VERSION 5.8 ;
BUSBITCHARS "[]" ;
DIVIDERCHAR "/" ;
UNITS
    DATABASE MICRONS 1000 ;
END UNITS

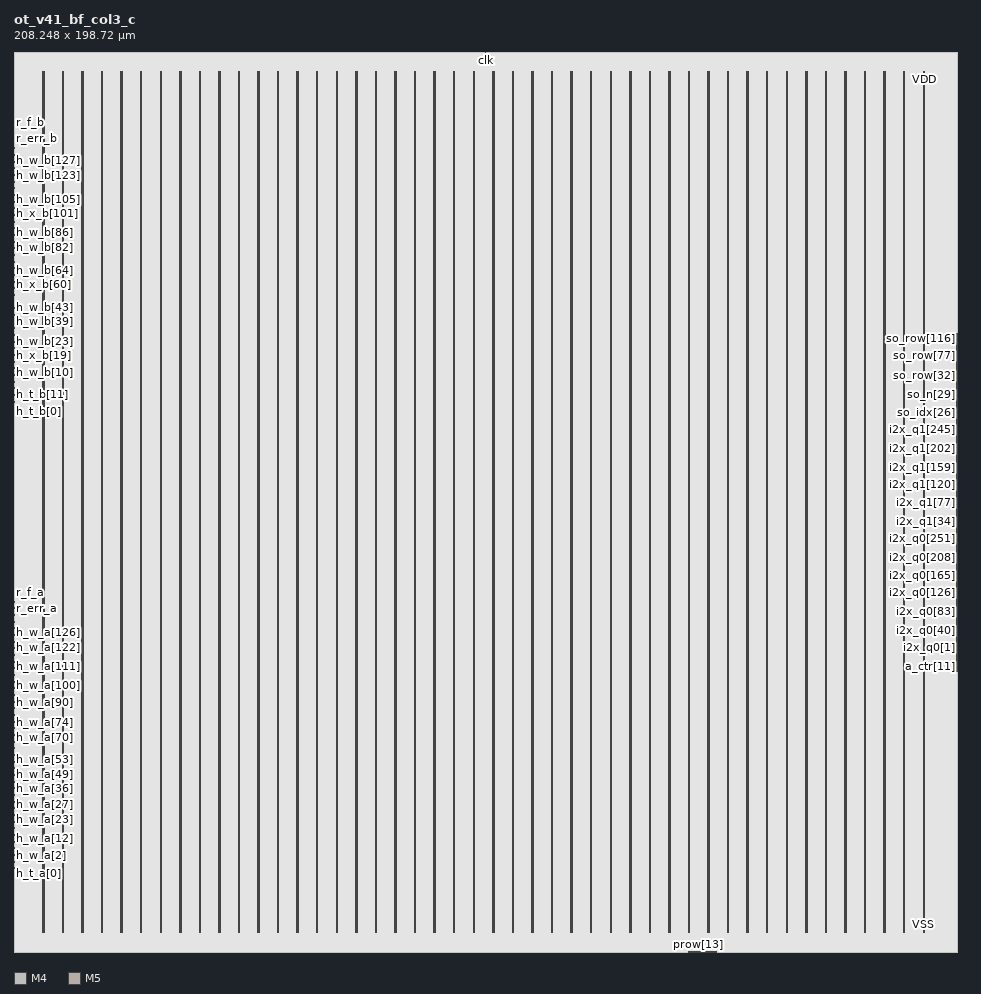
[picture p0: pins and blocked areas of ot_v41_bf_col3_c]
MACRO ot_v41_bf_col3_c
  FOREIGN ot_v41_bf_col3_c 0 0 ;
  CLASS BLOCK ;
  SIZE 208.248 BY 198.72 ;
  PIN a_ctr[0]
    DIRECTION INPUT ;
    USE SIGNAL ;
    PORT
      LAYER M4 ;
        RECT  208.164 62.016 208.248 62.04 ;
    END
  END a_ctr[0]
  PIN a_ctr[10]
    DIRECTION INPUT ;
    USE SIGNAL ;
    PORT
      LAYER M4 ;
        RECT  208.164 62.976 208.248 63 ;
    END
  END a_ctr[10]
  PIN a_ctr[11]
    DIRECTION INPUT ;
    USE SIGNAL ;
    PORT
      LAYER M4 ;
        RECT  208.164 63.072 208.248 63.096 ;
    END
  END a_ctr[11]
  PIN a_ctr[12]
    DIRECTION INPUT ;
    USE SIGNAL ;
    PORT
      LAYER M4 ;
        RECT  208.164 63.168 208.248 63.192 ;
    END
  END a_ctr[12]
  PIN a_ctr[13]
    DIRECTION INPUT ;
    USE SIGNAL ;
    PORT
      LAYER M4 ;
        RECT  208.164 63.264 208.248 63.288 ;
    END
  END a_ctr[13]
  PIN a_ctr[1]
    DIRECTION INPUT ;
    USE SIGNAL ;
    PORT
      LAYER M4 ;
        RECT  208.164 62.112 208.248 62.136 ;
    END
  END a_ctr[1]
  PIN a_ctr[2]
    DIRECTION INPUT ;
    USE SIGNAL ;
    PORT
      LAYER M4 ;
        RECT  208.164 62.208 208.248 62.232 ;
    END
  END a_ctr[2]
  PIN a_ctr[3]
    DIRECTION INPUT ;
    USE SIGNAL ;
    PORT
      LAYER M4 ;
        RECT  208.164 62.304 208.248 62.328 ;
    END
  END a_ctr[3]
  PIN a_ctr[4]
    DIRECTION INPUT ;
    USE SIGNAL ;
    PORT
      LAYER M4 ;
        RECT  208.164 62.4 208.248 62.424 ;
    END
  END a_ctr[4]
  PIN a_ctr[5]
    DIRECTION INPUT ;
    USE SIGNAL ;
    PORT
      LAYER M4 ;
        RECT  208.164 62.496 208.248 62.52 ;
    END
  END a_ctr[5]
  PIN a_ctr[6]
    DIRECTION INPUT ;
    USE SIGNAL ;
    PORT
      LAYER M4 ;
        RECT  208.164 62.592 208.248 62.616 ;
    END
  END a_ctr[6]
  PIN a_ctr[7]
    DIRECTION INPUT ;
    USE SIGNAL ;
    PORT
      LAYER M4 ;
        RECT  208.164 62.688 208.248 62.712 ;
    END
  END a_ctr[7]
  PIN a_ctr[8]
    DIRECTION INPUT ;
    USE SIGNAL ;
    PORT
      LAYER M4 ;
        RECT  208.164 62.784 208.248 62.808 ;
    END
  END a_ctr[8]
  PIN a_ctr[9]
    DIRECTION INPUT ;
    USE SIGNAL ;
    PORT
      LAYER M4 ;
        RECT  208.164 62.88 208.248 62.904 ;
    END
  END a_ctr[9]
  PIN clk
    DIRECTION INPUT ;
    USE SIGNAL ;
    PORT
      LAYER M5 ;
        RECT  104.1 198.24 104.148 198.72 ;
    END
  END clk
  PIN h_rst_a
    DIRECTION OUTPUT ;
    USE SIGNAL ;
    PORT
      LAYER M4 ;
        RECT  0 20.064 0.084 20.088 ;
    END
  END h_rst_a
  PIN h_rst_b
    DIRECTION OUTPUT ;
    USE SIGNAL ;
    PORT
      LAYER M4 ;
        RECT  0 123.744 0.084 123.768 ;
    END
  END h_rst_b
  PIN h_t_a[0]
    DIRECTION OUTPUT ;
    USE SIGNAL ;
    PORT
      LAYER M4 ;
        RECT  0 17.376 0.084 17.4 ;
    END
  END h_t_a[0]
  PIN h_t_a[10]
    DIRECTION OUTPUT ;
    USE SIGNAL ;
    PORT
      LAYER M4 ;
        RECT  0 19.296 0.084 19.32 ;
    END
  END h_t_a[10]
  PIN h_t_a[11]
    DIRECTION OUTPUT ;
    USE SIGNAL ;
    PORT
      LAYER M4 ;
        RECT  0 19.488 0.084 19.512 ;
    END
  END h_t_a[11]
  PIN h_t_a[12]
    DIRECTION OUTPUT ;
    USE SIGNAL ;
    PORT
      LAYER M4 ;
        RECT  0 19.68 0.084 19.704 ;
    END
  END h_t_a[12]
  PIN h_t_a[1]
    DIRECTION OUTPUT ;
    USE SIGNAL ;
    PORT
      LAYER M4 ;
        RECT  0 17.568 0.084 17.592 ;
    END
  END h_t_a[1]
  PIN h_t_a[2]
    DIRECTION OUTPUT ;
    USE SIGNAL ;
    PORT
      LAYER M4 ;
        RECT  0 17.76 0.084 17.784 ;
    END
  END h_t_a[2]
  PIN h_t_a[3]
    DIRECTION OUTPUT ;
    USE SIGNAL ;
    PORT
      LAYER M4 ;
        RECT  0 17.952 0.084 17.976 ;
    END
  END h_t_a[3]
  PIN h_t_a[4]
    DIRECTION OUTPUT ;
    USE SIGNAL ;
    PORT
      LAYER M4 ;
        RECT  0 18.144 0.084 18.168 ;
    END
  END h_t_a[4]
  PIN h_t_a[5]
    DIRECTION OUTPUT ;
    USE SIGNAL ;
    PORT
      LAYER M4 ;
        RECT  0 18.336 0.084 18.36 ;
    END
  END h_t_a[5]
  PIN h_t_a[6]
    DIRECTION OUTPUT ;
    USE SIGNAL ;
    PORT
      LAYER M4 ;
        RECT  0 18.528 0.084 18.552 ;
    END
  END h_t_a[6]
  PIN h_t_a[7]
    DIRECTION OUTPUT ;
    USE SIGNAL ;
    PORT
      LAYER M4 ;
        RECT  0 18.72 0.084 18.744 ;
    END
  END h_t_a[7]
  PIN h_t_a[8]
    DIRECTION OUTPUT ;
    USE SIGNAL ;
    PORT
      LAYER M4 ;
        RECT  0 18.912 0.084 18.936 ;
    END
  END h_t_a[8]
  PIN h_t_a[9]
    DIRECTION OUTPUT ;
    USE SIGNAL ;
    PORT
      LAYER M4 ;
        RECT  0 19.104 0.084 19.128 ;
    END
  END h_t_a[9]
  PIN h_t_b[0]
    DIRECTION OUTPUT ;
    USE SIGNAL ;
    PORT
      LAYER M4 ;
        RECT  0 121.056 0.084 121.08 ;
    END
  END h_t_b[0]
  PIN h_t_b[10]
    DIRECTION OUTPUT ;
    USE SIGNAL ;
    PORT
      LAYER M4 ;
        RECT  0 122.976 0.084 123 ;
    END
  END h_t_b[10]
  PIN h_t_b[11]
    DIRECTION OUTPUT ;
    USE SIGNAL ;
    PORT
      LAYER M4 ;
        RECT  0 123.168 0.084 123.192 ;
    END
  END h_t_b[11]
  PIN h_t_b[12]
    DIRECTION OUTPUT ;
    USE SIGNAL ;
    PORT
      LAYER M4 ;
        RECT  0 123.36 0.084 123.384 ;
    END
  END h_t_b[12]
  PIN h_t_b[1]
    DIRECTION OUTPUT ;
    USE SIGNAL ;
    PORT
      LAYER M4 ;
        RECT  0 121.248 0.084 121.272 ;
    END
  END h_t_b[1]
  PIN h_t_b[2]
    DIRECTION OUTPUT ;
    USE SIGNAL ;
    PORT
      LAYER M4 ;
        RECT  0 121.44 0.084 121.464 ;
    END
  END h_t_b[2]
  PIN h_t_b[3]
    DIRECTION OUTPUT ;
    USE SIGNAL ;
    PORT
      LAYER M4 ;
        RECT  0 121.632 0.084 121.656 ;
    END
  END h_t_b[3]
  PIN h_t_b[4]
    DIRECTION OUTPUT ;
    USE SIGNAL ;
    PORT
      LAYER M4 ;
        RECT  0 121.824 0.084 121.848 ;
    END
  END h_t_b[4]
  PIN h_t_b[5]
    DIRECTION OUTPUT ;
    USE SIGNAL ;
    PORT
      LAYER M4 ;
        RECT  0 122.016 0.084 122.04 ;
    END
  END h_t_b[5]
  PIN h_t_b[6]
    DIRECTION OUTPUT ;
    USE SIGNAL ;
    PORT
      LAYER M4 ;
        RECT  0 122.208 0.084 122.232 ;
    END
  END h_t_b[6]
  PIN h_t_b[7]
    DIRECTION OUTPUT ;
    USE SIGNAL ;
    PORT
      LAYER M4 ;
        RECT  0 122.4 0.084 122.424 ;
    END
  END h_t_b[7]
  PIN h_t_b[8]
    DIRECTION OUTPUT ;
    USE SIGNAL ;
    PORT
      LAYER M4 ;
        RECT  0 122.592 0.084 122.616 ;
    END
  END h_t_b[8]
  PIN h_t_b[9]
    DIRECTION OUTPUT ;
    USE SIGNAL ;
    PORT
      LAYER M4 ;
        RECT  0 122.784 0.084 122.808 ;
    END
  END h_t_b[9]
  PIN h_v_a
    DIRECTION OUTPUT ;
    USE SIGNAL ;
    PORT
      LAYER M4 ;
        RECT  0 19.872 0.084 19.896 ;
    END
  END h_v_a
  PIN h_v_b
    DIRECTION OUTPUT ;
    USE SIGNAL ;
    PORT
      LAYER M4 ;
        RECT  0 123.552 0.084 123.576 ;
    END
  END h_v_b
  PIN h_w_a[0]
    DIRECTION OUTPUT ;
    USE SIGNAL ;
    PORT
      LAYER M4 ;
        RECT  0 20.448 0.084 20.472 ;
    END
  END h_w_a[0]
  PIN h_w_a[100]
    DIRECTION OUTPUT ;
    USE SIGNAL ;
    PORT
      LAYER M4 ;
        RECT  0 58.848 0.084 58.872 ;
    END
  END h_w_a[100]
  PIN h_w_a[101]
    DIRECTION OUTPUT ;
    USE SIGNAL ;
    PORT
      LAYER M4 ;
        RECT  0 59.232 0.084 59.256 ;
    END
  END h_w_a[101]
  PIN h_w_a[102]
    DIRECTION OUTPUT ;
    USE SIGNAL ;
    PORT
      LAYER M4 ;
        RECT  0 59.616 0.084 59.64 ;
    END
  END h_w_a[102]
  PIN h_w_a[103]
    DIRECTION OUTPUT ;
    USE SIGNAL ;
    PORT
      LAYER M4 ;
        RECT  0 60 0.084 60.024 ;
    END
  END h_w_a[103]
  PIN h_w_a[104]
    DIRECTION OUTPUT ;
    USE SIGNAL ;
    PORT
      LAYER M4 ;
        RECT  0 60.384 0.084 60.408 ;
    END
  END h_w_a[104]
  PIN h_w_a[105]
    DIRECTION OUTPUT ;
    USE SIGNAL ;
    PORT
      LAYER M4 ;
        RECT  0 60.768 0.084 60.792 ;
    END
  END h_w_a[105]
  PIN h_w_a[106]
    DIRECTION OUTPUT ;
    USE SIGNAL ;
    PORT
      LAYER M4 ;
        RECT  0 61.152 0.084 61.176 ;
    END
  END h_w_a[106]
  PIN h_w_a[107]
    DIRECTION OUTPUT ;
    USE SIGNAL ;
    PORT
      LAYER M4 ;
        RECT  0 61.536 0.084 61.56 ;
    END
  END h_w_a[107]
  PIN h_w_a[108]
    DIRECTION OUTPUT ;
    USE SIGNAL ;
    PORT
      LAYER M4 ;
        RECT  0 61.92 0.084 61.944 ;
    END
  END h_w_a[108]
  PIN h_w_a[109]
    DIRECTION OUTPUT ;
    USE SIGNAL ;
    PORT
      LAYER M4 ;
        RECT  0 62.304 0.084 62.328 ;
    END
  END h_w_a[109]
  PIN h_w_a[10]
    DIRECTION OUTPUT ;
    USE SIGNAL ;
    PORT
      LAYER M4 ;
        RECT  0 24.288 0.084 24.312 ;
    END
  END h_w_a[10]
  PIN h_w_a[110]
    DIRECTION OUTPUT ;
    USE SIGNAL ;
    PORT
      LAYER M4 ;
        RECT  0 62.688 0.084 62.712 ;
    END
  END h_w_a[110]
  PIN h_w_a[111]
    DIRECTION OUTPUT ;
    USE SIGNAL ;
    PORT
      LAYER M4 ;
        RECT  0 63.072 0.084 63.096 ;
    END
  END h_w_a[111]
  PIN h_w_a[112]
    DIRECTION OUTPUT ;
    USE SIGNAL ;
    PORT
      LAYER M4 ;
        RECT  0 63.456 0.084 63.48 ;
    END
  END h_w_a[112]
  PIN h_w_a[113]
    DIRECTION OUTPUT ;
    USE SIGNAL ;
    PORT
      LAYER M4 ;
        RECT  0 63.84 0.084 63.864 ;
    END
  END h_w_a[113]
  PIN h_w_a[114]
    DIRECTION OUTPUT ;
    USE SIGNAL ;
    PORT
      LAYER M4 ;
        RECT  0 64.224 0.084 64.248 ;
    END
  END h_w_a[114]
  PIN h_w_a[115]
    DIRECTION OUTPUT ;
    USE SIGNAL ;
    PORT
      LAYER M4 ;
        RECT  0 64.608 0.084 64.632 ;
    END
  END h_w_a[115]
  PIN h_w_a[116]
    DIRECTION OUTPUT ;
    USE SIGNAL ;
    PORT
      LAYER M4 ;
        RECT  0 64.992 0.084 65.016 ;
    END
  END h_w_a[116]
  PIN h_w_a[117]
    DIRECTION OUTPUT ;
    USE SIGNAL ;
    PORT
      LAYER M4 ;
        RECT  0 65.376 0.084 65.4 ;
    END
  END h_w_a[117]
  PIN h_w_a[118]
    DIRECTION OUTPUT ;
    USE SIGNAL ;
    PORT
      LAYER M4 ;
        RECT  0 65.76 0.084 65.784 ;
    END
  END h_w_a[118]
  PIN h_w_a[119]
    DIRECTION OUTPUT ;
    USE SIGNAL ;
    PORT
      LAYER M4 ;
        RECT  0 66.144 0.084 66.168 ;
    END
  END h_w_a[119]
  PIN h_w_a[11]
    DIRECTION OUTPUT ;
    USE SIGNAL ;
    PORT
      LAYER M4 ;
        RECT  0 24.672 0.084 24.696 ;
    END
  END h_w_a[11]
  PIN h_w_a[120]
    DIRECTION OUTPUT ;
    USE SIGNAL ;
    PORT
      LAYER M4 ;
        RECT  0 66.528 0.084 66.552 ;
    END
  END h_w_a[120]
  PIN h_w_a[121]
    DIRECTION OUTPUT ;
    USE SIGNAL ;
    PORT
      LAYER M4 ;
        RECT  0 66.912 0.084 66.936 ;
    END
  END h_w_a[121]
  PIN h_w_a[122]
    DIRECTION OUTPUT ;
    USE SIGNAL ;
    PORT
      LAYER M4 ;
        RECT  0 67.296 0.084 67.32 ;
    END
  END h_w_a[122]
  PIN h_w_a[123]
    DIRECTION OUTPUT ;
    USE SIGNAL ;
    PORT
      LAYER M4 ;
        RECT  0 67.68 0.084 67.704 ;
    END
  END h_w_a[123]
  PIN h_w_a[124]
    DIRECTION OUTPUT ;
    USE SIGNAL ;
    PORT
      LAYER M4 ;
        RECT  0 68.064 0.084 68.088 ;
    END
  END h_w_a[124]
  PIN h_w_a[125]
    DIRECTION OUTPUT ;
    USE SIGNAL ;
    PORT
      LAYER M4 ;
        RECT  0 68.448 0.084 68.472 ;
    END
  END h_w_a[125]
  PIN h_w_a[126]
    DIRECTION OUTPUT ;
    USE SIGNAL ;
    PORT
      LAYER M4 ;
        RECT  0 68.832 0.084 68.856 ;
    END
  END h_w_a[126]
  PIN h_w_a[127]
    DIRECTION OUTPUT ;
    USE SIGNAL ;
    PORT
      LAYER M4 ;
        RECT  0 69.216 0.084 69.24 ;
    END
  END h_w_a[127]
  PIN h_w_a[12]
    DIRECTION OUTPUT ;
    USE SIGNAL ;
    PORT
      LAYER M4 ;
        RECT  0 25.056 0.084 25.08 ;
    END
  END h_w_a[12]
  PIN h_w_a[13]
    DIRECTION OUTPUT ;
    USE SIGNAL ;
    PORT
      LAYER M4 ;
        RECT  0 25.44 0.084 25.464 ;
    END
  END h_w_a[13]
  PIN h_w_a[14]
    DIRECTION OUTPUT ;
    USE SIGNAL ;
    PORT
      LAYER M4 ;
        RECT  0 25.824 0.084 25.848 ;
    END
  END h_w_a[14]
  PIN h_w_a[15]
    DIRECTION OUTPUT ;
    USE SIGNAL ;
    PORT
      LAYER M4 ;
        RECT  0 26.208 0.084 26.232 ;
    END
  END h_w_a[15]
  PIN h_w_a[16]
    DIRECTION OUTPUT ;
    USE SIGNAL ;
    PORT
      LAYER M4 ;
        RECT  0 26.592 0.084 26.616 ;
    END
  END h_w_a[16]
  PIN h_w_a[17]
    DIRECTION OUTPUT ;
    USE SIGNAL ;
    PORT
      LAYER M4 ;
        RECT  0 26.976 0.084 27 ;
    END
  END h_w_a[17]
  PIN h_w_a[18]
    DIRECTION OUTPUT ;
    USE SIGNAL ;
    PORT
      LAYER M4 ;
        RECT  0 27.36 0.084 27.384 ;
    END
  END h_w_a[18]
  PIN h_w_a[19]
    DIRECTION OUTPUT ;
    USE SIGNAL ;
    PORT
      LAYER M4 ;
        RECT  0 27.744 0.084 27.768 ;
    END
  END h_w_a[19]
  PIN h_w_a[1]
    DIRECTION OUTPUT ;
    USE SIGNAL ;
    PORT
      LAYER M4 ;
        RECT  0 20.832 0.084 20.856 ;
    END
  END h_w_a[1]
  PIN h_w_a[20]
    DIRECTION OUTPUT ;
    USE SIGNAL ;
    PORT
      LAYER M4 ;
        RECT  0 28.128 0.084 28.152 ;
    END
  END h_w_a[20]
  PIN h_w_a[21]
    DIRECTION OUTPUT ;
    USE SIGNAL ;
    PORT
      LAYER M4 ;
        RECT  0 28.512 0.084 28.536 ;
    END
  END h_w_a[21]
  PIN h_w_a[22]
    DIRECTION OUTPUT ;
    USE SIGNAL ;
    PORT
      LAYER M4 ;
        RECT  0 28.896 0.084 28.92 ;
    END
  END h_w_a[22]
  PIN h_w_a[23]
    DIRECTION OUTPUT ;
    USE SIGNAL ;
    PORT
      LAYER M4 ;
        RECT  0 29.28 0.084 29.304 ;
    END
  END h_w_a[23]
  PIN h_w_a[24]
    DIRECTION OUTPUT ;
    USE SIGNAL ;
    PORT
      LAYER M4 ;
        RECT  0 29.664 0.084 29.688 ;
    END
  END h_w_a[24]
  PIN h_w_a[25]
    DIRECTION OUTPUT ;
    USE SIGNAL ;
    PORT
      LAYER M4 ;
        RECT  0 30.048 0.084 30.072 ;
    END
  END h_w_a[25]
  PIN h_w_a[26]
    DIRECTION OUTPUT ;
    USE SIGNAL ;
    PORT
      LAYER M4 ;
        RECT  0 30.432 0.084 30.456 ;
    END
  END h_w_a[26]
  PIN h_w_a[27]
    DIRECTION OUTPUT ;
    USE SIGNAL ;
    PORT
      LAYER M4 ;
        RECT  0 30.816 0.084 30.84 ;
    END
  END h_w_a[27]
  PIN h_w_a[28]
    DIRECTION OUTPUT ;
    USE SIGNAL ;
    PORT
      LAYER M4 ;
        RECT  0 31.2 0.084 31.224 ;
    END
  END h_w_a[28]
  PIN h_w_a[29]
    DIRECTION OUTPUT ;
    USE SIGNAL ;
    PORT
      LAYER M4 ;
        RECT  0 31.584 0.084 31.608 ;
    END
  END h_w_a[29]
  PIN h_w_a[2]
    DIRECTION OUTPUT ;
    USE SIGNAL ;
    PORT
      LAYER M4 ;
        RECT  0 21.216 0.084 21.24 ;
    END
  END h_w_a[2]
  PIN h_w_a[30]
    DIRECTION OUTPUT ;
    USE SIGNAL ;
    PORT
      LAYER M4 ;
        RECT  0 31.968 0.084 31.992 ;
    END
  END h_w_a[30]
  PIN h_w_a[31]
    DIRECTION OUTPUT ;
    USE SIGNAL ;
    PORT
      LAYER M4 ;
        RECT  0 32.352 0.084 32.376 ;
    END
  END h_w_a[31]
  PIN h_w_a[32]
    DIRECTION OUTPUT ;
    USE SIGNAL ;
    PORT
      LAYER M4 ;
        RECT  0 32.736 0.084 32.76 ;
    END
  END h_w_a[32]
  PIN h_w_a[33]
    DIRECTION OUTPUT ;
    USE SIGNAL ;
    PORT
      LAYER M4 ;
        RECT  0 33.12 0.084 33.144 ;
    END
  END h_w_a[33]
  PIN h_w_a[34]
    DIRECTION OUTPUT ;
    USE SIGNAL ;
    PORT
      LAYER M4 ;
        RECT  0 33.504 0.084 33.528 ;
    END
  END h_w_a[34]
  PIN h_w_a[35]
    DIRECTION OUTPUT ;
    USE SIGNAL ;
    PORT
      LAYER M4 ;
        RECT  0 33.888 0.084 33.912 ;
    END
  END h_w_a[35]
  PIN h_w_a[36]
    DIRECTION OUTPUT ;
    USE SIGNAL ;
    PORT
      LAYER M4 ;
        RECT  0 34.272 0.084 34.296 ;
    END
  END h_w_a[36]
  PIN h_w_a[37]
    DIRECTION OUTPUT ;
    USE SIGNAL ;
    PORT
      LAYER M4 ;
        RECT  0 34.656 0.084 34.68 ;
    END
  END h_w_a[37]
  PIN h_w_a[38]
    DIRECTION OUTPUT ;
    USE SIGNAL ;
    PORT
      LAYER M4 ;
        RECT  0 35.04 0.084 35.064 ;
    END
  END h_w_a[38]
  PIN h_w_a[39]
    DIRECTION OUTPUT ;
    USE SIGNAL ;
    PORT
      LAYER M4 ;
        RECT  0 35.424 0.084 35.448 ;
    END
  END h_w_a[39]
  PIN h_w_a[3]
    DIRECTION OUTPUT ;
    USE SIGNAL ;
    PORT
      LAYER M4 ;
        RECT  0 21.6 0.084 21.624 ;
    END
  END h_w_a[3]
  PIN h_w_a[40]
    DIRECTION OUTPUT ;
    USE SIGNAL ;
    PORT
      LAYER M4 ;
        RECT  0 35.808 0.084 35.832 ;
    END
  END h_w_a[40]
  PIN h_w_a[41]
    DIRECTION OUTPUT ;
    USE SIGNAL ;
    PORT
      LAYER M4 ;
        RECT  0 36.192 0.084 36.216 ;
    END
  END h_w_a[41]
  PIN h_w_a[42]
    DIRECTION OUTPUT ;
    USE SIGNAL ;
    PORT
      LAYER M4 ;
        RECT  0 36.576 0.084 36.6 ;
    END
  END h_w_a[42]
  PIN h_w_a[43]
    DIRECTION OUTPUT ;
    USE SIGNAL ;
    PORT
      LAYER M4 ;
        RECT  0 36.96 0.084 36.984 ;
    END
  END h_w_a[43]
  PIN h_w_a[44]
    DIRECTION OUTPUT ;
    USE SIGNAL ;
    PORT
      LAYER M4 ;
        RECT  0 37.344 0.084 37.368 ;
    END
  END h_w_a[44]
  PIN h_w_a[45]
    DIRECTION OUTPUT ;
    USE SIGNAL ;
    PORT
      LAYER M4 ;
        RECT  0 37.728 0.084 37.752 ;
    END
  END h_w_a[45]
  PIN h_w_a[46]
    DIRECTION OUTPUT ;
    USE SIGNAL ;
    PORT
      LAYER M4 ;
        RECT  0 38.112 0.084 38.136 ;
    END
  END h_w_a[46]
  PIN h_w_a[47]
    DIRECTION OUTPUT ;
    USE SIGNAL ;
    PORT
      LAYER M4 ;
        RECT  0 38.496 0.084 38.52 ;
    END
  END h_w_a[47]
  PIN h_w_a[48]
    DIRECTION OUTPUT ;
    USE SIGNAL ;
    PORT
      LAYER M4 ;
        RECT  0 38.88 0.084 38.904 ;
    END
  END h_w_a[48]
  PIN h_w_a[49]
    DIRECTION OUTPUT ;
    USE SIGNAL ;
    PORT
      LAYER M4 ;
        RECT  0 39.264 0.084 39.288 ;
    END
  END h_w_a[49]
  PIN h_w_a[4]
    DIRECTION OUTPUT ;
    USE SIGNAL ;
    PORT
      LAYER M4 ;
        RECT  0 21.984 0.084 22.008 ;
    END
  END h_w_a[4]
  PIN h_w_a[50]
    DIRECTION OUTPUT ;
    USE SIGNAL ;
    PORT
      LAYER M4 ;
        RECT  0 39.648 0.084 39.672 ;
    END
  END h_w_a[50]
  PIN h_w_a[51]
    DIRECTION OUTPUT ;
    USE SIGNAL ;
    PORT
      LAYER M4 ;
        RECT  0 40.032 0.084 40.056 ;
    END
  END h_w_a[51]
  PIN h_w_a[52]
    DIRECTION OUTPUT ;
    USE SIGNAL ;
    PORT
      LAYER M4 ;
        RECT  0 40.416 0.084 40.44 ;
    END
  END h_w_a[52]
  PIN h_w_a[53]
    DIRECTION OUTPUT ;
    USE SIGNAL ;
    PORT
      LAYER M4 ;
        RECT  0 40.8 0.084 40.824 ;
    END
  END h_w_a[53]
  PIN h_w_a[54]
    DIRECTION OUTPUT ;
    USE SIGNAL ;
    PORT
      LAYER M4 ;
        RECT  0 41.184 0.084 41.208 ;
    END
  END h_w_a[54]
  PIN h_w_a[55]
    DIRECTION OUTPUT ;
    USE SIGNAL ;
    PORT
      LAYER M4 ;
        RECT  0 41.568 0.084 41.592 ;
    END
  END h_w_a[55]
  PIN h_w_a[56]
    DIRECTION OUTPUT ;
    USE SIGNAL ;
    PORT
      LAYER M4 ;
        RECT  0 41.952 0.084 41.976 ;
    END
  END h_w_a[56]
  PIN h_w_a[57]
    DIRECTION OUTPUT ;
    USE SIGNAL ;
    PORT
      LAYER M4 ;
        RECT  0 42.336 0.084 42.36 ;
    END
  END h_w_a[57]
  PIN h_w_a[58]
    DIRECTION OUTPUT ;
    USE SIGNAL ;
    PORT
      LAYER M4 ;
        RECT  0 42.72 0.084 42.744 ;
    END
  END h_w_a[58]
  PIN h_w_a[59]
    DIRECTION OUTPUT ;
    USE SIGNAL ;
    PORT
      LAYER M4 ;
        RECT  0 43.104 0.084 43.128 ;
    END
  END h_w_a[59]
  PIN h_w_a[5]
    DIRECTION OUTPUT ;
    USE SIGNAL ;
    PORT
      LAYER M4 ;
        RECT  0 22.368 0.084 22.392 ;
    END
  END h_w_a[5]
  PIN h_w_a[60]
    DIRECTION OUTPUT ;
    USE SIGNAL ;
    PORT
      LAYER M4 ;
        RECT  0 43.488 0.084 43.512 ;
    END
  END h_w_a[60]
  PIN h_w_a[61]
    DIRECTION OUTPUT ;
    USE SIGNAL ;
    PORT
      LAYER M4 ;
        RECT  0 43.872 0.084 43.896 ;
    END
  END h_w_a[61]
  PIN h_w_a[62]
    DIRECTION OUTPUT ;
    USE SIGNAL ;
    PORT
      LAYER M4 ;
        RECT  0 44.256 0.084 44.28 ;
    END
  END h_w_a[62]
  PIN h_w_a[63]
    DIRECTION OUTPUT ;
    USE SIGNAL ;
    PORT
      LAYER M4 ;
        RECT  0 44.64 0.084 44.664 ;
    END
  END h_w_a[63]
  PIN h_w_a[64]
    DIRECTION OUTPUT ;
    USE SIGNAL ;
    PORT
      LAYER M4 ;
        RECT  0 45.024 0.084 45.048 ;
    END
  END h_w_a[64]
  PIN h_w_a[65]
    DIRECTION OUTPUT ;
    USE SIGNAL ;
    PORT
      LAYER M4 ;
        RECT  0 45.408 0.084 45.432 ;
    END
  END h_w_a[65]
  PIN h_w_a[66]
    DIRECTION OUTPUT ;
    USE SIGNAL ;
    PORT
      LAYER M4 ;
        RECT  0 45.792 0.084 45.816 ;
    END
  END h_w_a[66]
  PIN h_w_a[67]
    DIRECTION OUTPUT ;
    USE SIGNAL ;
    PORT
      LAYER M4 ;
        RECT  0 46.176 0.084 46.2 ;
    END
  END h_w_a[67]
  PIN h_w_a[68]
    DIRECTION OUTPUT ;
    USE SIGNAL ;
    PORT
      LAYER M4 ;
        RECT  0 46.56 0.084 46.584 ;
    END
  END h_w_a[68]
  PIN h_w_a[69]
    DIRECTION OUTPUT ;
    USE SIGNAL ;
    PORT
      LAYER M4 ;
        RECT  0 46.944 0.084 46.968 ;
    END
  END h_w_a[69]
  PIN h_w_a[6]
    DIRECTION OUTPUT ;
    USE SIGNAL ;
    PORT
      LAYER M4 ;
        RECT  0 22.752 0.084 22.776 ;
    END
  END h_w_a[6]
  PIN h_w_a[70]
    DIRECTION OUTPUT ;
    USE SIGNAL ;
    PORT
      LAYER M4 ;
        RECT  0 47.328 0.084 47.352 ;
    END
  END h_w_a[70]
  PIN h_w_a[71]
    DIRECTION OUTPUT ;
    USE SIGNAL ;
    PORT
      LAYER M4 ;
        RECT  0 47.712 0.084 47.736 ;
    END
  END h_w_a[71]
  PIN h_w_a[72]
    DIRECTION OUTPUT ;
    USE SIGNAL ;
    PORT
      LAYER M4 ;
        RECT  0 48.096 0.084 48.12 ;
    END
  END h_w_a[72]
  PIN h_w_a[73]
    DIRECTION OUTPUT ;
    USE SIGNAL ;
    PORT
      LAYER M4 ;
        RECT  0 48.48 0.084 48.504 ;
    END
  END h_w_a[73]
  PIN h_w_a[74]
    DIRECTION OUTPUT ;
    USE SIGNAL ;
    PORT
      LAYER M4 ;
        RECT  0 48.864 0.084 48.888 ;
    END
  END h_w_a[74]
  PIN h_w_a[75]
    DIRECTION OUTPUT ;
    USE SIGNAL ;
    PORT
      LAYER M4 ;
        RECT  0 49.248 0.084 49.272 ;
    END
  END h_w_a[75]
  PIN h_w_a[76]
    DIRECTION OUTPUT ;
    USE SIGNAL ;
    PORT
      LAYER M4 ;
        RECT  0 49.632 0.084 49.656 ;
    END
  END h_w_a[76]
  PIN h_w_a[77]
    DIRECTION OUTPUT ;
    USE SIGNAL ;
    PORT
      LAYER M4 ;
        RECT  0 50.016 0.084 50.04 ;
    END
  END h_w_a[77]
  PIN h_w_a[78]
    DIRECTION OUTPUT ;
    USE SIGNAL ;
    PORT
      LAYER M4 ;
        RECT  0 50.4 0.084 50.424 ;
    END
  END h_w_a[78]
  PIN h_w_a[79]
    DIRECTION OUTPUT ;
    USE SIGNAL ;
    PORT
      LAYER M4 ;
        RECT  0 50.784 0.084 50.808 ;
    END
  END h_w_a[79]
  PIN h_w_a[7]
    DIRECTION OUTPUT ;
    USE SIGNAL ;
    PORT
      LAYER M4 ;
        RECT  0 23.136 0.084 23.16 ;
    END
  END h_w_a[7]
  PIN h_w_a[80]
    DIRECTION OUTPUT ;
    USE SIGNAL ;
    PORT
      LAYER M4 ;
        RECT  0 51.168 0.084 51.192 ;
    END
  END h_w_a[80]
  PIN h_w_a[81]
    DIRECTION OUTPUT ;
    USE SIGNAL ;
    PORT
      LAYER M4 ;
        RECT  0 51.552 0.084 51.576 ;
    END
  END h_w_a[81]
  PIN h_w_a[82]
    DIRECTION OUTPUT ;
    USE SIGNAL ;
    PORT
      LAYER M4 ;
        RECT  0 51.936 0.084 51.96 ;
    END
  END h_w_a[82]
  PIN h_w_a[83]
    DIRECTION OUTPUT ;
    USE SIGNAL ;
    PORT
      LAYER M4 ;
        RECT  0 52.32 0.084 52.344 ;
    END
  END h_w_a[83]
  PIN h_w_a[84]
    DIRECTION OUTPUT ;
    USE SIGNAL ;
    PORT
      LAYER M4 ;
        RECT  0 52.704 0.084 52.728 ;
    END
  END h_w_a[84]
  PIN h_w_a[85]
    DIRECTION OUTPUT ;
    USE SIGNAL ;
    PORT
      LAYER M4 ;
        RECT  0 53.088 0.084 53.112 ;
    END
  END h_w_a[85]
  PIN h_w_a[86]
    DIRECTION OUTPUT ;
    USE SIGNAL ;
    PORT
      LAYER M4 ;
        RECT  0 53.472 0.084 53.496 ;
    END
  END h_w_a[86]
  PIN h_w_a[87]
    DIRECTION OUTPUT ;
    USE SIGNAL ;
    PORT
      LAYER M4 ;
        RECT  0 53.856 0.084 53.88 ;
    END
  END h_w_a[87]
  PIN h_w_a[88]
    DIRECTION OUTPUT ;
    USE SIGNAL ;
    PORT
      LAYER M4 ;
        RECT  0 54.24 0.084 54.264 ;
    END
  END h_w_a[88]
  PIN h_w_a[89]
    DIRECTION OUTPUT ;
    USE SIGNAL ;
    PORT
      LAYER M4 ;
        RECT  0 54.624 0.084 54.648 ;
    END
  END h_w_a[89]
  PIN h_w_a[8]
    DIRECTION OUTPUT ;
    USE SIGNAL ;
    PORT
      LAYER M4 ;
        RECT  0 23.52 0.084 23.544 ;
    END
  END h_w_a[8]
  PIN h_w_a[90]
    DIRECTION OUTPUT ;
    USE SIGNAL ;
    PORT
      LAYER M4 ;
        RECT  0 55.008 0.084 55.032 ;
    END
  END h_w_a[90]
  PIN h_w_a[91]
    DIRECTION OUTPUT ;
    USE SIGNAL ;
    PORT
      LAYER M4 ;
        RECT  0 55.392 0.084 55.416 ;
    END
  END h_w_a[91]
  PIN h_w_a[92]
    DIRECTION OUTPUT ;
    USE SIGNAL ;
    PORT
      LAYER M4 ;
        RECT  0 55.776 0.084 55.8 ;
    END
  END h_w_a[92]
  PIN h_w_a[93]
    DIRECTION OUTPUT ;
    USE SIGNAL ;
    PORT
      LAYER M4 ;
        RECT  0 56.16 0.084 56.184 ;
    END
  END h_w_a[93]
  PIN h_w_a[94]
    DIRECTION OUTPUT ;
    USE SIGNAL ;
    PORT
      LAYER M4 ;
        RECT  0 56.544 0.084 56.568 ;
    END
  END h_w_a[94]
  PIN h_w_a[95]
    DIRECTION OUTPUT ;
    USE SIGNAL ;
    PORT
      LAYER M4 ;
        RECT  0 56.928 0.084 56.952 ;
    END
  END h_w_a[95]
  PIN h_w_a[96]
    DIRECTION OUTPUT ;
    USE SIGNAL ;
    PORT
      LAYER M4 ;
        RECT  0 57.312 0.084 57.336 ;
    END
  END h_w_a[96]
  PIN h_w_a[97]
    DIRECTION OUTPUT ;
    USE SIGNAL ;
    PORT
      LAYER M4 ;
        RECT  0 57.696 0.084 57.72 ;
    END
  END h_w_a[97]
  PIN h_w_a[98]
    DIRECTION OUTPUT ;
    USE SIGNAL ;
    PORT
      LAYER M4 ;
        RECT  0 58.08 0.084 58.104 ;
    END
  END h_w_a[98]
  PIN h_w_a[99]
    DIRECTION OUTPUT ;
    USE SIGNAL ;
    PORT
      LAYER M4 ;
        RECT  0 58.464 0.084 58.488 ;
    END
  END h_w_a[99]
  PIN h_w_a[9]
    DIRECTION OUTPUT ;
    USE SIGNAL ;
    PORT
      LAYER M4 ;
        RECT  0 23.904 0.084 23.928 ;
    END
  END h_w_a[9]
  PIN h_w_b[0]
    DIRECTION OUTPUT ;
    USE SIGNAL ;
    PORT
      LAYER M4 ;
        RECT  0 124.128 0.084 124.152 ;
    END
  END h_w_b[0]
  PIN h_w_b[100]
    DIRECTION OUTPUT ;
    USE SIGNAL ;
    PORT
      LAYER M4 ;
        RECT  0 162.528 0.084 162.552 ;
    END
  END h_w_b[100]
  PIN h_w_b[101]
    DIRECTION OUTPUT ;
    USE SIGNAL ;
    PORT
      LAYER M4 ;
        RECT  0 162.912 0.084 162.936 ;
    END
  END h_w_b[101]
  PIN h_w_b[102]
    DIRECTION OUTPUT ;
    USE SIGNAL ;
    PORT
      LAYER M4 ;
        RECT  0 163.296 0.084 163.32 ;
    END
  END h_w_b[102]
  PIN h_w_b[103]
    DIRECTION OUTPUT ;
    USE SIGNAL ;
    PORT
      LAYER M4 ;
        RECT  0 163.68 0.084 163.704 ;
    END
  END h_w_b[103]
  PIN h_w_b[104]
    DIRECTION OUTPUT ;
    USE SIGNAL ;
    PORT
      LAYER M4 ;
        RECT  0 164.064 0.084 164.088 ;
    END
  END h_w_b[104]
  PIN h_w_b[105]
    DIRECTION OUTPUT ;
    USE SIGNAL ;
    PORT
      LAYER M4 ;
        RECT  0 164.448 0.084 164.472 ;
    END
  END h_w_b[105]
  PIN h_w_b[106]
    DIRECTION OUTPUT ;
    USE SIGNAL ;
    PORT
      LAYER M4 ;
        RECT  0 164.832 0.084 164.856 ;
    END
  END h_w_b[106]
  PIN h_w_b[107]
    DIRECTION OUTPUT ;
    USE SIGNAL ;
    PORT
      LAYER M4 ;
        RECT  0 165.216 0.084 165.24 ;
    END
  END h_w_b[107]
  PIN h_w_b[108]
    DIRECTION OUTPUT ;
    USE SIGNAL ;
    PORT
      LAYER M4 ;
        RECT  0 165.6 0.084 165.624 ;
    END
  END h_w_b[108]
  PIN h_w_b[109]
    DIRECTION OUTPUT ;
    USE SIGNAL ;
    PORT
      LAYER M4 ;
        RECT  0 165.984 0.084 166.008 ;
    END
  END h_w_b[109]
  PIN h_w_b[10]
    DIRECTION OUTPUT ;
    USE SIGNAL ;
    PORT
      LAYER M4 ;
        RECT  0 127.968 0.084 127.992 ;
    END
  END h_w_b[10]
  PIN h_w_b[110]
    DIRECTION OUTPUT ;
    USE SIGNAL ;
    PORT
      LAYER M4 ;
        RECT  0 166.368 0.084 166.392 ;
    END
  END h_w_b[110]
  PIN h_w_b[111]
    DIRECTION OUTPUT ;
    USE SIGNAL ;
    PORT
      LAYER M4 ;
        RECT  0 166.752 0.084 166.776 ;
    END
  END h_w_b[111]
  PIN h_w_b[112]
    DIRECTION OUTPUT ;
    USE SIGNAL ;
    PORT
      LAYER M4 ;
        RECT  0 167.136 0.084 167.16 ;
    END
  END h_w_b[112]
  PIN h_w_b[113]
    DIRECTION OUTPUT ;
    USE SIGNAL ;
    PORT
      LAYER M4 ;
        RECT  0 167.52 0.084 167.544 ;
    END
  END h_w_b[113]
  PIN h_w_b[114]
    DIRECTION OUTPUT ;
    USE SIGNAL ;
    PORT
      LAYER M4 ;
        RECT  0 167.904 0.084 167.928 ;
    END
  END h_w_b[114]
  PIN h_w_b[115]
    DIRECTION OUTPUT ;
    USE SIGNAL ;
    PORT
      LAYER M4 ;
        RECT  0 168.288 0.084 168.312 ;
    END
  END h_w_b[115]
  PIN h_w_b[116]
    DIRECTION OUTPUT ;
    USE SIGNAL ;
    PORT
      LAYER M4 ;
        RECT  0 168.672 0.084 168.696 ;
    END
  END h_w_b[116]
  PIN h_w_b[117]
    DIRECTION OUTPUT ;
    USE SIGNAL ;
    PORT
      LAYER M4 ;
        RECT  0 169.056 0.084 169.08 ;
    END
  END h_w_b[117]
  PIN h_w_b[118]
    DIRECTION OUTPUT ;
    USE SIGNAL ;
    PORT
      LAYER M4 ;
        RECT  0 169.44 0.084 169.464 ;
    END
  END h_w_b[118]
  PIN h_w_b[119]
    DIRECTION OUTPUT ;
    USE SIGNAL ;
    PORT
      LAYER M4 ;
        RECT  0 169.824 0.084 169.848 ;
    END
  END h_w_b[119]
  PIN h_w_b[11]
    DIRECTION OUTPUT ;
    USE SIGNAL ;
    PORT
      LAYER M4 ;
        RECT  0 128.352 0.084 128.376 ;
    END
  END h_w_b[11]
  PIN h_w_b[120]
    DIRECTION OUTPUT ;
    USE SIGNAL ;
    PORT
      LAYER M4 ;
        RECT  0 170.208 0.084 170.232 ;
    END
  END h_w_b[120]
  PIN h_w_b[121]
    DIRECTION OUTPUT ;
    USE SIGNAL ;
    PORT
      LAYER M4 ;
        RECT  0 170.592 0.084 170.616 ;
    END
  END h_w_b[121]
  PIN h_w_b[122]
    DIRECTION OUTPUT ;
    USE SIGNAL ;
    PORT
      LAYER M4 ;
        RECT  0 170.976 0.084 171 ;
    END
  END h_w_b[122]
  PIN h_w_b[123]
    DIRECTION OUTPUT ;
    USE SIGNAL ;
    PORT
      LAYER M4 ;
        RECT  0 171.36 0.084 171.384 ;
    END
  END h_w_b[123]
  PIN h_w_b[124]
    DIRECTION OUTPUT ;
    USE SIGNAL ;
    PORT
      LAYER M4 ;
        RECT  0 171.744 0.084 171.768 ;
    END
  END h_w_b[124]
  PIN h_w_b[125]
    DIRECTION OUTPUT ;
    USE SIGNAL ;
    PORT
      LAYER M4 ;
        RECT  0 172.128 0.084 172.152 ;
    END
  END h_w_b[125]
  PIN h_w_b[126]
    DIRECTION OUTPUT ;
    USE SIGNAL ;
    PORT
      LAYER M4 ;
        RECT  0 172.512 0.084 172.536 ;
    END
  END h_w_b[126]
  PIN h_w_b[127]
    DIRECTION OUTPUT ;
    USE SIGNAL ;
    PORT
      LAYER M4 ;
        RECT  0 172.896 0.084 172.92 ;
    END
  END h_w_b[127]
  PIN h_w_b[12]
    DIRECTION OUTPUT ;
    USE SIGNAL ;
    PORT
      LAYER M4 ;
        RECT  0 128.736 0.084 128.76 ;
    END
  END h_w_b[12]
  PIN h_w_b[13]
    DIRECTION OUTPUT ;
    USE SIGNAL ;
    PORT
      LAYER M4 ;
        RECT  0 129.12 0.084 129.144 ;
    END
  END h_w_b[13]
  PIN h_w_b[14]
    DIRECTION OUTPUT ;
    USE SIGNAL ;
    PORT
      LAYER M4 ;
        RECT  0 129.504 0.084 129.528 ;
    END
  END h_w_b[14]
  PIN h_w_b[15]
    DIRECTION OUTPUT ;
    USE SIGNAL ;
    PORT
      LAYER M4 ;
        RECT  0 129.888 0.084 129.912 ;
    END
  END h_w_b[15]
  PIN h_w_b[16]
    DIRECTION OUTPUT ;
    USE SIGNAL ;
    PORT
      LAYER M4 ;
        RECT  0 130.272 0.084 130.296 ;
    END
  END h_w_b[16]
  PIN h_w_b[17]
    DIRECTION OUTPUT ;
    USE SIGNAL ;
    PORT
      LAYER M4 ;
        RECT  0 130.656 0.084 130.68 ;
    END
  END h_w_b[17]
  PIN h_w_b[18]
    DIRECTION OUTPUT ;
    USE SIGNAL ;
    PORT
      LAYER M4 ;
        RECT  0 131.04 0.084 131.064 ;
    END
  END h_w_b[18]
  PIN h_w_b[19]
    DIRECTION OUTPUT ;
    USE SIGNAL ;
    PORT
      LAYER M4 ;
        RECT  0 131.424 0.084 131.448 ;
    END
  END h_w_b[19]
  PIN h_w_b[1]
    DIRECTION OUTPUT ;
    USE SIGNAL ;
    PORT
      LAYER M4 ;
        RECT  0 124.512 0.084 124.536 ;
    END
  END h_w_b[1]
  PIN h_w_b[20]
    DIRECTION OUTPUT ;
    USE SIGNAL ;
    PORT
      LAYER M4 ;
        RECT  0 131.808 0.084 131.832 ;
    END
  END h_w_b[20]
  PIN h_w_b[21]
    DIRECTION OUTPUT ;
    USE SIGNAL ;
    PORT
      LAYER M4 ;
        RECT  0 132.192 0.084 132.216 ;
    END
  END h_w_b[21]
  PIN h_w_b[22]
    DIRECTION OUTPUT ;
    USE SIGNAL ;
    PORT
      LAYER M4 ;
        RECT  0 132.576 0.084 132.6 ;
    END
  END h_w_b[22]
  PIN h_w_b[23]
    DIRECTION OUTPUT ;
    USE SIGNAL ;
    PORT
      LAYER M4 ;
        RECT  0 132.96 0.084 132.984 ;
    END
  END h_w_b[23]
  PIN h_w_b[24]
    DIRECTION OUTPUT ;
    USE SIGNAL ;
    PORT
      LAYER M4 ;
        RECT  0 133.344 0.084 133.368 ;
    END
  END h_w_b[24]
  PIN h_w_b[25]
    DIRECTION OUTPUT ;
    USE SIGNAL ;
    PORT
      LAYER M4 ;
        RECT  0 133.728 0.084 133.752 ;
    END
  END h_w_b[25]
  PIN h_w_b[26]
    DIRECTION OUTPUT ;
    USE SIGNAL ;
    PORT
      LAYER M4 ;
        RECT  0 134.112 0.084 134.136 ;
    END
  END h_w_b[26]
  PIN h_w_b[27]
    DIRECTION OUTPUT ;
    USE SIGNAL ;
    PORT
      LAYER M4 ;
        RECT  0 134.496 0.084 134.52 ;
    END
  END h_w_b[27]
  PIN h_w_b[28]
    DIRECTION OUTPUT ;
    USE SIGNAL ;
    PORT
      LAYER M4 ;
        RECT  0 134.88 0.084 134.904 ;
    END
  END h_w_b[28]
  PIN h_w_b[29]
    DIRECTION OUTPUT ;
    USE SIGNAL ;
    PORT
      LAYER M4 ;
        RECT  0 135.264 0.084 135.288 ;
    END
  END h_w_b[29]
  PIN h_w_b[2]
    DIRECTION OUTPUT ;
    USE SIGNAL ;
    PORT
      LAYER M4 ;
        RECT  0 124.896 0.084 124.92 ;
    END
  END h_w_b[2]
  PIN h_w_b[30]
    DIRECTION OUTPUT ;
    USE SIGNAL ;
    PORT
      LAYER M4 ;
        RECT  0 135.648 0.084 135.672 ;
    END
  END h_w_b[30]
  PIN h_w_b[31]
    DIRECTION OUTPUT ;
    USE SIGNAL ;
    PORT
      LAYER M4 ;
        RECT  0 136.032 0.084 136.056 ;
    END
  END h_w_b[31]
  PIN h_w_b[32]
    DIRECTION OUTPUT ;
    USE SIGNAL ;
    PORT
      LAYER M4 ;
        RECT  0 136.416 0.084 136.44 ;
    END
  END h_w_b[32]
  PIN h_w_b[33]
    DIRECTION OUTPUT ;
    USE SIGNAL ;
    PORT
      LAYER M4 ;
        RECT  0 136.8 0.084 136.824 ;
    END
  END h_w_b[33]
  PIN h_w_b[34]
    DIRECTION OUTPUT ;
    USE SIGNAL ;
    PORT
      LAYER M4 ;
        RECT  0 137.184 0.084 137.208 ;
    END
  END h_w_b[34]
  PIN h_w_b[35]
    DIRECTION OUTPUT ;
    USE SIGNAL ;
    PORT
      LAYER M4 ;
        RECT  0 137.568 0.084 137.592 ;
    END
  END h_w_b[35]
  PIN h_w_b[36]
    DIRECTION OUTPUT ;
    USE SIGNAL ;
    PORT
      LAYER M4 ;
        RECT  0 137.952 0.084 137.976 ;
    END
  END h_w_b[36]
  PIN h_w_b[37]
    DIRECTION OUTPUT ;
    USE SIGNAL ;
    PORT
      LAYER M4 ;
        RECT  0 138.336 0.084 138.36 ;
    END
  END h_w_b[37]
  PIN h_w_b[38]
    DIRECTION OUTPUT ;
    USE SIGNAL ;
    PORT
      LAYER M4 ;
        RECT  0 138.72 0.084 138.744 ;
    END
  END h_w_b[38]
  PIN h_w_b[39]
    DIRECTION OUTPUT ;
    USE SIGNAL ;
    PORT
      LAYER M4 ;
        RECT  0 139.104 0.084 139.128 ;
    END
  END h_w_b[39]
  PIN h_w_b[3]
    DIRECTION OUTPUT ;
    USE SIGNAL ;
    PORT
      LAYER M4 ;
        RECT  0 125.28 0.084 125.304 ;
    END
  END h_w_b[3]
  PIN h_w_b[40]
    DIRECTION OUTPUT ;
    USE SIGNAL ;
    PORT
      LAYER M4 ;
        RECT  0 139.488 0.084 139.512 ;
    END
  END h_w_b[40]
  PIN h_w_b[41]
    DIRECTION OUTPUT ;
    USE SIGNAL ;
    PORT
      LAYER M4 ;
        RECT  0 139.872 0.084 139.896 ;
    END
  END h_w_b[41]
  PIN h_w_b[42]
    DIRECTION OUTPUT ;
    USE SIGNAL ;
    PORT
      LAYER M4 ;
        RECT  0 140.256 0.084 140.28 ;
    END
  END h_w_b[42]
  PIN h_w_b[43]
    DIRECTION OUTPUT ;
    USE SIGNAL ;
    PORT
      LAYER M4 ;
        RECT  0 140.64 0.084 140.664 ;
    END
  END h_w_b[43]
  PIN h_w_b[44]
    DIRECTION OUTPUT ;
    USE SIGNAL ;
    PORT
      LAYER M4 ;
        RECT  0 141.024 0.084 141.048 ;
    END
  END h_w_b[44]
  PIN h_w_b[45]
    DIRECTION OUTPUT ;
    USE SIGNAL ;
    PORT
      LAYER M4 ;
        RECT  0 141.408 0.084 141.432 ;
    END
  END h_w_b[45]
  PIN h_w_b[46]
    DIRECTION OUTPUT ;
    USE SIGNAL ;
    PORT
      LAYER M4 ;
        RECT  0 141.792 0.084 141.816 ;
    END
  END h_w_b[46]
  PIN h_w_b[47]
    DIRECTION OUTPUT ;
    USE SIGNAL ;
    PORT
      LAYER M4 ;
        RECT  0 142.176 0.084 142.2 ;
    END
  END h_w_b[47]
  PIN h_w_b[48]
    DIRECTION OUTPUT ;
    USE SIGNAL ;
    PORT
      LAYER M4 ;
        RECT  0 142.56 0.084 142.584 ;
    END
  END h_w_b[48]
  PIN h_w_b[49]
    DIRECTION OUTPUT ;
    USE SIGNAL ;
    PORT
      LAYER M4 ;
        RECT  0 142.944 0.084 142.968 ;
    END
  END h_w_b[49]
  PIN h_w_b[4]
    DIRECTION OUTPUT ;
    USE SIGNAL ;
    PORT
      LAYER M4 ;
        RECT  0 125.664 0.084 125.688 ;
    END
  END h_w_b[4]
  PIN h_w_b[50]
    DIRECTION OUTPUT ;
    USE SIGNAL ;
    PORT
      LAYER M4 ;
        RECT  0 143.328 0.084 143.352 ;
    END
  END h_w_b[50]
  PIN h_w_b[51]
    DIRECTION OUTPUT ;
    USE SIGNAL ;
    PORT
      LAYER M4 ;
        RECT  0 143.712 0.084 143.736 ;
    END
  END h_w_b[51]
  PIN h_w_b[52]
    DIRECTION OUTPUT ;
    USE SIGNAL ;
    PORT
      LAYER M4 ;
        RECT  0 144.096 0.084 144.12 ;
    END
  END h_w_b[52]
  PIN h_w_b[53]
    DIRECTION OUTPUT ;
    USE SIGNAL ;
    PORT
      LAYER M4 ;
        RECT  0 144.48 0.084 144.504 ;
    END
  END h_w_b[53]
  PIN h_w_b[54]
    DIRECTION OUTPUT ;
    USE SIGNAL ;
    PORT
      LAYER M4 ;
        RECT  0 144.864 0.084 144.888 ;
    END
  END h_w_b[54]
  PIN h_w_b[55]
    DIRECTION OUTPUT ;
    USE SIGNAL ;
    PORT
      LAYER M4 ;
        RECT  0 145.248 0.084 145.272 ;
    END
  END h_w_b[55]
  PIN h_w_b[56]
    DIRECTION OUTPUT ;
    USE SIGNAL ;
    PORT
      LAYER M4 ;
        RECT  0 145.632 0.084 145.656 ;
    END
  END h_w_b[56]
  PIN h_w_b[57]
    DIRECTION OUTPUT ;
    USE SIGNAL ;
    PORT
      LAYER M4 ;
        RECT  0 146.016 0.084 146.04 ;
    END
  END h_w_b[57]
  PIN h_w_b[58]
    DIRECTION OUTPUT ;
    USE SIGNAL ;
    PORT
      LAYER M4 ;
        RECT  0 146.4 0.084 146.424 ;
    END
  END h_w_b[58]
  PIN h_w_b[59]
    DIRECTION OUTPUT ;
    USE SIGNAL ;
    PORT
      LAYER M4 ;
        RECT  0 146.784 0.084 146.808 ;
    END
  END h_w_b[59]
  PIN h_w_b[5]
    DIRECTION OUTPUT ;
    USE SIGNAL ;
    PORT
      LAYER M4 ;
        RECT  0 126.048 0.084 126.072 ;
    END
  END h_w_b[5]
  PIN h_w_b[60]
    DIRECTION OUTPUT ;
    USE SIGNAL ;
    PORT
      LAYER M4 ;
        RECT  0 147.168 0.084 147.192 ;
    END
  END h_w_b[60]
  PIN h_w_b[61]
    DIRECTION OUTPUT ;
    USE SIGNAL ;
    PORT
      LAYER M4 ;
        RECT  0 147.552 0.084 147.576 ;
    END
  END h_w_b[61]
  PIN h_w_b[62]
    DIRECTION OUTPUT ;
    USE SIGNAL ;
    PORT
      LAYER M4 ;
        RECT  0 147.936 0.084 147.96 ;
    END
  END h_w_b[62]
  PIN h_w_b[63]
    DIRECTION OUTPUT ;
    USE SIGNAL ;
    PORT
      LAYER M4 ;
        RECT  0 148.32 0.084 148.344 ;
    END
  END h_w_b[63]
  PIN h_w_b[64]
    DIRECTION OUTPUT ;
    USE SIGNAL ;
    PORT
      LAYER M4 ;
        RECT  0 148.704 0.084 148.728 ;
    END
  END h_w_b[64]
  PIN h_w_b[65]
    DIRECTION OUTPUT ;
    USE SIGNAL ;
    PORT
      LAYER M4 ;
        RECT  0 149.088 0.084 149.112 ;
    END
  END h_w_b[65]
  PIN h_w_b[66]
    DIRECTION OUTPUT ;
    USE SIGNAL ;
    PORT
      LAYER M4 ;
        RECT  0 149.472 0.084 149.496 ;
    END
  END h_w_b[66]
  PIN h_w_b[67]
    DIRECTION OUTPUT ;
    USE SIGNAL ;
    PORT
      LAYER M4 ;
        RECT  0 149.856 0.084 149.88 ;
    END
  END h_w_b[67]
  PIN h_w_b[68]
    DIRECTION OUTPUT ;
    USE SIGNAL ;
    PORT
      LAYER M4 ;
        RECT  0 150.24 0.084 150.264 ;
    END
  END h_w_b[68]
  PIN h_w_b[69]
    DIRECTION OUTPUT ;
    USE SIGNAL ;
    PORT
      LAYER M4 ;
        RECT  0 150.624 0.084 150.648 ;
    END
  END h_w_b[69]
  PIN h_w_b[6]
    DIRECTION OUTPUT ;
    USE SIGNAL ;
    PORT
      LAYER M4 ;
        RECT  0 126.432 0.084 126.456 ;
    END
  END h_w_b[6]
  PIN h_w_b[70]
    DIRECTION OUTPUT ;
    USE SIGNAL ;
    PORT
      LAYER M4 ;
        RECT  0 151.008 0.084 151.032 ;
    END
  END h_w_b[70]
  PIN h_w_b[71]
    DIRECTION OUTPUT ;
    USE SIGNAL ;
    PORT
      LAYER M4 ;
        RECT  0 151.392 0.084 151.416 ;
    END
  END h_w_b[71]
  PIN h_w_b[72]
    DIRECTION OUTPUT ;
    USE SIGNAL ;
    PORT
      LAYER M4 ;
        RECT  0 151.776 0.084 151.8 ;
    END
  END h_w_b[72]
  PIN h_w_b[73]
    DIRECTION OUTPUT ;
    USE SIGNAL ;
    PORT
      LAYER M4 ;
        RECT  0 152.16 0.084 152.184 ;
    END
  END h_w_b[73]
  PIN h_w_b[74]
    DIRECTION OUTPUT ;
    USE SIGNAL ;
    PORT
      LAYER M4 ;
        RECT  0 152.544 0.084 152.568 ;
    END
  END h_w_b[74]
  PIN h_w_b[75]
    DIRECTION OUTPUT ;
    USE SIGNAL ;
    PORT
      LAYER M4 ;
        RECT  0 152.928 0.084 152.952 ;
    END
  END h_w_b[75]
  PIN h_w_b[76]
    DIRECTION OUTPUT ;
    USE SIGNAL ;
    PORT
      LAYER M4 ;
        RECT  0 153.312 0.084 153.336 ;
    END
  END h_w_b[76]
  PIN h_w_b[77]
    DIRECTION OUTPUT ;
    USE SIGNAL ;
    PORT
      LAYER M4 ;
        RECT  0 153.696 0.084 153.72 ;
    END
  END h_w_b[77]
  PIN h_w_b[78]
    DIRECTION OUTPUT ;
    USE SIGNAL ;
    PORT
      LAYER M4 ;
        RECT  0 154.08 0.084 154.104 ;
    END
  END h_w_b[78]
  PIN h_w_b[79]
    DIRECTION OUTPUT ;
    USE SIGNAL ;
    PORT
      LAYER M4 ;
        RECT  0 154.464 0.084 154.488 ;
    END
  END h_w_b[79]
  PIN h_w_b[7]
    DIRECTION OUTPUT ;
    USE SIGNAL ;
    PORT
      LAYER M4 ;
        RECT  0 126.816 0.084 126.84 ;
    END
  END h_w_b[7]
  PIN h_w_b[80]
    DIRECTION OUTPUT ;
    USE SIGNAL ;
    PORT
      LAYER M4 ;
        RECT  0 154.848 0.084 154.872 ;
    END
  END h_w_b[80]
  PIN h_w_b[81]
    DIRECTION OUTPUT ;
    USE SIGNAL ;
    PORT
      LAYER M4 ;
        RECT  0 155.232 0.084 155.256 ;
    END
  END h_w_b[81]
  PIN h_w_b[82]
    DIRECTION OUTPUT ;
    USE SIGNAL ;
    PORT
      LAYER M4 ;
        RECT  0 155.616 0.084 155.64 ;
    END
  END h_w_b[82]
  PIN h_w_b[83]
    DIRECTION OUTPUT ;
    USE SIGNAL ;
    PORT
      LAYER M4 ;
        RECT  0 156 0.084 156.024 ;
    END
  END h_w_b[83]
  PIN h_w_b[84]
    DIRECTION OUTPUT ;
    USE SIGNAL ;
    PORT
      LAYER M4 ;
        RECT  0 156.384 0.084 156.408 ;
    END
  END h_w_b[84]
  PIN h_w_b[85]
    DIRECTION OUTPUT ;
    USE SIGNAL ;
    PORT
      LAYER M4 ;
        RECT  0 156.768 0.084 156.792 ;
    END
  END h_w_b[85]
  PIN h_w_b[86]
    DIRECTION OUTPUT ;
    USE SIGNAL ;
    PORT
      LAYER M4 ;
        RECT  0 157.152 0.084 157.176 ;
    END
  END h_w_b[86]
  PIN h_w_b[87]
    DIRECTION OUTPUT ;
    USE SIGNAL ;
    PORT
      LAYER M4 ;
        RECT  0 157.536 0.084 157.56 ;
    END
  END h_w_b[87]
  PIN h_w_b[88]
    DIRECTION OUTPUT ;
    USE SIGNAL ;
    PORT
      LAYER M4 ;
        RECT  0 157.92 0.084 157.944 ;
    END
  END h_w_b[88]
  PIN h_w_b[89]
    DIRECTION OUTPUT ;
    USE SIGNAL ;
    PORT
      LAYER M4 ;
        RECT  0 158.304 0.084 158.328 ;
    END
  END h_w_b[89]
  PIN h_w_b[8]
    DIRECTION OUTPUT ;
    USE SIGNAL ;
    PORT
      LAYER M4 ;
        RECT  0 127.2 0.084 127.224 ;
    END
  END h_w_b[8]
  PIN h_w_b[90]
    DIRECTION OUTPUT ;
    USE SIGNAL ;
    PORT
      LAYER M4 ;
        RECT  0 158.688 0.084 158.712 ;
    END
  END h_w_b[90]
  PIN h_w_b[91]
    DIRECTION OUTPUT ;
    USE SIGNAL ;
    PORT
      LAYER M4 ;
        RECT  0 159.072 0.084 159.096 ;
    END
  END h_w_b[91]
  PIN h_w_b[92]
    DIRECTION OUTPUT ;
    USE SIGNAL ;
    PORT
      LAYER M4 ;
        RECT  0 159.456 0.084 159.48 ;
    END
  END h_w_b[92]
  PIN h_w_b[93]
    DIRECTION OUTPUT ;
    USE SIGNAL ;
    PORT
      LAYER M4 ;
        RECT  0 159.84 0.084 159.864 ;
    END
  END h_w_b[93]
  PIN h_w_b[94]
    DIRECTION OUTPUT ;
    USE SIGNAL ;
    PORT
      LAYER M4 ;
        RECT  0 160.224 0.084 160.248 ;
    END
  END h_w_b[94]
  PIN h_w_b[95]
    DIRECTION OUTPUT ;
    USE SIGNAL ;
    PORT
      LAYER M4 ;
        RECT  0 160.608 0.084 160.632 ;
    END
  END h_w_b[95]
  PIN h_w_b[96]
    DIRECTION OUTPUT ;
    USE SIGNAL ;
    PORT
      LAYER M4 ;
        RECT  0 160.992 0.084 161.016 ;
    END
  END h_w_b[96]
  PIN h_w_b[97]
    DIRECTION OUTPUT ;
    USE SIGNAL ;
    PORT
      LAYER M4 ;
        RECT  0 161.376 0.084 161.4 ;
    END
  END h_w_b[97]
  PIN h_w_b[98]
    DIRECTION OUTPUT ;
    USE SIGNAL ;
    PORT
      LAYER M4 ;
        RECT  0 161.76 0.084 161.784 ;
    END
  END h_w_b[98]
  PIN h_w_b[99]
    DIRECTION OUTPUT ;
    USE SIGNAL ;
    PORT
      LAYER M4 ;
        RECT  0 162.144 0.084 162.168 ;
    END
  END h_w_b[99]
  PIN h_w_b[9]
    DIRECTION OUTPUT ;
    USE SIGNAL ;
    PORT
      LAYER M4 ;
        RECT  0 127.584 0.084 127.608 ;
    END
  END h_w_b[9]
  PIN h_x_a[0]
    DIRECTION OUTPUT ;
    USE SIGNAL ;
    PORT
      LAYER M4 ;
        RECT  0 20.64 0.084 20.664 ;
    END
  END h_x_a[0]
  PIN h_x_a[100]
    DIRECTION OUTPUT ;
    USE SIGNAL ;
    PORT
      LAYER M4 ;
        RECT  0 59.04 0.084 59.064 ;
    END
  END h_x_a[100]
  PIN h_x_a[101]
    DIRECTION OUTPUT ;
    USE SIGNAL ;
    PORT
      LAYER M4 ;
        RECT  0 59.424 0.084 59.448 ;
    END
  END h_x_a[101]
  PIN h_x_a[102]
    DIRECTION OUTPUT ;
    USE SIGNAL ;
    PORT
      LAYER M4 ;
        RECT  0 59.808 0.084 59.832 ;
    END
  END h_x_a[102]
  PIN h_x_a[103]
    DIRECTION OUTPUT ;
    USE SIGNAL ;
    PORT
      LAYER M4 ;
        RECT  0 60.192 0.084 60.216 ;
    END
  END h_x_a[103]
  PIN h_x_a[104]
    DIRECTION OUTPUT ;
    USE SIGNAL ;
    PORT
      LAYER M4 ;
        RECT  0 60.576 0.084 60.6 ;
    END
  END h_x_a[104]
  PIN h_x_a[105]
    DIRECTION OUTPUT ;
    USE SIGNAL ;
    PORT
      LAYER M4 ;
        RECT  0 60.96 0.084 60.984 ;
    END
  END h_x_a[105]
  PIN h_x_a[106]
    DIRECTION OUTPUT ;
    USE SIGNAL ;
    PORT
      LAYER M4 ;
        RECT  0 61.344 0.084 61.368 ;
    END
  END h_x_a[106]
  PIN h_x_a[107]
    DIRECTION OUTPUT ;
    USE SIGNAL ;
    PORT
      LAYER M4 ;
        RECT  0 61.728 0.084 61.752 ;
    END
  END h_x_a[107]
  PIN h_x_a[108]
    DIRECTION OUTPUT ;
    USE SIGNAL ;
    PORT
      LAYER M4 ;
        RECT  0 62.112 0.084 62.136 ;
    END
  END h_x_a[108]
  PIN h_x_a[109]
    DIRECTION OUTPUT ;
    USE SIGNAL ;
    PORT
      LAYER M4 ;
        RECT  0 62.496 0.084 62.52 ;
    END
  END h_x_a[109]
  PIN h_x_a[10]
    DIRECTION OUTPUT ;
    USE SIGNAL ;
    PORT
      LAYER M4 ;
        RECT  0 24.48 0.084 24.504 ;
    END
  END h_x_a[10]
  PIN h_x_a[110]
    DIRECTION OUTPUT ;
    USE SIGNAL ;
    PORT
      LAYER M4 ;
        RECT  0 62.88 0.084 62.904 ;
    END
  END h_x_a[110]
  PIN h_x_a[111]
    DIRECTION OUTPUT ;
    USE SIGNAL ;
    PORT
      LAYER M4 ;
        RECT  0 63.264 0.084 63.288 ;
    END
  END h_x_a[111]
  PIN h_x_a[112]
    DIRECTION OUTPUT ;
    USE SIGNAL ;
    PORT
      LAYER M4 ;
        RECT  0 63.648 0.084 63.672 ;
    END
  END h_x_a[112]
  PIN h_x_a[113]
    DIRECTION OUTPUT ;
    USE SIGNAL ;
    PORT
      LAYER M4 ;
        RECT  0 64.032 0.084 64.056 ;
    END
  END h_x_a[113]
  PIN h_x_a[114]
    DIRECTION OUTPUT ;
    USE SIGNAL ;
    PORT
      LAYER M4 ;
        RECT  0 64.416 0.084 64.44 ;
    END
  END h_x_a[114]
  PIN h_x_a[115]
    DIRECTION OUTPUT ;
    USE SIGNAL ;
    PORT
      LAYER M4 ;
        RECT  0 64.8 0.084 64.824 ;
    END
  END h_x_a[115]
  PIN h_x_a[116]
    DIRECTION OUTPUT ;
    USE SIGNAL ;
    PORT
      LAYER M4 ;
        RECT  0 65.184 0.084 65.208 ;
    END
  END h_x_a[116]
  PIN h_x_a[117]
    DIRECTION OUTPUT ;
    USE SIGNAL ;
    PORT
      LAYER M4 ;
        RECT  0 65.568 0.084 65.592 ;
    END
  END h_x_a[117]
  PIN h_x_a[118]
    DIRECTION OUTPUT ;
    USE SIGNAL ;
    PORT
      LAYER M4 ;
        RECT  0 65.952 0.084 65.976 ;
    END
  END h_x_a[118]
  PIN h_x_a[119]
    DIRECTION OUTPUT ;
    USE SIGNAL ;
    PORT
      LAYER M4 ;
        RECT  0 66.336 0.084 66.36 ;
    END
  END h_x_a[119]
  PIN h_x_a[11]
    DIRECTION OUTPUT ;
    USE SIGNAL ;
    PORT
      LAYER M4 ;
        RECT  0 24.864 0.084 24.888 ;
    END
  END h_x_a[11]
  PIN h_x_a[120]
    DIRECTION OUTPUT ;
    USE SIGNAL ;
    PORT
      LAYER M4 ;
        RECT  0 66.72 0.084 66.744 ;
    END
  END h_x_a[120]
  PIN h_x_a[121]
    DIRECTION OUTPUT ;
    USE SIGNAL ;
    PORT
      LAYER M4 ;
        RECT  0 67.104 0.084 67.128 ;
    END
  END h_x_a[121]
  PIN h_x_a[122]
    DIRECTION OUTPUT ;
    USE SIGNAL ;
    PORT
      LAYER M4 ;
        RECT  0 67.488 0.084 67.512 ;
    END
  END h_x_a[122]
  PIN h_x_a[123]
    DIRECTION OUTPUT ;
    USE SIGNAL ;
    PORT
      LAYER M4 ;
        RECT  0 67.872 0.084 67.896 ;
    END
  END h_x_a[123]
  PIN h_x_a[124]
    DIRECTION OUTPUT ;
    USE SIGNAL ;
    PORT
      LAYER M4 ;
        RECT  0 68.256 0.084 68.28 ;
    END
  END h_x_a[124]
  PIN h_x_a[125]
    DIRECTION OUTPUT ;
    USE SIGNAL ;
    PORT
      LAYER M4 ;
        RECT  0 68.64 0.084 68.664 ;
    END
  END h_x_a[125]
  PIN h_x_a[126]
    DIRECTION OUTPUT ;
    USE SIGNAL ;
    PORT
      LAYER M4 ;
        RECT  0 69.024 0.084 69.048 ;
    END
  END h_x_a[126]
  PIN h_x_a[127]
    DIRECTION OUTPUT ;
    USE SIGNAL ;
    PORT
      LAYER M4 ;
        RECT  0 69.408 0.084 69.432 ;
    END
  END h_x_a[127]
  PIN h_x_a[12]
    DIRECTION OUTPUT ;
    USE SIGNAL ;
    PORT
      LAYER M4 ;
        RECT  0 25.248 0.084 25.272 ;
    END
  END h_x_a[12]
  PIN h_x_a[13]
    DIRECTION OUTPUT ;
    USE SIGNAL ;
    PORT
      LAYER M4 ;
        RECT  0 25.632 0.084 25.656 ;
    END
  END h_x_a[13]
  PIN h_x_a[14]
    DIRECTION OUTPUT ;
    USE SIGNAL ;
    PORT
      LAYER M4 ;
        RECT  0 26.016 0.084 26.04 ;
    END
  END h_x_a[14]
  PIN h_x_a[15]
    DIRECTION OUTPUT ;
    USE SIGNAL ;
    PORT
      LAYER M4 ;
        RECT  0 26.4 0.084 26.424 ;
    END
  END h_x_a[15]
  PIN h_x_a[16]
    DIRECTION OUTPUT ;
    USE SIGNAL ;
    PORT
      LAYER M4 ;
        RECT  0 26.784 0.084 26.808 ;
    END
  END h_x_a[16]
  PIN h_x_a[17]
    DIRECTION OUTPUT ;
    USE SIGNAL ;
    PORT
      LAYER M4 ;
        RECT  0 27.168 0.084 27.192 ;
    END
  END h_x_a[17]
  PIN h_x_a[18]
    DIRECTION OUTPUT ;
    USE SIGNAL ;
    PORT
      LAYER M4 ;
        RECT  0 27.552 0.084 27.576 ;
    END
  END h_x_a[18]
  PIN h_x_a[19]
    DIRECTION OUTPUT ;
    USE SIGNAL ;
    PORT
      LAYER M4 ;
        RECT  0 27.936 0.084 27.96 ;
    END
  END h_x_a[19]
  PIN h_x_a[1]
    DIRECTION OUTPUT ;
    USE SIGNAL ;
    PORT
      LAYER M4 ;
        RECT  0 21.024 0.084 21.048 ;
    END
  END h_x_a[1]
  PIN h_x_a[20]
    DIRECTION OUTPUT ;
    USE SIGNAL ;
    PORT
      LAYER M4 ;
        RECT  0 28.32 0.084 28.344 ;
    END
  END h_x_a[20]
  PIN h_x_a[21]
    DIRECTION OUTPUT ;
    USE SIGNAL ;
    PORT
      LAYER M4 ;
        RECT  0 28.704 0.084 28.728 ;
    END
  END h_x_a[21]
  PIN h_x_a[22]
    DIRECTION OUTPUT ;
    USE SIGNAL ;
    PORT
      LAYER M4 ;
        RECT  0 29.088 0.084 29.112 ;
    END
  END h_x_a[22]
  PIN h_x_a[23]
    DIRECTION OUTPUT ;
    USE SIGNAL ;
    PORT
      LAYER M4 ;
        RECT  0 29.472 0.084 29.496 ;
    END
  END h_x_a[23]
  PIN h_x_a[24]
    DIRECTION OUTPUT ;
    USE SIGNAL ;
    PORT
      LAYER M4 ;
        RECT  0 29.856 0.084 29.88 ;
    END
  END h_x_a[24]
  PIN h_x_a[25]
    DIRECTION OUTPUT ;
    USE SIGNAL ;
    PORT
      LAYER M4 ;
        RECT  0 30.24 0.084 30.264 ;
    END
  END h_x_a[25]
  PIN h_x_a[26]
    DIRECTION OUTPUT ;
    USE SIGNAL ;
    PORT
      LAYER M4 ;
        RECT  0 30.624 0.084 30.648 ;
    END
  END h_x_a[26]
  PIN h_x_a[27]
    DIRECTION OUTPUT ;
    USE SIGNAL ;
    PORT
      LAYER M4 ;
        RECT  0 31.008 0.084 31.032 ;
    END
  END h_x_a[27]
  PIN h_x_a[28]
    DIRECTION OUTPUT ;
    USE SIGNAL ;
    PORT
      LAYER M4 ;
        RECT  0 31.392 0.084 31.416 ;
    END
  END h_x_a[28]
  PIN h_x_a[29]
    DIRECTION OUTPUT ;
    USE SIGNAL ;
    PORT
      LAYER M4 ;
        RECT  0 31.776 0.084 31.8 ;
    END
  END h_x_a[29]
  PIN h_x_a[2]
    DIRECTION OUTPUT ;
    USE SIGNAL ;
    PORT
      LAYER M4 ;
        RECT  0 21.408 0.084 21.432 ;
    END
  END h_x_a[2]
  PIN h_x_a[30]
    DIRECTION OUTPUT ;
    USE SIGNAL ;
    PORT
      LAYER M4 ;
        RECT  0 32.16 0.084 32.184 ;
    END
  END h_x_a[30]
  PIN h_x_a[31]
    DIRECTION OUTPUT ;
    USE SIGNAL ;
    PORT
      LAYER M4 ;
        RECT  0 32.544 0.084 32.568 ;
    END
  END h_x_a[31]
  PIN h_x_a[32]
    DIRECTION OUTPUT ;
    USE SIGNAL ;
    PORT
      LAYER M4 ;
        RECT  0 32.928 0.084 32.952 ;
    END
  END h_x_a[32]
  PIN h_x_a[33]
    DIRECTION OUTPUT ;
    USE SIGNAL ;
    PORT
      LAYER M4 ;
        RECT  0 33.312 0.084 33.336 ;
    END
  END h_x_a[33]
  PIN h_x_a[34]
    DIRECTION OUTPUT ;
    USE SIGNAL ;
    PORT
      LAYER M4 ;
        RECT  0 33.696 0.084 33.72 ;
    END
  END h_x_a[34]
  PIN h_x_a[35]
    DIRECTION OUTPUT ;
    USE SIGNAL ;
    PORT
      LAYER M4 ;
        RECT  0 34.08 0.084 34.104 ;
    END
  END h_x_a[35]
  PIN h_x_a[36]
    DIRECTION OUTPUT ;
    USE SIGNAL ;
    PORT
      LAYER M4 ;
        RECT  0 34.464 0.084 34.488 ;
    END
  END h_x_a[36]
  PIN h_x_a[37]
    DIRECTION OUTPUT ;
    USE SIGNAL ;
    PORT
      LAYER M4 ;
        RECT  0 34.848 0.084 34.872 ;
    END
  END h_x_a[37]
  PIN h_x_a[38]
    DIRECTION OUTPUT ;
    USE SIGNAL ;
    PORT
      LAYER M4 ;
        RECT  0 35.232 0.084 35.256 ;
    END
  END h_x_a[38]
  PIN h_x_a[39]
    DIRECTION OUTPUT ;
    USE SIGNAL ;
    PORT
      LAYER M4 ;
        RECT  0 35.616 0.084 35.64 ;
    END
  END h_x_a[39]
  PIN h_x_a[3]
    DIRECTION OUTPUT ;
    USE SIGNAL ;
    PORT
      LAYER M4 ;
        RECT  0 21.792 0.084 21.816 ;
    END
  END h_x_a[3]
  PIN h_x_a[40]
    DIRECTION OUTPUT ;
    USE SIGNAL ;
    PORT
      LAYER M4 ;
        RECT  0 36 0.084 36.024 ;
    END
  END h_x_a[40]
  PIN h_x_a[41]
    DIRECTION OUTPUT ;
    USE SIGNAL ;
    PORT
      LAYER M4 ;
        RECT  0 36.384 0.084 36.408 ;
    END
  END h_x_a[41]
  PIN h_x_a[42]
    DIRECTION OUTPUT ;
    USE SIGNAL ;
    PORT
      LAYER M4 ;
        RECT  0 36.768 0.084 36.792 ;
    END
  END h_x_a[42]
  PIN h_x_a[43]
    DIRECTION OUTPUT ;
    USE SIGNAL ;
    PORT
      LAYER M4 ;
        RECT  0 37.152 0.084 37.176 ;
    END
  END h_x_a[43]
  PIN h_x_a[44]
    DIRECTION OUTPUT ;
    USE SIGNAL ;
    PORT
      LAYER M4 ;
        RECT  0 37.536 0.084 37.56 ;
    END
  END h_x_a[44]
  PIN h_x_a[45]
    DIRECTION OUTPUT ;
    USE SIGNAL ;
    PORT
      LAYER M4 ;
        RECT  0 37.92 0.084 37.944 ;
    END
  END h_x_a[45]
  PIN h_x_a[46]
    DIRECTION OUTPUT ;
    USE SIGNAL ;
    PORT
      LAYER M4 ;
        RECT  0 38.304 0.084 38.328 ;
    END
  END h_x_a[46]
  PIN h_x_a[47]
    DIRECTION OUTPUT ;
    USE SIGNAL ;
    PORT
      LAYER M4 ;
        RECT  0 38.688 0.084 38.712 ;
    END
  END h_x_a[47]
  PIN h_x_a[48]
    DIRECTION OUTPUT ;
    USE SIGNAL ;
    PORT
      LAYER M4 ;
        RECT  0 39.072 0.084 39.096 ;
    END
  END h_x_a[48]
  PIN h_x_a[49]
    DIRECTION OUTPUT ;
    USE SIGNAL ;
    PORT
      LAYER M4 ;
        RECT  0 39.456 0.084 39.48 ;
    END
  END h_x_a[49]
  PIN h_x_a[4]
    DIRECTION OUTPUT ;
    USE SIGNAL ;
    PORT
      LAYER M4 ;
        RECT  0 22.176 0.084 22.2 ;
    END
  END h_x_a[4]
  PIN h_x_a[50]
    DIRECTION OUTPUT ;
    USE SIGNAL ;
    PORT
      LAYER M4 ;
        RECT  0 39.84 0.084 39.864 ;
    END
  END h_x_a[50]
  PIN h_x_a[51]
    DIRECTION OUTPUT ;
    USE SIGNAL ;
    PORT
      LAYER M4 ;
        RECT  0 40.224 0.084 40.248 ;
    END
  END h_x_a[51]
  PIN h_x_a[52]
    DIRECTION OUTPUT ;
    USE SIGNAL ;
    PORT
      LAYER M4 ;
        RECT  0 40.608 0.084 40.632 ;
    END
  END h_x_a[52]
  PIN h_x_a[53]
    DIRECTION OUTPUT ;
    USE SIGNAL ;
    PORT
      LAYER M4 ;
        RECT  0 40.992 0.084 41.016 ;
    END
  END h_x_a[53]
  PIN h_x_a[54]
    DIRECTION OUTPUT ;
    USE SIGNAL ;
    PORT
      LAYER M4 ;
        RECT  0 41.376 0.084 41.4 ;
    END
  END h_x_a[54]
  PIN h_x_a[55]
    DIRECTION OUTPUT ;
    USE SIGNAL ;
    PORT
      LAYER M4 ;
        RECT  0 41.76 0.084 41.784 ;
    END
  END h_x_a[55]
  PIN h_x_a[56]
    DIRECTION OUTPUT ;
    USE SIGNAL ;
    PORT
      LAYER M4 ;
        RECT  0 42.144 0.084 42.168 ;
    END
  END h_x_a[56]
  PIN h_x_a[57]
    DIRECTION OUTPUT ;
    USE SIGNAL ;
    PORT
      LAYER M4 ;
        RECT  0 42.528 0.084 42.552 ;
    END
  END h_x_a[57]
  PIN h_x_a[58]
    DIRECTION OUTPUT ;
    USE SIGNAL ;
    PORT
      LAYER M4 ;
        RECT  0 42.912 0.084 42.936 ;
    END
  END h_x_a[58]
  PIN h_x_a[59]
    DIRECTION OUTPUT ;
    USE SIGNAL ;
    PORT
      LAYER M4 ;
        RECT  0 43.296 0.084 43.32 ;
    END
  END h_x_a[59]
  PIN h_x_a[5]
    DIRECTION OUTPUT ;
    USE SIGNAL ;
    PORT
      LAYER M4 ;
        RECT  0 22.56 0.084 22.584 ;
    END
  END h_x_a[5]
  PIN h_x_a[60]
    DIRECTION OUTPUT ;
    USE SIGNAL ;
    PORT
      LAYER M4 ;
        RECT  0 43.68 0.084 43.704 ;
    END
  END h_x_a[60]
  PIN h_x_a[61]
    DIRECTION OUTPUT ;
    USE SIGNAL ;
    PORT
      LAYER M4 ;
        RECT  0 44.064 0.084 44.088 ;
    END
  END h_x_a[61]
  PIN h_x_a[62]
    DIRECTION OUTPUT ;
    USE SIGNAL ;
    PORT
      LAYER M4 ;
        RECT  0 44.448 0.084 44.472 ;
    END
  END h_x_a[62]
  PIN h_x_a[63]
    DIRECTION OUTPUT ;
    USE SIGNAL ;
    PORT
      LAYER M4 ;
        RECT  0 44.832 0.084 44.856 ;
    END
  END h_x_a[63]
  PIN h_x_a[64]
    DIRECTION OUTPUT ;
    USE SIGNAL ;
    PORT
      LAYER M4 ;
        RECT  0 45.216 0.084 45.24 ;
    END
  END h_x_a[64]
  PIN h_x_a[65]
    DIRECTION OUTPUT ;
    USE SIGNAL ;
    PORT
      LAYER M4 ;
        RECT  0 45.6 0.084 45.624 ;
    END
  END h_x_a[65]
  PIN h_x_a[66]
    DIRECTION OUTPUT ;
    USE SIGNAL ;
    PORT
      LAYER M4 ;
        RECT  0 45.984 0.084 46.008 ;
    END
  END h_x_a[66]
  PIN h_x_a[67]
    DIRECTION OUTPUT ;
    USE SIGNAL ;
    PORT
      LAYER M4 ;
        RECT  0 46.368 0.084 46.392 ;
    END
  END h_x_a[67]
  PIN h_x_a[68]
    DIRECTION OUTPUT ;
    USE SIGNAL ;
    PORT
      LAYER M4 ;
        RECT  0 46.752 0.084 46.776 ;
    END
  END h_x_a[68]
  PIN h_x_a[69]
    DIRECTION OUTPUT ;
    USE SIGNAL ;
    PORT
      LAYER M4 ;
        RECT  0 47.136 0.084 47.16 ;
    END
  END h_x_a[69]
  PIN h_x_a[6]
    DIRECTION OUTPUT ;
    USE SIGNAL ;
    PORT
      LAYER M4 ;
        RECT  0 22.944 0.084 22.968 ;
    END
  END h_x_a[6]
  PIN h_x_a[70]
    DIRECTION OUTPUT ;
    USE SIGNAL ;
    PORT
      LAYER M4 ;
        RECT  0 47.52 0.084 47.544 ;
    END
  END h_x_a[70]
  PIN h_x_a[71]
    DIRECTION OUTPUT ;
    USE SIGNAL ;
    PORT
      LAYER M4 ;
        RECT  0 47.904 0.084 47.928 ;
    END
  END h_x_a[71]
  PIN h_x_a[72]
    DIRECTION OUTPUT ;
    USE SIGNAL ;
    PORT
      LAYER M4 ;
        RECT  0 48.288 0.084 48.312 ;
    END
  END h_x_a[72]
  PIN h_x_a[73]
    DIRECTION OUTPUT ;
    USE SIGNAL ;
    PORT
      LAYER M4 ;
        RECT  0 48.672 0.084 48.696 ;
    END
  END h_x_a[73]
  PIN h_x_a[74]
    DIRECTION OUTPUT ;
    USE SIGNAL ;
    PORT
      LAYER M4 ;
        RECT  0 49.056 0.084 49.08 ;
    END
  END h_x_a[74]
  PIN h_x_a[75]
    DIRECTION OUTPUT ;
    USE SIGNAL ;
    PORT
      LAYER M4 ;
        RECT  0 49.44 0.084 49.464 ;
    END
  END h_x_a[75]
  PIN h_x_a[76]
    DIRECTION OUTPUT ;
    USE SIGNAL ;
    PORT
      LAYER M4 ;
        RECT  0 49.824 0.084 49.848 ;
    END
  END h_x_a[76]
  PIN h_x_a[77]
    DIRECTION OUTPUT ;
    USE SIGNAL ;
    PORT
      LAYER M4 ;
        RECT  0 50.208 0.084 50.232 ;
    END
  END h_x_a[77]
  PIN h_x_a[78]
    DIRECTION OUTPUT ;
    USE SIGNAL ;
    PORT
      LAYER M4 ;
        RECT  0 50.592 0.084 50.616 ;
    END
  END h_x_a[78]
  PIN h_x_a[79]
    DIRECTION OUTPUT ;
    USE SIGNAL ;
    PORT
      LAYER M4 ;
        RECT  0 50.976 0.084 51 ;
    END
  END h_x_a[79]
  PIN h_x_a[7]
    DIRECTION OUTPUT ;
    USE SIGNAL ;
    PORT
      LAYER M4 ;
        RECT  0 23.328 0.084 23.352 ;
    END
  END h_x_a[7]
  PIN h_x_a[80]
    DIRECTION OUTPUT ;
    USE SIGNAL ;
    PORT
      LAYER M4 ;
        RECT  0 51.36 0.084 51.384 ;
    END
  END h_x_a[80]
  PIN h_x_a[81]
    DIRECTION OUTPUT ;
    USE SIGNAL ;
    PORT
      LAYER M4 ;
        RECT  0 51.744 0.084 51.768 ;
    END
  END h_x_a[81]
  PIN h_x_a[82]
    DIRECTION OUTPUT ;
    USE SIGNAL ;
    PORT
      LAYER M4 ;
        RECT  0 52.128 0.084 52.152 ;
    END
  END h_x_a[82]
  PIN h_x_a[83]
    DIRECTION OUTPUT ;
    USE SIGNAL ;
    PORT
      LAYER M4 ;
        RECT  0 52.512 0.084 52.536 ;
    END
  END h_x_a[83]
  PIN h_x_a[84]
    DIRECTION OUTPUT ;
    USE SIGNAL ;
    PORT
      LAYER M4 ;
        RECT  0 52.896 0.084 52.92 ;
    END
  END h_x_a[84]
  PIN h_x_a[85]
    DIRECTION OUTPUT ;
    USE SIGNAL ;
    PORT
      LAYER M4 ;
        RECT  0 53.28 0.084 53.304 ;
    END
  END h_x_a[85]
  PIN h_x_a[86]
    DIRECTION OUTPUT ;
    USE SIGNAL ;
    PORT
      LAYER M4 ;
        RECT  0 53.664 0.084 53.688 ;
    END
  END h_x_a[86]
  PIN h_x_a[87]
    DIRECTION OUTPUT ;
    USE SIGNAL ;
    PORT
      LAYER M4 ;
        RECT  0 54.048 0.084 54.072 ;
    END
  END h_x_a[87]
  PIN h_x_a[88]
    DIRECTION OUTPUT ;
    USE SIGNAL ;
    PORT
      LAYER M4 ;
        RECT  0 54.432 0.084 54.456 ;
    END
  END h_x_a[88]
  PIN h_x_a[89]
    DIRECTION OUTPUT ;
    USE SIGNAL ;
    PORT
      LAYER M4 ;
        RECT  0 54.816 0.084 54.84 ;
    END
  END h_x_a[89]
  PIN h_x_a[8]
    DIRECTION OUTPUT ;
    USE SIGNAL ;
    PORT
      LAYER M4 ;
        RECT  0 23.712 0.084 23.736 ;
    END
  END h_x_a[8]
  PIN h_x_a[90]
    DIRECTION OUTPUT ;
    USE SIGNAL ;
    PORT
      LAYER M4 ;
        RECT  0 55.2 0.084 55.224 ;
    END
  END h_x_a[90]
  PIN h_x_a[91]
    DIRECTION OUTPUT ;
    USE SIGNAL ;
    PORT
      LAYER M4 ;
        RECT  0 55.584 0.084 55.608 ;
    END
  END h_x_a[91]
  PIN h_x_a[92]
    DIRECTION OUTPUT ;
    USE SIGNAL ;
    PORT
      LAYER M4 ;
        RECT  0 55.968 0.084 55.992 ;
    END
  END h_x_a[92]
  PIN h_x_a[93]
    DIRECTION OUTPUT ;
    USE SIGNAL ;
    PORT
      LAYER M4 ;
        RECT  0 56.352 0.084 56.376 ;
    END
  END h_x_a[93]
  PIN h_x_a[94]
    DIRECTION OUTPUT ;
    USE SIGNAL ;
    PORT
      LAYER M4 ;
        RECT  0 56.736 0.084 56.76 ;
    END
  END h_x_a[94]
  PIN h_x_a[95]
    DIRECTION OUTPUT ;
    USE SIGNAL ;
    PORT
      LAYER M4 ;
        RECT  0 57.12 0.084 57.144 ;
    END
  END h_x_a[95]
  PIN h_x_a[96]
    DIRECTION OUTPUT ;
    USE SIGNAL ;
    PORT
      LAYER M4 ;
        RECT  0 57.504 0.084 57.528 ;
    END
  END h_x_a[96]
  PIN h_x_a[97]
    DIRECTION OUTPUT ;
    USE SIGNAL ;
    PORT
      LAYER M4 ;
        RECT  0 57.888 0.084 57.912 ;
    END
  END h_x_a[97]
  PIN h_x_a[98]
    DIRECTION OUTPUT ;
    USE SIGNAL ;
    PORT
      LAYER M4 ;
        RECT  0 58.272 0.084 58.296 ;
    END
  END h_x_a[98]
  PIN h_x_a[99]
    DIRECTION OUTPUT ;
    USE SIGNAL ;
    PORT
      LAYER M4 ;
        RECT  0 58.656 0.084 58.68 ;
    END
  END h_x_a[99]
  PIN h_x_a[9]
    DIRECTION OUTPUT ;
    USE SIGNAL ;
    PORT
      LAYER M4 ;
        RECT  0 24.096 0.084 24.12 ;
    END
  END h_x_a[9]
  PIN h_x_b[0]
    DIRECTION OUTPUT ;
    USE SIGNAL ;
    PORT
      LAYER M4 ;
        RECT  0 124.32 0.084 124.344 ;
    END
  END h_x_b[0]
  PIN h_x_b[100]
    DIRECTION OUTPUT ;
    USE SIGNAL ;
    PORT
      LAYER M4 ;
        RECT  0 162.72 0.084 162.744 ;
    END
  END h_x_b[100]
  PIN h_x_b[101]
    DIRECTION OUTPUT ;
    USE SIGNAL ;
    PORT
      LAYER M4 ;
        RECT  0 163.104 0.084 163.128 ;
    END
  END h_x_b[101]
  PIN h_x_b[102]
    DIRECTION OUTPUT ;
    USE SIGNAL ;
    PORT
      LAYER M4 ;
        RECT  0 163.488 0.084 163.512 ;
    END
  END h_x_b[102]
  PIN h_x_b[103]
    DIRECTION OUTPUT ;
    USE SIGNAL ;
    PORT
      LAYER M4 ;
        RECT  0 163.872 0.084 163.896 ;
    END
  END h_x_b[103]
  PIN h_x_b[104]
    DIRECTION OUTPUT ;
    USE SIGNAL ;
    PORT
      LAYER M4 ;
        RECT  0 164.256 0.084 164.28 ;
    END
  END h_x_b[104]
  PIN h_x_b[105]
    DIRECTION OUTPUT ;
    USE SIGNAL ;
    PORT
      LAYER M4 ;
        RECT  0 164.64 0.084 164.664 ;
    END
  END h_x_b[105]
  PIN h_x_b[106]
    DIRECTION OUTPUT ;
    USE SIGNAL ;
    PORT
      LAYER M4 ;
        RECT  0 165.024 0.084 165.048 ;
    END
  END h_x_b[106]
  PIN h_x_b[107]
    DIRECTION OUTPUT ;
    USE SIGNAL ;
    PORT
      LAYER M4 ;
        RECT  0 165.408 0.084 165.432 ;
    END
  END h_x_b[107]
  PIN h_x_b[108]
    DIRECTION OUTPUT ;
    USE SIGNAL ;
    PORT
      LAYER M4 ;
        RECT  0 165.792 0.084 165.816 ;
    END
  END h_x_b[108]
  PIN h_x_b[109]
    DIRECTION OUTPUT ;
    USE SIGNAL ;
    PORT
      LAYER M4 ;
        RECT  0 166.176 0.084 166.2 ;
    END
  END h_x_b[109]
  PIN h_x_b[10]
    DIRECTION OUTPUT ;
    USE SIGNAL ;
    PORT
      LAYER M4 ;
        RECT  0 128.16 0.084 128.184 ;
    END
  END h_x_b[10]
  PIN h_x_b[110]
    DIRECTION OUTPUT ;
    USE SIGNAL ;
    PORT
      LAYER M4 ;
        RECT  0 166.56 0.084 166.584 ;
    END
  END h_x_b[110]
  PIN h_x_b[111]
    DIRECTION OUTPUT ;
    USE SIGNAL ;
    PORT
      LAYER M4 ;
        RECT  0 166.944 0.084 166.968 ;
    END
  END h_x_b[111]
  PIN h_x_b[112]
    DIRECTION OUTPUT ;
    USE SIGNAL ;
    PORT
      LAYER M4 ;
        RECT  0 167.328 0.084 167.352 ;
    END
  END h_x_b[112]
  PIN h_x_b[113]
    DIRECTION OUTPUT ;
    USE SIGNAL ;
    PORT
      LAYER M4 ;
        RECT  0 167.712 0.084 167.736 ;
    END
  END h_x_b[113]
  PIN h_x_b[114]
    DIRECTION OUTPUT ;
    USE SIGNAL ;
    PORT
      LAYER M4 ;
        RECT  0 168.096 0.084 168.12 ;
    END
  END h_x_b[114]
  PIN h_x_b[115]
    DIRECTION OUTPUT ;
    USE SIGNAL ;
    PORT
      LAYER M4 ;
        RECT  0 168.48 0.084 168.504 ;
    END
  END h_x_b[115]
  PIN h_x_b[116]
    DIRECTION OUTPUT ;
    USE SIGNAL ;
    PORT
      LAYER M4 ;
        RECT  0 168.864 0.084 168.888 ;
    END
  END h_x_b[116]
  PIN h_x_b[117]
    DIRECTION OUTPUT ;
    USE SIGNAL ;
    PORT
      LAYER M4 ;
        RECT  0 169.248 0.084 169.272 ;
    END
  END h_x_b[117]
  PIN h_x_b[118]
    DIRECTION OUTPUT ;
    USE SIGNAL ;
    PORT
      LAYER M4 ;
        RECT  0 169.632 0.084 169.656 ;
    END
  END h_x_b[118]
  PIN h_x_b[119]
    DIRECTION OUTPUT ;
    USE SIGNAL ;
    PORT
      LAYER M4 ;
        RECT  0 170.016 0.084 170.04 ;
    END
  END h_x_b[119]
  PIN h_x_b[11]
    DIRECTION OUTPUT ;
    USE SIGNAL ;
    PORT
      LAYER M4 ;
        RECT  0 128.544 0.084 128.568 ;
    END
  END h_x_b[11]
  PIN h_x_b[120]
    DIRECTION OUTPUT ;
    USE SIGNAL ;
    PORT
      LAYER M4 ;
        RECT  0 170.4 0.084 170.424 ;
    END
  END h_x_b[120]
  PIN h_x_b[121]
    DIRECTION OUTPUT ;
    USE SIGNAL ;
    PORT
      LAYER M4 ;
        RECT  0 170.784 0.084 170.808 ;
    END
  END h_x_b[121]
  PIN h_x_b[122]
    DIRECTION OUTPUT ;
    USE SIGNAL ;
    PORT
      LAYER M4 ;
        RECT  0 171.168 0.084 171.192 ;
    END
  END h_x_b[122]
  PIN h_x_b[123]
    DIRECTION OUTPUT ;
    USE SIGNAL ;
    PORT
      LAYER M4 ;
        RECT  0 171.552 0.084 171.576 ;
    END
  END h_x_b[123]
  PIN h_x_b[124]
    DIRECTION OUTPUT ;
    USE SIGNAL ;
    PORT
      LAYER M4 ;
        RECT  0 171.936 0.084 171.96 ;
    END
  END h_x_b[124]
  PIN h_x_b[125]
    DIRECTION OUTPUT ;
    USE SIGNAL ;
    PORT
      LAYER M4 ;
        RECT  0 172.32 0.084 172.344 ;
    END
  END h_x_b[125]
  PIN h_x_b[126]
    DIRECTION OUTPUT ;
    USE SIGNAL ;
    PORT
      LAYER M4 ;
        RECT  0 172.704 0.084 172.728 ;
    END
  END h_x_b[126]
  PIN h_x_b[127]
    DIRECTION OUTPUT ;
    USE SIGNAL ;
    PORT
      LAYER M4 ;
        RECT  0 173.088 0.084 173.112 ;
    END
  END h_x_b[127]
  PIN h_x_b[12]
    DIRECTION OUTPUT ;
    USE SIGNAL ;
    PORT
      LAYER M4 ;
        RECT  0 128.928 0.084 128.952 ;
    END
  END h_x_b[12]
  PIN h_x_b[13]
    DIRECTION OUTPUT ;
    USE SIGNAL ;
    PORT
      LAYER M4 ;
        RECT  0 129.312 0.084 129.336 ;
    END
  END h_x_b[13]
  PIN h_x_b[14]
    DIRECTION OUTPUT ;
    USE SIGNAL ;
    PORT
      LAYER M4 ;
        RECT  0 129.696 0.084 129.72 ;
    END
  END h_x_b[14]
  PIN h_x_b[15]
    DIRECTION OUTPUT ;
    USE SIGNAL ;
    PORT
      LAYER M4 ;
        RECT  0 130.08 0.084 130.104 ;
    END
  END h_x_b[15]
  PIN h_x_b[16]
    DIRECTION OUTPUT ;
    USE SIGNAL ;
    PORT
      LAYER M4 ;
        RECT  0 130.464 0.084 130.488 ;
    END
  END h_x_b[16]
  PIN h_x_b[17]
    DIRECTION OUTPUT ;
    USE SIGNAL ;
    PORT
      LAYER M4 ;
        RECT  0 130.848 0.084 130.872 ;
    END
  END h_x_b[17]
  PIN h_x_b[18]
    DIRECTION OUTPUT ;
    USE SIGNAL ;
    PORT
      LAYER M4 ;
        RECT  0 131.232 0.084 131.256 ;
    END
  END h_x_b[18]
  PIN h_x_b[19]
    DIRECTION OUTPUT ;
    USE SIGNAL ;
    PORT
      LAYER M4 ;
        RECT  0 131.616 0.084 131.64 ;
    END
  END h_x_b[19]
  PIN h_x_b[1]
    DIRECTION OUTPUT ;
    USE SIGNAL ;
    PORT
      LAYER M4 ;
        RECT  0 124.704 0.084 124.728 ;
    END
  END h_x_b[1]
  PIN h_x_b[20]
    DIRECTION OUTPUT ;
    USE SIGNAL ;
    PORT
      LAYER M4 ;
        RECT  0 132 0.084 132.024 ;
    END
  END h_x_b[20]
  PIN h_x_b[21]
    DIRECTION OUTPUT ;
    USE SIGNAL ;
    PORT
      LAYER M4 ;
        RECT  0 132.384 0.084 132.408 ;
    END
  END h_x_b[21]
  PIN h_x_b[22]
    DIRECTION OUTPUT ;
    USE SIGNAL ;
    PORT
      LAYER M4 ;
        RECT  0 132.768 0.084 132.792 ;
    END
  END h_x_b[22]
  PIN h_x_b[23]
    DIRECTION OUTPUT ;
    USE SIGNAL ;
    PORT
      LAYER M4 ;
        RECT  0 133.152 0.084 133.176 ;
    END
  END h_x_b[23]
  PIN h_x_b[24]
    DIRECTION OUTPUT ;
    USE SIGNAL ;
    PORT
      LAYER M4 ;
        RECT  0 133.536 0.084 133.56 ;
    END
  END h_x_b[24]
  PIN h_x_b[25]
    DIRECTION OUTPUT ;
    USE SIGNAL ;
    PORT
      LAYER M4 ;
        RECT  0 133.92 0.084 133.944 ;
    END
  END h_x_b[25]
  PIN h_x_b[26]
    DIRECTION OUTPUT ;
    USE SIGNAL ;
    PORT
      LAYER M4 ;
        RECT  0 134.304 0.084 134.328 ;
    END
  END h_x_b[26]
  PIN h_x_b[27]
    DIRECTION OUTPUT ;
    USE SIGNAL ;
    PORT
      LAYER M4 ;
        RECT  0 134.688 0.084 134.712 ;
    END
  END h_x_b[27]
  PIN h_x_b[28]
    DIRECTION OUTPUT ;
    USE SIGNAL ;
    PORT
      LAYER M4 ;
        RECT  0 135.072 0.084 135.096 ;
    END
  END h_x_b[28]
  PIN h_x_b[29]
    DIRECTION OUTPUT ;
    USE SIGNAL ;
    PORT
      LAYER M4 ;
        RECT  0 135.456 0.084 135.48 ;
    END
  END h_x_b[29]
  PIN h_x_b[2]
    DIRECTION OUTPUT ;
    USE SIGNAL ;
    PORT
      LAYER M4 ;
        RECT  0 125.088 0.084 125.112 ;
    END
  END h_x_b[2]
  PIN h_x_b[30]
    DIRECTION OUTPUT ;
    USE SIGNAL ;
    PORT
      LAYER M4 ;
        RECT  0 135.84 0.084 135.864 ;
    END
  END h_x_b[30]
  PIN h_x_b[31]
    DIRECTION OUTPUT ;
    USE SIGNAL ;
    PORT
      LAYER M4 ;
        RECT  0 136.224 0.084 136.248 ;
    END
  END h_x_b[31]
  PIN h_x_b[32]
    DIRECTION OUTPUT ;
    USE SIGNAL ;
    PORT
      LAYER M4 ;
        RECT  0 136.608 0.084 136.632 ;
    END
  END h_x_b[32]
  PIN h_x_b[33]
    DIRECTION OUTPUT ;
    USE SIGNAL ;
    PORT
      LAYER M4 ;
        RECT  0 136.992 0.084 137.016 ;
    END
  END h_x_b[33]
  PIN h_x_b[34]
    DIRECTION OUTPUT ;
    USE SIGNAL ;
    PORT
      LAYER M4 ;
        RECT  0 137.376 0.084 137.4 ;
    END
  END h_x_b[34]
  PIN h_x_b[35]
    DIRECTION OUTPUT ;
    USE SIGNAL ;
    PORT
      LAYER M4 ;
        RECT  0 137.76 0.084 137.784 ;
    END
  END h_x_b[35]
  PIN h_x_b[36]
    DIRECTION OUTPUT ;
    USE SIGNAL ;
    PORT
      LAYER M4 ;
        RECT  0 138.144 0.084 138.168 ;
    END
  END h_x_b[36]
  PIN h_x_b[37]
    DIRECTION OUTPUT ;
    USE SIGNAL ;
    PORT
      LAYER M4 ;
        RECT  0 138.528 0.084 138.552 ;
    END
  END h_x_b[37]
  PIN h_x_b[38]
    DIRECTION OUTPUT ;
    USE SIGNAL ;
    PORT
      LAYER M4 ;
        RECT  0 138.912 0.084 138.936 ;
    END
  END h_x_b[38]
  PIN h_x_b[39]
    DIRECTION OUTPUT ;
    USE SIGNAL ;
    PORT
      LAYER M4 ;
        RECT  0 139.296 0.084 139.32 ;
    END
  END h_x_b[39]
  PIN h_x_b[3]
    DIRECTION OUTPUT ;
    USE SIGNAL ;
    PORT
      LAYER M4 ;
        RECT  0 125.472 0.084 125.496 ;
    END
  END h_x_b[3]
  PIN h_x_b[40]
    DIRECTION OUTPUT ;
    USE SIGNAL ;
    PORT
      LAYER M4 ;
        RECT  0 139.68 0.084 139.704 ;
    END
  END h_x_b[40]
  PIN h_x_b[41]
    DIRECTION OUTPUT ;
    USE SIGNAL ;
    PORT
      LAYER M4 ;
        RECT  0 140.064 0.084 140.088 ;
    END
  END h_x_b[41]
  PIN h_x_b[42]
    DIRECTION OUTPUT ;
    USE SIGNAL ;
    PORT
      LAYER M4 ;
        RECT  0 140.448 0.084 140.472 ;
    END
  END h_x_b[42]
  PIN h_x_b[43]
    DIRECTION OUTPUT ;
    USE SIGNAL ;
    PORT
      LAYER M4 ;
        RECT  0 140.832 0.084 140.856 ;
    END
  END h_x_b[43]
  PIN h_x_b[44]
    DIRECTION OUTPUT ;
    USE SIGNAL ;
    PORT
      LAYER M4 ;
        RECT  0 141.216 0.084 141.24 ;
    END
  END h_x_b[44]
  PIN h_x_b[45]
    DIRECTION OUTPUT ;
    USE SIGNAL ;
    PORT
      LAYER M4 ;
        RECT  0 141.6 0.084 141.624 ;
    END
  END h_x_b[45]
  PIN h_x_b[46]
    DIRECTION OUTPUT ;
    USE SIGNAL ;
    PORT
      LAYER M4 ;
        RECT  0 141.984 0.084 142.008 ;
    END
  END h_x_b[46]
  PIN h_x_b[47]
    DIRECTION OUTPUT ;
    USE SIGNAL ;
    PORT
      LAYER M4 ;
        RECT  0 142.368 0.084 142.392 ;
    END
  END h_x_b[47]
  PIN h_x_b[48]
    DIRECTION OUTPUT ;
    USE SIGNAL ;
    PORT
      LAYER M4 ;
        RECT  0 142.752 0.084 142.776 ;
    END
  END h_x_b[48]
  PIN h_x_b[49]
    DIRECTION OUTPUT ;
    USE SIGNAL ;
    PORT
      LAYER M4 ;
        RECT  0 143.136 0.084 143.16 ;
    END
  END h_x_b[49]
  PIN h_x_b[4]
    DIRECTION OUTPUT ;
    USE SIGNAL ;
    PORT
      LAYER M4 ;
        RECT  0 125.856 0.084 125.88 ;
    END
  END h_x_b[4]
  PIN h_x_b[50]
    DIRECTION OUTPUT ;
    USE SIGNAL ;
    PORT
      LAYER M4 ;
        RECT  0 143.52 0.084 143.544 ;
    END
  END h_x_b[50]
  PIN h_x_b[51]
    DIRECTION OUTPUT ;
    USE SIGNAL ;
    PORT
      LAYER M4 ;
        RECT  0 143.904 0.084 143.928 ;
    END
  END h_x_b[51]
  PIN h_x_b[52]
    DIRECTION OUTPUT ;
    USE SIGNAL ;
    PORT
      LAYER M4 ;
        RECT  0 144.288 0.084 144.312 ;
    END
  END h_x_b[52]
  PIN h_x_b[53]
    DIRECTION OUTPUT ;
    USE SIGNAL ;
    PORT
      LAYER M4 ;
        RECT  0 144.672 0.084 144.696 ;
    END
  END h_x_b[53]
  PIN h_x_b[54]
    DIRECTION OUTPUT ;
    USE SIGNAL ;
    PORT
      LAYER M4 ;
        RECT  0 145.056 0.084 145.08 ;
    END
  END h_x_b[54]
  PIN h_x_b[55]
    DIRECTION OUTPUT ;
    USE SIGNAL ;
    PORT
      LAYER M4 ;
        RECT  0 145.44 0.084 145.464 ;
    END
  END h_x_b[55]
  PIN h_x_b[56]
    DIRECTION OUTPUT ;
    USE SIGNAL ;
    PORT
      LAYER M4 ;
        RECT  0 145.824 0.084 145.848 ;
    END
  END h_x_b[56]
  PIN h_x_b[57]
    DIRECTION OUTPUT ;
    USE SIGNAL ;
    PORT
      LAYER M4 ;
        RECT  0 146.208 0.084 146.232 ;
    END
  END h_x_b[57]
  PIN h_x_b[58]
    DIRECTION OUTPUT ;
    USE SIGNAL ;
    PORT
      LAYER M4 ;
        RECT  0 146.592 0.084 146.616 ;
    END
  END h_x_b[58]
  PIN h_x_b[59]
    DIRECTION OUTPUT ;
    USE SIGNAL ;
    PORT
      LAYER M4 ;
        RECT  0 146.976 0.084 147 ;
    END
  END h_x_b[59]
  PIN h_x_b[5]
    DIRECTION OUTPUT ;
    USE SIGNAL ;
    PORT
      LAYER M4 ;
        RECT  0 126.24 0.084 126.264 ;
    END
  END h_x_b[5]
  PIN h_x_b[60]
    DIRECTION OUTPUT ;
    USE SIGNAL ;
    PORT
      LAYER M4 ;
        RECT  0 147.36 0.084 147.384 ;
    END
  END h_x_b[60]
  PIN h_x_b[61]
    DIRECTION OUTPUT ;
    USE SIGNAL ;
    PORT
      LAYER M4 ;
        RECT  0 147.744 0.084 147.768 ;
    END
  END h_x_b[61]
  PIN h_x_b[62]
    DIRECTION OUTPUT ;
    USE SIGNAL ;
    PORT
      LAYER M4 ;
        RECT  0 148.128 0.084 148.152 ;
    END
  END h_x_b[62]
  PIN h_x_b[63]
    DIRECTION OUTPUT ;
    USE SIGNAL ;
    PORT
      LAYER M4 ;
        RECT  0 148.512 0.084 148.536 ;
    END
  END h_x_b[63]
  PIN h_x_b[64]
    DIRECTION OUTPUT ;
    USE SIGNAL ;
    PORT
      LAYER M4 ;
        RECT  0 148.896 0.084 148.92 ;
    END
  END h_x_b[64]
  PIN h_x_b[65]
    DIRECTION OUTPUT ;
    USE SIGNAL ;
    PORT
      LAYER M4 ;
        RECT  0 149.28 0.084 149.304 ;
    END
  END h_x_b[65]
  PIN h_x_b[66]
    DIRECTION OUTPUT ;
    USE SIGNAL ;
    PORT
      LAYER M4 ;
        RECT  0 149.664 0.084 149.688 ;
    END
  END h_x_b[66]
  PIN h_x_b[67]
    DIRECTION OUTPUT ;
    USE SIGNAL ;
    PORT
      LAYER M4 ;
        RECT  0 150.048 0.084 150.072 ;
    END
  END h_x_b[67]
  PIN h_x_b[68]
    DIRECTION OUTPUT ;
    USE SIGNAL ;
    PORT
      LAYER M4 ;
        RECT  0 150.432 0.084 150.456 ;
    END
  END h_x_b[68]
  PIN h_x_b[69]
    DIRECTION OUTPUT ;
    USE SIGNAL ;
    PORT
      LAYER M4 ;
        RECT  0 150.816 0.084 150.84 ;
    END
  END h_x_b[69]
  PIN h_x_b[6]
    DIRECTION OUTPUT ;
    USE SIGNAL ;
    PORT
      LAYER M4 ;
        RECT  0 126.624 0.084 126.648 ;
    END
  END h_x_b[6]
  PIN h_x_b[70]
    DIRECTION OUTPUT ;
    USE SIGNAL ;
    PORT
      LAYER M4 ;
        RECT  0 151.2 0.084 151.224 ;
    END
  END h_x_b[70]
  PIN h_x_b[71]
    DIRECTION OUTPUT ;
    USE SIGNAL ;
    PORT
      LAYER M4 ;
        RECT  0 151.584 0.084 151.608 ;
    END
  END h_x_b[71]
  PIN h_x_b[72]
    DIRECTION OUTPUT ;
    USE SIGNAL ;
    PORT
      LAYER M4 ;
        RECT  0 151.968 0.084 151.992 ;
    END
  END h_x_b[72]
  PIN h_x_b[73]
    DIRECTION OUTPUT ;
    USE SIGNAL ;
    PORT
      LAYER M4 ;
        RECT  0 152.352 0.084 152.376 ;
    END
  END h_x_b[73]
  PIN h_x_b[74]
    DIRECTION OUTPUT ;
    USE SIGNAL ;
    PORT
      LAYER M4 ;
        RECT  0 152.736 0.084 152.76 ;
    END
  END h_x_b[74]
  PIN h_x_b[75]
    DIRECTION OUTPUT ;
    USE SIGNAL ;
    PORT
      LAYER M4 ;
        RECT  0 153.12 0.084 153.144 ;
    END
  END h_x_b[75]
  PIN h_x_b[76]
    DIRECTION OUTPUT ;
    USE SIGNAL ;
    PORT
      LAYER M4 ;
        RECT  0 153.504 0.084 153.528 ;
    END
  END h_x_b[76]
  PIN h_x_b[77]
    DIRECTION OUTPUT ;
    USE SIGNAL ;
    PORT
      LAYER M4 ;
        RECT  0 153.888 0.084 153.912 ;
    END
  END h_x_b[77]
  PIN h_x_b[78]
    DIRECTION OUTPUT ;
    USE SIGNAL ;
    PORT
      LAYER M4 ;
        RECT  0 154.272 0.084 154.296 ;
    END
  END h_x_b[78]
  PIN h_x_b[79]
    DIRECTION OUTPUT ;
    USE SIGNAL ;
    PORT
      LAYER M4 ;
        RECT  0 154.656 0.084 154.68 ;
    END
  END h_x_b[79]
  PIN h_x_b[7]
    DIRECTION OUTPUT ;
    USE SIGNAL ;
    PORT
      LAYER M4 ;
        RECT  0 127.008 0.084 127.032 ;
    END
  END h_x_b[7]
  PIN h_x_b[80]
    DIRECTION OUTPUT ;
    USE SIGNAL ;
    PORT
      LAYER M4 ;
        RECT  0 155.04 0.084 155.064 ;
    END
  END h_x_b[80]
  PIN h_x_b[81]
    DIRECTION OUTPUT ;
    USE SIGNAL ;
    PORT
      LAYER M4 ;
        RECT  0 155.424 0.084 155.448 ;
    END
  END h_x_b[81]
  PIN h_x_b[82]
    DIRECTION OUTPUT ;
    USE SIGNAL ;
    PORT
      LAYER M4 ;
        RECT  0 155.808 0.084 155.832 ;
    END
  END h_x_b[82]
  PIN h_x_b[83]
    DIRECTION OUTPUT ;
    USE SIGNAL ;
    PORT
      LAYER M4 ;
        RECT  0 156.192 0.084 156.216 ;
    END
  END h_x_b[83]
  PIN h_x_b[84]
    DIRECTION OUTPUT ;
    USE SIGNAL ;
    PORT
      LAYER M4 ;
        RECT  0 156.576 0.084 156.6 ;
    END
  END h_x_b[84]
  PIN h_x_b[85]
    DIRECTION OUTPUT ;
    USE SIGNAL ;
    PORT
      LAYER M4 ;
        RECT  0 156.96 0.084 156.984 ;
    END
  END h_x_b[85]
  PIN h_x_b[86]
    DIRECTION OUTPUT ;
    USE SIGNAL ;
    PORT
      LAYER M4 ;
        RECT  0 157.344 0.084 157.368 ;
    END
  END h_x_b[86]
  PIN h_x_b[87]
    DIRECTION OUTPUT ;
    USE SIGNAL ;
    PORT
      LAYER M4 ;
        RECT  0 157.728 0.084 157.752 ;
    END
  END h_x_b[87]
  PIN h_x_b[88]
    DIRECTION OUTPUT ;
    USE SIGNAL ;
    PORT
      LAYER M4 ;
        RECT  0 158.112 0.084 158.136 ;
    END
  END h_x_b[88]
  PIN h_x_b[89]
    DIRECTION OUTPUT ;
    USE SIGNAL ;
    PORT
      LAYER M4 ;
        RECT  0 158.496 0.084 158.52 ;
    END
  END h_x_b[89]
  PIN h_x_b[8]
    DIRECTION OUTPUT ;
    USE SIGNAL ;
    PORT
      LAYER M4 ;
        RECT  0 127.392 0.084 127.416 ;
    END
  END h_x_b[8]
  PIN h_x_b[90]
    DIRECTION OUTPUT ;
    USE SIGNAL ;
    PORT
      LAYER M4 ;
        RECT  0 158.88 0.084 158.904 ;
    END
  END h_x_b[90]
  PIN h_x_b[91]
    DIRECTION OUTPUT ;
    USE SIGNAL ;
    PORT
      LAYER M4 ;
        RECT  0 159.264 0.084 159.288 ;
    END
  END h_x_b[91]
  PIN h_x_b[92]
    DIRECTION OUTPUT ;
    USE SIGNAL ;
    PORT
      LAYER M4 ;
        RECT  0 159.648 0.084 159.672 ;
    END
  END h_x_b[92]
  PIN h_x_b[93]
    DIRECTION OUTPUT ;
    USE SIGNAL ;
    PORT
      LAYER M4 ;
        RECT  0 160.032 0.084 160.056 ;
    END
  END h_x_b[93]
  PIN h_x_b[94]
    DIRECTION OUTPUT ;
    USE SIGNAL ;
    PORT
      LAYER M4 ;
        RECT  0 160.416 0.084 160.44 ;
    END
  END h_x_b[94]
  PIN h_x_b[95]
    DIRECTION OUTPUT ;
    USE SIGNAL ;
    PORT
      LAYER M4 ;
        RECT  0 160.8 0.084 160.824 ;
    END
  END h_x_b[95]
  PIN h_x_b[96]
    DIRECTION OUTPUT ;
    USE SIGNAL ;
    PORT
      LAYER M4 ;
        RECT  0 161.184 0.084 161.208 ;
    END
  END h_x_b[96]
  PIN h_x_b[97]
    DIRECTION OUTPUT ;
    USE SIGNAL ;
    PORT
      LAYER M4 ;
        RECT  0 161.568 0.084 161.592 ;
    END
  END h_x_b[97]
  PIN h_x_b[98]
    DIRECTION OUTPUT ;
    USE SIGNAL ;
    PORT
      LAYER M4 ;
        RECT  0 161.952 0.084 161.976 ;
    END
  END h_x_b[98]
  PIN h_x_b[99]
    DIRECTION OUTPUT ;
    USE SIGNAL ;
    PORT
      LAYER M4 ;
        RECT  0 162.336 0.084 162.36 ;
    END
  END h_x_b[99]
  PIN h_x_b[9]
    DIRECTION OUTPUT ;
    USE SIGNAL ;
    PORT
      LAYER M4 ;
        RECT  0 127.776 0.084 127.8 ;
    END
  END h_x_b[9]
  PIN h_ze_a
    DIRECTION OUTPUT ;
    USE SIGNAL ;
    PORT
      LAYER M4 ;
        RECT  0 20.256 0.084 20.28 ;
    END
  END h_ze_a
  PIN h_ze_b
    DIRECTION OUTPUT ;
    USE SIGNAL ;
    PORT
      LAYER M4 ;
        RECT  0 123.936 0.084 123.96 ;
    END
  END h_ze_b
  PIN i1_bf
    DIRECTION INPUT ;
    USE SIGNAL ;
    PORT
      LAYER M4 ;
        RECT  208.164 63.36 208.248 63.384 ;
    END
  END i1_bf
  PIN i1_bk
    DIRECTION INPUT ;
    USE SIGNAL ;
    PORT
      LAYER M4 ;
        RECT  208.164 63.456 208.248 63.48 ;
    END
  END i1_bk
  PIN i1_t[0]
    DIRECTION INPUT ;
    USE SIGNAL ;
    PORT
      LAYER M4 ;
        RECT  208.164 63.552 208.248 63.576 ;
    END
  END i1_t[0]
  PIN i1_t[10]
    DIRECTION INPUT ;
    USE SIGNAL ;
    PORT
      LAYER M4 ;
        RECT  208.164 64.512 208.248 64.536 ;
    END
  END i1_t[10]
  PIN i1_t[11]
    DIRECTION INPUT ;
    USE SIGNAL ;
    PORT
      LAYER M4 ;
        RECT  208.164 64.608 208.248 64.632 ;
    END
  END i1_t[11]
  PIN i1_t[12]
    DIRECTION INPUT ;
    USE SIGNAL ;
    PORT
      LAYER M4 ;
        RECT  208.164 64.704 208.248 64.728 ;
    END
  END i1_t[12]
  PIN i1_t[13]
    DIRECTION INPUT ;
    USE SIGNAL ;
    PORT
      LAYER M4 ;
        RECT  208.164 64.8 208.248 64.824 ;
    END
  END i1_t[13]
  PIN i1_t[14]
    DIRECTION INPUT ;
    USE SIGNAL ;
    PORT
      LAYER M4 ;
        RECT  208.164 64.896 208.248 64.92 ;
    END
  END i1_t[14]
  PIN i1_t[15]
    DIRECTION INPUT ;
    USE SIGNAL ;
    PORT
      LAYER M4 ;
        RECT  208.164 64.992 208.248 65.016 ;
    END
  END i1_t[15]
  PIN i1_t[16]
    DIRECTION INPUT ;
    USE SIGNAL ;
    PORT
      LAYER M4 ;
        RECT  208.164 65.088 208.248 65.112 ;
    END
  END i1_t[16]
  PIN i1_t[1]
    DIRECTION INPUT ;
    USE SIGNAL ;
    PORT
      LAYER M4 ;
        RECT  208.164 63.648 208.248 63.672 ;
    END
  END i1_t[1]
  PIN i1_t[2]
    DIRECTION INPUT ;
    USE SIGNAL ;
    PORT
      LAYER M4 ;
        RECT  208.164 63.744 208.248 63.768 ;
    END
  END i1_t[2]
  PIN i1_t[3]
    DIRECTION INPUT ;
    USE SIGNAL ;
    PORT
      LAYER M4 ;
        RECT  208.164 63.84 208.248 63.864 ;
    END
  END i1_t[3]
  PIN i1_t[4]
    DIRECTION INPUT ;
    USE SIGNAL ;
    PORT
      LAYER M4 ;
        RECT  208.164 63.936 208.248 63.96 ;
    END
  END i1_t[4]
  PIN i1_t[5]
    DIRECTION INPUT ;
    USE SIGNAL ;
    PORT
      LAYER M4 ;
        RECT  208.164 64.032 208.248 64.056 ;
    END
  END i1_t[5]
  PIN i1_t[6]
    DIRECTION INPUT ;
    USE SIGNAL ;
    PORT
      LAYER M4 ;
        RECT  208.164 64.128 208.248 64.152 ;
    END
  END i1_t[6]
  PIN i1_t[7]
    DIRECTION INPUT ;
    USE SIGNAL ;
    PORT
      LAYER M4 ;
        RECT  208.164 64.224 208.248 64.248 ;
    END
  END i1_t[7]
  PIN i1_t[8]
    DIRECTION INPUT ;
    USE SIGNAL ;
    PORT
      LAYER M4 ;
        RECT  208.164 64.32 208.248 64.344 ;
    END
  END i1_t[8]
  PIN i1_t[9]
    DIRECTION INPUT ;
    USE SIGNAL ;
    PORT
      LAYER M4 ;
        RECT  208.164 64.416 208.248 64.44 ;
    END
  END i1_t[9]
  PIN i1_v
    DIRECTION INPUT ;
    USE SIGNAL ;
    PORT
      LAYER M4 ;
        RECT  208.164 65.184 208.248 65.208 ;
    END
  END i1_v
  PIN i2x_e0[0]
    DIRECTION INPUT ;
    USE SIGNAL ;
    PORT
      LAYER M4 ;
        RECT  208.164 65.28 208.248 65.304 ;
    END
  END i2x_e0[0]
  PIN i2x_e0[1]
    DIRECTION INPUT ;
    USE SIGNAL ;
    PORT
      LAYER M4 ;
        RECT  208.164 65.376 208.248 65.4 ;
    END
  END i2x_e0[1]
  PIN i2x_e0[2]
    DIRECTION INPUT ;
    USE SIGNAL ;
    PORT
      LAYER M4 ;
        RECT  208.164 65.472 208.248 65.496 ;
    END
  END i2x_e0[2]
  PIN i2x_e0[3]
    DIRECTION INPUT ;
    USE SIGNAL ;
    PORT
      LAYER M4 ;
        RECT  208.164 65.568 208.248 65.592 ;
    END
  END i2x_e0[3]
  PIN i2x_e0[4]
    DIRECTION INPUT ;
    USE SIGNAL ;
    PORT
      LAYER M4 ;
        RECT  208.164 65.664 208.248 65.688 ;
    END
  END i2x_e0[4]
  PIN i2x_e0[5]
    DIRECTION INPUT ;
    USE SIGNAL ;
    PORT
      LAYER M4 ;
        RECT  208.164 65.76 208.248 65.784 ;
    END
  END i2x_e0[5]
  PIN i2x_e0[6]
    DIRECTION INPUT ;
    USE SIGNAL ;
    PORT
      LAYER M4 ;
        RECT  208.164 65.856 208.248 65.88 ;
    END
  END i2x_e0[6]
  PIN i2x_e0[7]
    DIRECTION INPUT ;
    USE SIGNAL ;
    PORT
      LAYER M4 ;
        RECT  208.164 65.952 208.248 65.976 ;
    END
  END i2x_e0[7]
  PIN i2x_e0[8]
    DIRECTION INPUT ;
    USE SIGNAL ;
    PORT
      LAYER M4 ;
        RECT  208.164 66.048 208.248 66.072 ;
    END
  END i2x_e0[8]
  PIN i2x_e0[9]
    DIRECTION INPUT ;
    USE SIGNAL ;
    PORT
      LAYER M4 ;
        RECT  208.164 66.144 208.248 66.168 ;
    END
  END i2x_e0[9]
  PIN i2x_e1[0]
    DIRECTION INPUT ;
    USE SIGNAL ;
    PORT
      LAYER M4 ;
        RECT  208.164 66.24 208.248 66.264 ;
    END
  END i2x_e1[0]
  PIN i2x_e1[1]
    DIRECTION INPUT ;
    USE SIGNAL ;
    PORT
      LAYER M4 ;
        RECT  208.164 66.336 208.248 66.36 ;
    END
  END i2x_e1[1]
  PIN i2x_e1[2]
    DIRECTION INPUT ;
    USE SIGNAL ;
    PORT
      LAYER M4 ;
        RECT  208.164 66.432 208.248 66.456 ;
    END
  END i2x_e1[2]
  PIN i2x_e1[3]
    DIRECTION INPUT ;
    USE SIGNAL ;
    PORT
      LAYER M4 ;
        RECT  208.164 66.528 208.248 66.552 ;
    END
  END i2x_e1[3]
  PIN i2x_e1[4]
    DIRECTION INPUT ;
    USE SIGNAL ;
    PORT
      LAYER M4 ;
        RECT  208.164 66.624 208.248 66.648 ;
    END
  END i2x_e1[4]
  PIN i2x_e1[5]
    DIRECTION INPUT ;
    USE SIGNAL ;
    PORT
      LAYER M4 ;
        RECT  208.164 66.72 208.248 66.744 ;
    END
  END i2x_e1[5]
  PIN i2x_e1[6]
    DIRECTION INPUT ;
    USE SIGNAL ;
    PORT
      LAYER M4 ;
        RECT  208.164 66.816 208.248 66.84 ;
    END
  END i2x_e1[6]
  PIN i2x_e1[7]
    DIRECTION INPUT ;
    USE SIGNAL ;
    PORT
      LAYER M4 ;
        RECT  208.164 66.912 208.248 66.936 ;
    END
  END i2x_e1[7]
  PIN i2x_e1[8]
    DIRECTION INPUT ;
    USE SIGNAL ;
    PORT
      LAYER M4 ;
        RECT  208.164 67.008 208.248 67.032 ;
    END
  END i2x_e1[8]
  PIN i2x_e1[9]
    DIRECTION INPUT ;
    USE SIGNAL ;
    PORT
      LAYER M4 ;
        RECT  208.164 67.104 208.248 67.128 ;
    END
  END i2x_e1[9]
  PIN i2x_q0[0]
    DIRECTION INPUT ;
    USE SIGNAL ;
    PORT
      LAYER M4 ;
        RECT  208.164 67.2 208.248 67.224 ;
    END
  END i2x_q0[0]
  PIN i2x_q0[100]
    DIRECTION INPUT ;
    USE SIGNAL ;
    PORT
      LAYER M4 ;
        RECT  208.164 76.8 208.248 76.824 ;
    END
  END i2x_q0[100]
  PIN i2x_q0[101]
    DIRECTION INPUT ;
    USE SIGNAL ;
    PORT
      LAYER M4 ;
        RECT  208.164 76.896 208.248 76.92 ;
    END
  END i2x_q0[101]
  PIN i2x_q0[102]
    DIRECTION INPUT ;
    USE SIGNAL ;
    PORT
      LAYER M4 ;
        RECT  208.164 76.992 208.248 77.016 ;
    END
  END i2x_q0[102]
  PIN i2x_q0[103]
    DIRECTION INPUT ;
    USE SIGNAL ;
    PORT
      LAYER M4 ;
        RECT  208.164 77.088 208.248 77.112 ;
    END
  END i2x_q0[103]
  PIN i2x_q0[104]
    DIRECTION INPUT ;
    USE SIGNAL ;
    PORT
      LAYER M4 ;
        RECT  208.164 77.184 208.248 77.208 ;
    END
  END i2x_q0[104]
  PIN i2x_q0[105]
    DIRECTION INPUT ;
    USE SIGNAL ;
    PORT
      LAYER M4 ;
        RECT  208.164 77.28 208.248 77.304 ;
    END
  END i2x_q0[105]
  PIN i2x_q0[106]
    DIRECTION INPUT ;
    USE SIGNAL ;
    PORT
      LAYER M4 ;
        RECT  208.164 77.376 208.248 77.4 ;
    END
  END i2x_q0[106]
  PIN i2x_q0[107]
    DIRECTION INPUT ;
    USE SIGNAL ;
    PORT
      LAYER M4 ;
        RECT  208.164 77.472 208.248 77.496 ;
    END
  END i2x_q0[107]
  PIN i2x_q0[108]
    DIRECTION INPUT ;
    USE SIGNAL ;
    PORT
      LAYER M4 ;
        RECT  208.164 77.568 208.248 77.592 ;
    END
  END i2x_q0[108]
  PIN i2x_q0[109]
    DIRECTION INPUT ;
    USE SIGNAL ;
    PORT
      LAYER M4 ;
        RECT  208.164 77.664 208.248 77.688 ;
    END
  END i2x_q0[109]
  PIN i2x_q0[10]
    DIRECTION INPUT ;
    USE SIGNAL ;
    PORT
      LAYER M4 ;
        RECT  208.164 68.16 208.248 68.184 ;
    END
  END i2x_q0[10]
  PIN i2x_q0[110]
    DIRECTION INPUT ;
    USE SIGNAL ;
    PORT
      LAYER M4 ;
        RECT  208.164 77.76 208.248 77.784 ;
    END
  END i2x_q0[110]
  PIN i2x_q0[111]
    DIRECTION INPUT ;
    USE SIGNAL ;
    PORT
      LAYER M4 ;
        RECT  208.164 77.856 208.248 77.88 ;
    END
  END i2x_q0[111]
  PIN i2x_q0[112]
    DIRECTION INPUT ;
    USE SIGNAL ;
    PORT
      LAYER M4 ;
        RECT  208.164 77.952 208.248 77.976 ;
    END
  END i2x_q0[112]
  PIN i2x_q0[113]
    DIRECTION INPUT ;
    USE SIGNAL ;
    PORT
      LAYER M4 ;
        RECT  208.164 78.048 208.248 78.072 ;
    END
  END i2x_q0[113]
  PIN i2x_q0[114]
    DIRECTION INPUT ;
    USE SIGNAL ;
    PORT
      LAYER M4 ;
        RECT  208.164 78.144 208.248 78.168 ;
    END
  END i2x_q0[114]
  PIN i2x_q0[115]
    DIRECTION INPUT ;
    USE SIGNAL ;
    PORT
      LAYER M4 ;
        RECT  208.164 78.24 208.248 78.264 ;
    END
  END i2x_q0[115]
  PIN i2x_q0[116]
    DIRECTION INPUT ;
    USE SIGNAL ;
    PORT
      LAYER M4 ;
        RECT  208.164 78.336 208.248 78.36 ;
    END
  END i2x_q0[116]
  PIN i2x_q0[117]
    DIRECTION INPUT ;
    USE SIGNAL ;
    PORT
      LAYER M4 ;
        RECT  208.164 78.432 208.248 78.456 ;
    END
  END i2x_q0[117]
  PIN i2x_q0[118]
    DIRECTION INPUT ;
    USE SIGNAL ;
    PORT
      LAYER M4 ;
        RECT  208.164 78.528 208.248 78.552 ;
    END
  END i2x_q0[118]
  PIN i2x_q0[119]
    DIRECTION INPUT ;
    USE SIGNAL ;
    PORT
      LAYER M4 ;
        RECT  208.164 78.624 208.248 78.648 ;
    END
  END i2x_q0[119]
  PIN i2x_q0[11]
    DIRECTION INPUT ;
    USE SIGNAL ;
    PORT
      LAYER M4 ;
        RECT  208.164 68.256 208.248 68.28 ;
    END
  END i2x_q0[11]
  PIN i2x_q0[120]
    DIRECTION INPUT ;
    USE SIGNAL ;
    PORT
      LAYER M4 ;
        RECT  208.164 78.72 208.248 78.744 ;
    END
  END i2x_q0[120]
  PIN i2x_q0[121]
    DIRECTION INPUT ;
    USE SIGNAL ;
    PORT
      LAYER M4 ;
        RECT  208.164 78.816 208.248 78.84 ;
    END
  END i2x_q0[121]
  PIN i2x_q0[122]
    DIRECTION INPUT ;
    USE SIGNAL ;
    PORT
      LAYER M4 ;
        RECT  208.164 78.912 208.248 78.936 ;
    END
  END i2x_q0[122]
  PIN i2x_q0[123]
    DIRECTION INPUT ;
    USE SIGNAL ;
    PORT
      LAYER M4 ;
        RECT  208.164 79.008 208.248 79.032 ;
    END
  END i2x_q0[123]
  PIN i2x_q0[124]
    DIRECTION INPUT ;
    USE SIGNAL ;
    PORT
      LAYER M4 ;
        RECT  208.164 79.104 208.248 79.128 ;
    END
  END i2x_q0[124]
  PIN i2x_q0[125]
    DIRECTION INPUT ;
    USE SIGNAL ;
    PORT
      LAYER M4 ;
        RECT  208.164 79.2 208.248 79.224 ;
    END
  END i2x_q0[125]
  PIN i2x_q0[126]
    DIRECTION INPUT ;
    USE SIGNAL ;
    PORT
      LAYER M4 ;
        RECT  208.164 79.296 208.248 79.32 ;
    END
  END i2x_q0[126]
  PIN i2x_q0[127]
    DIRECTION INPUT ;
    USE SIGNAL ;
    PORT
      LAYER M4 ;
        RECT  208.164 79.392 208.248 79.416 ;
    END
  END i2x_q0[127]
  PIN i2x_q0[128]
    DIRECTION INPUT ;
    USE SIGNAL ;
    PORT
      LAYER M4 ;
        RECT  208.164 79.488 208.248 79.512 ;
    END
  END i2x_q0[128]
  PIN i2x_q0[129]
    DIRECTION INPUT ;
    USE SIGNAL ;
    PORT
      LAYER M4 ;
        RECT  208.164 79.584 208.248 79.608 ;
    END
  END i2x_q0[129]
  PIN i2x_q0[12]
    DIRECTION INPUT ;
    USE SIGNAL ;
    PORT
      LAYER M4 ;
        RECT  208.164 68.352 208.248 68.376 ;
    END
  END i2x_q0[12]
  PIN i2x_q0[130]
    DIRECTION INPUT ;
    USE SIGNAL ;
    PORT
      LAYER M4 ;
        RECT  208.164 79.68 208.248 79.704 ;
    END
  END i2x_q0[130]
  PIN i2x_q0[131]
    DIRECTION INPUT ;
    USE SIGNAL ;
    PORT
      LAYER M4 ;
        RECT  208.164 79.776 208.248 79.8 ;
    END
  END i2x_q0[131]
  PIN i2x_q0[132]
    DIRECTION INPUT ;
    USE SIGNAL ;
    PORT
      LAYER M4 ;
        RECT  208.164 79.872 208.248 79.896 ;
    END
  END i2x_q0[132]
  PIN i2x_q0[133]
    DIRECTION INPUT ;
    USE SIGNAL ;
    PORT
      LAYER M4 ;
        RECT  208.164 79.968 208.248 79.992 ;
    END
  END i2x_q0[133]
  PIN i2x_q0[134]
    DIRECTION INPUT ;
    USE SIGNAL ;
    PORT
      LAYER M4 ;
        RECT  208.164 80.064 208.248 80.088 ;
    END
  END i2x_q0[134]
  PIN i2x_q0[135]
    DIRECTION INPUT ;
    USE SIGNAL ;
    PORT
      LAYER M4 ;
        RECT  208.164 80.16 208.248 80.184 ;
    END
  END i2x_q0[135]
  PIN i2x_q0[136]
    DIRECTION INPUT ;
    USE SIGNAL ;
    PORT
      LAYER M4 ;
        RECT  208.164 80.256 208.248 80.28 ;
    END
  END i2x_q0[136]
  PIN i2x_q0[137]
    DIRECTION INPUT ;
    USE SIGNAL ;
    PORT
      LAYER M4 ;
        RECT  208.164 80.352 208.248 80.376 ;
    END
  END i2x_q0[137]
  PIN i2x_q0[138]
    DIRECTION INPUT ;
    USE SIGNAL ;
    PORT
      LAYER M4 ;
        RECT  208.164 80.448 208.248 80.472 ;
    END
  END i2x_q0[138]
  PIN i2x_q0[139]
    DIRECTION INPUT ;
    USE SIGNAL ;
    PORT
      LAYER M4 ;
        RECT  208.164 80.544 208.248 80.568 ;
    END
  END i2x_q0[139]
  PIN i2x_q0[13]
    DIRECTION INPUT ;
    USE SIGNAL ;
    PORT
      LAYER M4 ;
        RECT  208.164 68.448 208.248 68.472 ;
    END
  END i2x_q0[13]
  PIN i2x_q0[140]
    DIRECTION INPUT ;
    USE SIGNAL ;
    PORT
      LAYER M4 ;
        RECT  208.164 80.64 208.248 80.664 ;
    END
  END i2x_q0[140]
  PIN i2x_q0[141]
    DIRECTION INPUT ;
    USE SIGNAL ;
    PORT
      LAYER M4 ;
        RECT  208.164 80.736 208.248 80.76 ;
    END
  END i2x_q0[141]
  PIN i2x_q0[142]
    DIRECTION INPUT ;
    USE SIGNAL ;
    PORT
      LAYER M4 ;
        RECT  208.164 80.832 208.248 80.856 ;
    END
  END i2x_q0[142]
  PIN i2x_q0[143]
    DIRECTION INPUT ;
    USE SIGNAL ;
    PORT
      LAYER M4 ;
        RECT  208.164 80.928 208.248 80.952 ;
    END
  END i2x_q0[143]
  PIN i2x_q0[144]
    DIRECTION INPUT ;
    USE SIGNAL ;
    PORT
      LAYER M4 ;
        RECT  208.164 81.024 208.248 81.048 ;
    END
  END i2x_q0[144]
  PIN i2x_q0[145]
    DIRECTION INPUT ;
    USE SIGNAL ;
    PORT
      LAYER M4 ;
        RECT  208.164 81.12 208.248 81.144 ;
    END
  END i2x_q0[145]
  PIN i2x_q0[146]
    DIRECTION INPUT ;
    USE SIGNAL ;
    PORT
      LAYER M4 ;
        RECT  208.164 81.216 208.248 81.24 ;
    END
  END i2x_q0[146]
  PIN i2x_q0[147]
    DIRECTION INPUT ;
    USE SIGNAL ;
    PORT
      LAYER M4 ;
        RECT  208.164 81.312 208.248 81.336 ;
    END
  END i2x_q0[147]
  PIN i2x_q0[148]
    DIRECTION INPUT ;
    USE SIGNAL ;
    PORT
      LAYER M4 ;
        RECT  208.164 81.408 208.248 81.432 ;
    END
  END i2x_q0[148]
  PIN i2x_q0[149]
    DIRECTION INPUT ;
    USE SIGNAL ;
    PORT
      LAYER M4 ;
        RECT  208.164 81.504 208.248 81.528 ;
    END
  END i2x_q0[149]
  PIN i2x_q0[14]
    DIRECTION INPUT ;
    USE SIGNAL ;
    PORT
      LAYER M4 ;
        RECT  208.164 68.544 208.248 68.568 ;
    END
  END i2x_q0[14]
  PIN i2x_q0[150]
    DIRECTION INPUT ;
    USE SIGNAL ;
    PORT
      LAYER M4 ;
        RECT  208.164 81.6 208.248 81.624 ;
    END
  END i2x_q0[150]
  PIN i2x_q0[151]
    DIRECTION INPUT ;
    USE SIGNAL ;
    PORT
      LAYER M4 ;
        RECT  208.164 81.696 208.248 81.72 ;
    END
  END i2x_q0[151]
  PIN i2x_q0[152]
    DIRECTION INPUT ;
    USE SIGNAL ;
    PORT
      LAYER M4 ;
        RECT  208.164 81.792 208.248 81.816 ;
    END
  END i2x_q0[152]
  PIN i2x_q0[153]
    DIRECTION INPUT ;
    USE SIGNAL ;
    PORT
      LAYER M4 ;
        RECT  208.164 81.888 208.248 81.912 ;
    END
  END i2x_q0[153]
  PIN i2x_q0[154]
    DIRECTION INPUT ;
    USE SIGNAL ;
    PORT
      LAYER M4 ;
        RECT  208.164 81.984 208.248 82.008 ;
    END
  END i2x_q0[154]
  PIN i2x_q0[155]
    DIRECTION INPUT ;
    USE SIGNAL ;
    PORT
      LAYER M4 ;
        RECT  208.164 82.08 208.248 82.104 ;
    END
  END i2x_q0[155]
  PIN i2x_q0[156]
    DIRECTION INPUT ;
    USE SIGNAL ;
    PORT
      LAYER M4 ;
        RECT  208.164 82.176 208.248 82.2 ;
    END
  END i2x_q0[156]
  PIN i2x_q0[157]
    DIRECTION INPUT ;
    USE SIGNAL ;
    PORT
      LAYER M4 ;
        RECT  208.164 82.272 208.248 82.296 ;
    END
  END i2x_q0[157]
  PIN i2x_q0[158]
    DIRECTION INPUT ;
    USE SIGNAL ;
    PORT
      LAYER M4 ;
        RECT  208.164 82.368 208.248 82.392 ;
    END
  END i2x_q0[158]
  PIN i2x_q0[159]
    DIRECTION INPUT ;
    USE SIGNAL ;
    PORT
      LAYER M4 ;
        RECT  208.164 82.464 208.248 82.488 ;
    END
  END i2x_q0[159]
  PIN i2x_q0[15]
    DIRECTION INPUT ;
    USE SIGNAL ;
    PORT
      LAYER M4 ;
        RECT  208.164 68.64 208.248 68.664 ;
    END
  END i2x_q0[15]
  PIN i2x_q0[160]
    DIRECTION INPUT ;
    USE SIGNAL ;
    PORT
      LAYER M4 ;
        RECT  208.164 82.56 208.248 82.584 ;
    END
  END i2x_q0[160]
  PIN i2x_q0[161]
    DIRECTION INPUT ;
    USE SIGNAL ;
    PORT
      LAYER M4 ;
        RECT  208.164 82.656 208.248 82.68 ;
    END
  END i2x_q0[161]
  PIN i2x_q0[162]
    DIRECTION INPUT ;
    USE SIGNAL ;
    PORT
      LAYER M4 ;
        RECT  208.164 82.752 208.248 82.776 ;
    END
  END i2x_q0[162]
  PIN i2x_q0[163]
    DIRECTION INPUT ;
    USE SIGNAL ;
    PORT
      LAYER M4 ;
        RECT  208.164 82.848 208.248 82.872 ;
    END
  END i2x_q0[163]
  PIN i2x_q0[164]
    DIRECTION INPUT ;
    USE SIGNAL ;
    PORT
      LAYER M4 ;
        RECT  208.164 82.944 208.248 82.968 ;
    END
  END i2x_q0[164]
  PIN i2x_q0[165]
    DIRECTION INPUT ;
    USE SIGNAL ;
    PORT
      LAYER M4 ;
        RECT  208.164 83.04 208.248 83.064 ;
    END
  END i2x_q0[165]
  PIN i2x_q0[166]
    DIRECTION INPUT ;
    USE SIGNAL ;
    PORT
      LAYER M4 ;
        RECT  208.164 83.136 208.248 83.16 ;
    END
  END i2x_q0[166]
  PIN i2x_q0[167]
    DIRECTION INPUT ;
    USE SIGNAL ;
    PORT
      LAYER M4 ;
        RECT  208.164 83.232 208.248 83.256 ;
    END
  END i2x_q0[167]
  PIN i2x_q0[168]
    DIRECTION INPUT ;
    USE SIGNAL ;
    PORT
      LAYER M4 ;
        RECT  208.164 83.328 208.248 83.352 ;
    END
  END i2x_q0[168]
  PIN i2x_q0[169]
    DIRECTION INPUT ;
    USE SIGNAL ;
    PORT
      LAYER M4 ;
        RECT  208.164 83.424 208.248 83.448 ;
    END
  END i2x_q0[169]
  PIN i2x_q0[16]
    DIRECTION INPUT ;
    USE SIGNAL ;
    PORT
      LAYER M4 ;
        RECT  208.164 68.736 208.248 68.76 ;
    END
  END i2x_q0[16]
  PIN i2x_q0[170]
    DIRECTION INPUT ;
    USE SIGNAL ;
    PORT
      LAYER M4 ;
        RECT  208.164 83.52 208.248 83.544 ;
    END
  END i2x_q0[170]
  PIN i2x_q0[171]
    DIRECTION INPUT ;
    USE SIGNAL ;
    PORT
      LAYER M4 ;
        RECT  208.164 83.616 208.248 83.64 ;
    END
  END i2x_q0[171]
  PIN i2x_q0[172]
    DIRECTION INPUT ;
    USE SIGNAL ;
    PORT
      LAYER M4 ;
        RECT  208.164 83.712 208.248 83.736 ;
    END
  END i2x_q0[172]
  PIN i2x_q0[173]
    DIRECTION INPUT ;
    USE SIGNAL ;
    PORT
      LAYER M4 ;
        RECT  208.164 83.808 208.248 83.832 ;
    END
  END i2x_q0[173]
  PIN i2x_q0[174]
    DIRECTION INPUT ;
    USE SIGNAL ;
    PORT
      LAYER M4 ;
        RECT  208.164 83.904 208.248 83.928 ;
    END
  END i2x_q0[174]
  PIN i2x_q0[175]
    DIRECTION INPUT ;
    USE SIGNAL ;
    PORT
      LAYER M4 ;
        RECT  208.164 84 208.248 84.024 ;
    END
  END i2x_q0[175]
  PIN i2x_q0[176]
    DIRECTION INPUT ;
    USE SIGNAL ;
    PORT
      LAYER M4 ;
        RECT  208.164 84.096 208.248 84.12 ;
    END
  END i2x_q0[176]
  PIN i2x_q0[177]
    DIRECTION INPUT ;
    USE SIGNAL ;
    PORT
      LAYER M4 ;
        RECT  208.164 84.192 208.248 84.216 ;
    END
  END i2x_q0[177]
  PIN i2x_q0[178]
    DIRECTION INPUT ;
    USE SIGNAL ;
    PORT
      LAYER M4 ;
        RECT  208.164 84.288 208.248 84.312 ;
    END
  END i2x_q0[178]
  PIN i2x_q0[179]
    DIRECTION INPUT ;
    USE SIGNAL ;
    PORT
      LAYER M4 ;
        RECT  208.164 84.384 208.248 84.408 ;
    END
  END i2x_q0[179]
  PIN i2x_q0[17]
    DIRECTION INPUT ;
    USE SIGNAL ;
    PORT
      LAYER M4 ;
        RECT  208.164 68.832 208.248 68.856 ;
    END
  END i2x_q0[17]
  PIN i2x_q0[180]
    DIRECTION INPUT ;
    USE SIGNAL ;
    PORT
      LAYER M4 ;
        RECT  208.164 84.48 208.248 84.504 ;
    END
  END i2x_q0[180]
  PIN i2x_q0[181]
    DIRECTION INPUT ;
    USE SIGNAL ;
    PORT
      LAYER M4 ;
        RECT  208.164 84.576 208.248 84.6 ;
    END
  END i2x_q0[181]
  PIN i2x_q0[182]
    DIRECTION INPUT ;
    USE SIGNAL ;
    PORT
      LAYER M4 ;
        RECT  208.164 84.672 208.248 84.696 ;
    END
  END i2x_q0[182]
  PIN i2x_q0[183]
    DIRECTION INPUT ;
    USE SIGNAL ;
    PORT
      LAYER M4 ;
        RECT  208.164 84.768 208.248 84.792 ;
    END
  END i2x_q0[183]
  PIN i2x_q0[184]
    DIRECTION INPUT ;
    USE SIGNAL ;
    PORT
      LAYER M4 ;
        RECT  208.164 84.864 208.248 84.888 ;
    END
  END i2x_q0[184]
  PIN i2x_q0[185]
    DIRECTION INPUT ;
    USE SIGNAL ;
    PORT
      LAYER M4 ;
        RECT  208.164 84.96 208.248 84.984 ;
    END
  END i2x_q0[185]
  PIN i2x_q0[186]
    DIRECTION INPUT ;
    USE SIGNAL ;
    PORT
      LAYER M4 ;
        RECT  208.164 85.056 208.248 85.08 ;
    END
  END i2x_q0[186]
  PIN i2x_q0[187]
    DIRECTION INPUT ;
    USE SIGNAL ;
    PORT
      LAYER M4 ;
        RECT  208.164 85.152 208.248 85.176 ;
    END
  END i2x_q0[187]
  PIN i2x_q0[188]
    DIRECTION INPUT ;
    USE SIGNAL ;
    PORT
      LAYER M4 ;
        RECT  208.164 85.248 208.248 85.272 ;
    END
  END i2x_q0[188]
  PIN i2x_q0[189]
    DIRECTION INPUT ;
    USE SIGNAL ;
    PORT
      LAYER M4 ;
        RECT  208.164 85.344 208.248 85.368 ;
    END
  END i2x_q0[189]
  PIN i2x_q0[18]
    DIRECTION INPUT ;
    USE SIGNAL ;
    PORT
      LAYER M4 ;
        RECT  208.164 68.928 208.248 68.952 ;
    END
  END i2x_q0[18]
  PIN i2x_q0[190]
    DIRECTION INPUT ;
    USE SIGNAL ;
    PORT
      LAYER M4 ;
        RECT  208.164 85.44 208.248 85.464 ;
    END
  END i2x_q0[190]
  PIN i2x_q0[191]
    DIRECTION INPUT ;
    USE SIGNAL ;
    PORT
      LAYER M4 ;
        RECT  208.164 85.536 208.248 85.56 ;
    END
  END i2x_q0[191]
  PIN i2x_q0[192]
    DIRECTION INPUT ;
    USE SIGNAL ;
    PORT
      LAYER M4 ;
        RECT  208.164 85.632 208.248 85.656 ;
    END
  END i2x_q0[192]
  PIN i2x_q0[193]
    DIRECTION INPUT ;
    USE SIGNAL ;
    PORT
      LAYER M4 ;
        RECT  208.164 85.728 208.248 85.752 ;
    END
  END i2x_q0[193]
  PIN i2x_q0[194]
    DIRECTION INPUT ;
    USE SIGNAL ;
    PORT
      LAYER M4 ;
        RECT  208.164 85.824 208.248 85.848 ;
    END
  END i2x_q0[194]
  PIN i2x_q0[195]
    DIRECTION INPUT ;
    USE SIGNAL ;
    PORT
      LAYER M4 ;
        RECT  208.164 85.92 208.248 85.944 ;
    END
  END i2x_q0[195]
  PIN i2x_q0[196]
    DIRECTION INPUT ;
    USE SIGNAL ;
    PORT
      LAYER M4 ;
        RECT  208.164 86.016 208.248 86.04 ;
    END
  END i2x_q0[196]
  PIN i2x_q0[197]
    DIRECTION INPUT ;
    USE SIGNAL ;
    PORT
      LAYER M4 ;
        RECT  208.164 86.112 208.248 86.136 ;
    END
  END i2x_q0[197]
  PIN i2x_q0[198]
    DIRECTION INPUT ;
    USE SIGNAL ;
    PORT
      LAYER M4 ;
        RECT  208.164 86.208 208.248 86.232 ;
    END
  END i2x_q0[198]
  PIN i2x_q0[199]
    DIRECTION INPUT ;
    USE SIGNAL ;
    PORT
      LAYER M4 ;
        RECT  208.164 86.304 208.248 86.328 ;
    END
  END i2x_q0[199]
  PIN i2x_q0[19]
    DIRECTION INPUT ;
    USE SIGNAL ;
    PORT
      LAYER M4 ;
        RECT  208.164 69.024 208.248 69.048 ;
    END
  END i2x_q0[19]
  PIN i2x_q0[1]
    DIRECTION INPUT ;
    USE SIGNAL ;
    PORT
      LAYER M4 ;
        RECT  208.164 67.296 208.248 67.32 ;
    END
  END i2x_q0[1]
  PIN i2x_q0[200]
    DIRECTION INPUT ;
    USE SIGNAL ;
    PORT
      LAYER M4 ;
        RECT  208.164 86.4 208.248 86.424 ;
    END
  END i2x_q0[200]
  PIN i2x_q0[201]
    DIRECTION INPUT ;
    USE SIGNAL ;
    PORT
      LAYER M4 ;
        RECT  208.164 86.496 208.248 86.52 ;
    END
  END i2x_q0[201]
  PIN i2x_q0[202]
    DIRECTION INPUT ;
    USE SIGNAL ;
    PORT
      LAYER M4 ;
        RECT  208.164 86.592 208.248 86.616 ;
    END
  END i2x_q0[202]
  PIN i2x_q0[203]
    DIRECTION INPUT ;
    USE SIGNAL ;
    PORT
      LAYER M4 ;
        RECT  208.164 86.688 208.248 86.712 ;
    END
  END i2x_q0[203]
  PIN i2x_q0[204]
    DIRECTION INPUT ;
    USE SIGNAL ;
    PORT
      LAYER M4 ;
        RECT  208.164 86.784 208.248 86.808 ;
    END
  END i2x_q0[204]
  PIN i2x_q0[205]
    DIRECTION INPUT ;
    USE SIGNAL ;
    PORT
      LAYER M4 ;
        RECT  208.164 86.88 208.248 86.904 ;
    END
  END i2x_q0[205]
  PIN i2x_q0[206]
    DIRECTION INPUT ;
    USE SIGNAL ;
    PORT
      LAYER M4 ;
        RECT  208.164 86.976 208.248 87 ;
    END
  END i2x_q0[206]
  PIN i2x_q0[207]
    DIRECTION INPUT ;
    USE SIGNAL ;
    PORT
      LAYER M4 ;
        RECT  208.164 87.072 208.248 87.096 ;
    END
  END i2x_q0[207]
  PIN i2x_q0[208]
    DIRECTION INPUT ;
    USE SIGNAL ;
    PORT
      LAYER M4 ;
        RECT  208.164 87.168 208.248 87.192 ;
    END
  END i2x_q0[208]
  PIN i2x_q0[209]
    DIRECTION INPUT ;
    USE SIGNAL ;
    PORT
      LAYER M4 ;
        RECT  208.164 87.264 208.248 87.288 ;
    END
  END i2x_q0[209]
  PIN i2x_q0[20]
    DIRECTION INPUT ;
    USE SIGNAL ;
    PORT
      LAYER M4 ;
        RECT  208.164 69.12 208.248 69.144 ;
    END
  END i2x_q0[20]
  PIN i2x_q0[210]
    DIRECTION INPUT ;
    USE SIGNAL ;
    PORT
      LAYER M4 ;
        RECT  208.164 87.36 208.248 87.384 ;
    END
  END i2x_q0[210]
  PIN i2x_q0[211]
    DIRECTION INPUT ;
    USE SIGNAL ;
    PORT
      LAYER M4 ;
        RECT  208.164 87.456 208.248 87.48 ;
    END
  END i2x_q0[211]
  PIN i2x_q0[212]
    DIRECTION INPUT ;
    USE SIGNAL ;
    PORT
      LAYER M4 ;
        RECT  208.164 87.552 208.248 87.576 ;
    END
  END i2x_q0[212]
  PIN i2x_q0[213]
    DIRECTION INPUT ;
    USE SIGNAL ;
    PORT
      LAYER M4 ;
        RECT  208.164 87.648 208.248 87.672 ;
    END
  END i2x_q0[213]
  PIN i2x_q0[214]
    DIRECTION INPUT ;
    USE SIGNAL ;
    PORT
      LAYER M4 ;
        RECT  208.164 87.744 208.248 87.768 ;
    END
  END i2x_q0[214]
  PIN i2x_q0[215]
    DIRECTION INPUT ;
    USE SIGNAL ;
    PORT
      LAYER M4 ;
        RECT  208.164 87.84 208.248 87.864 ;
    END
  END i2x_q0[215]
  PIN i2x_q0[216]
    DIRECTION INPUT ;
    USE SIGNAL ;
    PORT
      LAYER M4 ;
        RECT  208.164 87.936 208.248 87.96 ;
    END
  END i2x_q0[216]
  PIN i2x_q0[217]
    DIRECTION INPUT ;
    USE SIGNAL ;
    PORT
      LAYER M4 ;
        RECT  208.164 88.032 208.248 88.056 ;
    END
  END i2x_q0[217]
  PIN i2x_q0[218]
    DIRECTION INPUT ;
    USE SIGNAL ;
    PORT
      LAYER M4 ;
        RECT  208.164 88.128 208.248 88.152 ;
    END
  END i2x_q0[218]
  PIN i2x_q0[219]
    DIRECTION INPUT ;
    USE SIGNAL ;
    PORT
      LAYER M4 ;
        RECT  208.164 88.224 208.248 88.248 ;
    END
  END i2x_q0[219]
  PIN i2x_q0[21]
    DIRECTION INPUT ;
    USE SIGNAL ;
    PORT
      LAYER M4 ;
        RECT  208.164 69.216 208.248 69.24 ;
    END
  END i2x_q0[21]
  PIN i2x_q0[220]
    DIRECTION INPUT ;
    USE SIGNAL ;
    PORT
      LAYER M4 ;
        RECT  208.164 88.32 208.248 88.344 ;
    END
  END i2x_q0[220]
  PIN i2x_q0[221]
    DIRECTION INPUT ;
    USE SIGNAL ;
    PORT
      LAYER M4 ;
        RECT  208.164 88.416 208.248 88.44 ;
    END
  END i2x_q0[221]
  PIN i2x_q0[222]
    DIRECTION INPUT ;
    USE SIGNAL ;
    PORT
      LAYER M4 ;
        RECT  208.164 88.512 208.248 88.536 ;
    END
  END i2x_q0[222]
  PIN i2x_q0[223]
    DIRECTION INPUT ;
    USE SIGNAL ;
    PORT
      LAYER M4 ;
        RECT  208.164 88.608 208.248 88.632 ;
    END
  END i2x_q0[223]
  PIN i2x_q0[224]
    DIRECTION INPUT ;
    USE SIGNAL ;
    PORT
      LAYER M4 ;
        RECT  208.164 88.704 208.248 88.728 ;
    END
  END i2x_q0[224]
  PIN i2x_q0[225]
    DIRECTION INPUT ;
    USE SIGNAL ;
    PORT
      LAYER M4 ;
        RECT  208.164 88.8 208.248 88.824 ;
    END
  END i2x_q0[225]
  PIN i2x_q0[226]
    DIRECTION INPUT ;
    USE SIGNAL ;
    PORT
      LAYER M4 ;
        RECT  208.164 88.896 208.248 88.92 ;
    END
  END i2x_q0[226]
  PIN i2x_q0[227]
    DIRECTION INPUT ;
    USE SIGNAL ;
    PORT
      LAYER M4 ;
        RECT  208.164 88.992 208.248 89.016 ;
    END
  END i2x_q0[227]
  PIN i2x_q0[228]
    DIRECTION INPUT ;
    USE SIGNAL ;
    PORT
      LAYER M4 ;
        RECT  208.164 89.088 208.248 89.112 ;
    END
  END i2x_q0[228]
  PIN i2x_q0[229]
    DIRECTION INPUT ;
    USE SIGNAL ;
    PORT
      LAYER M4 ;
        RECT  208.164 89.184 208.248 89.208 ;
    END
  END i2x_q0[229]
  PIN i2x_q0[22]
    DIRECTION INPUT ;
    USE SIGNAL ;
    PORT
      LAYER M4 ;
        RECT  208.164 69.312 208.248 69.336 ;
    END
  END i2x_q0[22]
  PIN i2x_q0[230]
    DIRECTION INPUT ;
    USE SIGNAL ;
    PORT
      LAYER M4 ;
        RECT  208.164 89.28 208.248 89.304 ;
    END
  END i2x_q0[230]
  PIN i2x_q0[231]
    DIRECTION INPUT ;
    USE SIGNAL ;
    PORT
      LAYER M4 ;
        RECT  208.164 89.376 208.248 89.4 ;
    END
  END i2x_q0[231]
  PIN i2x_q0[232]
    DIRECTION INPUT ;
    USE SIGNAL ;
    PORT
      LAYER M4 ;
        RECT  208.164 89.472 208.248 89.496 ;
    END
  END i2x_q0[232]
  PIN i2x_q0[233]
    DIRECTION INPUT ;
    USE SIGNAL ;
    PORT
      LAYER M4 ;
        RECT  208.164 89.568 208.248 89.592 ;
    END
  END i2x_q0[233]
  PIN i2x_q0[234]
    DIRECTION INPUT ;
    USE SIGNAL ;
    PORT
      LAYER M4 ;
        RECT  208.164 89.664 208.248 89.688 ;
    END
  END i2x_q0[234]
  PIN i2x_q0[235]
    DIRECTION INPUT ;
    USE SIGNAL ;
    PORT
      LAYER M4 ;
        RECT  208.164 89.76 208.248 89.784 ;
    END
  END i2x_q0[235]
  PIN i2x_q0[236]
    DIRECTION INPUT ;
    USE SIGNAL ;
    PORT
      LAYER M4 ;
        RECT  208.164 89.856 208.248 89.88 ;
    END
  END i2x_q0[236]
  PIN i2x_q0[237]
    DIRECTION INPUT ;
    USE SIGNAL ;
    PORT
      LAYER M4 ;
        RECT  208.164 89.952 208.248 89.976 ;
    END
  END i2x_q0[237]
  PIN i2x_q0[238]
    DIRECTION INPUT ;
    USE SIGNAL ;
    PORT
      LAYER M4 ;
        RECT  208.164 90.048 208.248 90.072 ;
    END
  END i2x_q0[238]
  PIN i2x_q0[239]
    DIRECTION INPUT ;
    USE SIGNAL ;
    PORT
      LAYER M4 ;
        RECT  208.164 90.144 208.248 90.168 ;
    END
  END i2x_q0[239]
  PIN i2x_q0[23]
    DIRECTION INPUT ;
    USE SIGNAL ;
    PORT
      LAYER M4 ;
        RECT  208.164 69.408 208.248 69.432 ;
    END
  END i2x_q0[23]
  PIN i2x_q0[240]
    DIRECTION INPUT ;
    USE SIGNAL ;
    PORT
      LAYER M4 ;
        RECT  208.164 90.24 208.248 90.264 ;
    END
  END i2x_q0[240]
  PIN i2x_q0[241]
    DIRECTION INPUT ;
    USE SIGNAL ;
    PORT
      LAYER M4 ;
        RECT  208.164 90.336 208.248 90.36 ;
    END
  END i2x_q0[241]
  PIN i2x_q0[242]
    DIRECTION INPUT ;
    USE SIGNAL ;
    PORT
      LAYER M4 ;
        RECT  208.164 90.432 208.248 90.456 ;
    END
  END i2x_q0[242]
  PIN i2x_q0[243]
    DIRECTION INPUT ;
    USE SIGNAL ;
    PORT
      LAYER M4 ;
        RECT  208.164 90.528 208.248 90.552 ;
    END
  END i2x_q0[243]
  PIN i2x_q0[244]
    DIRECTION INPUT ;
    USE SIGNAL ;
    PORT
      LAYER M4 ;
        RECT  208.164 90.624 208.248 90.648 ;
    END
  END i2x_q0[244]
  PIN i2x_q0[245]
    DIRECTION INPUT ;
    USE SIGNAL ;
    PORT
      LAYER M4 ;
        RECT  208.164 90.72 208.248 90.744 ;
    END
  END i2x_q0[245]
  PIN i2x_q0[246]
    DIRECTION INPUT ;
    USE SIGNAL ;
    PORT
      LAYER M4 ;
        RECT  208.164 90.816 208.248 90.84 ;
    END
  END i2x_q0[246]
  PIN i2x_q0[247]
    DIRECTION INPUT ;
    USE SIGNAL ;
    PORT
      LAYER M4 ;
        RECT  208.164 90.912 208.248 90.936 ;
    END
  END i2x_q0[247]
  PIN i2x_q0[248]
    DIRECTION INPUT ;
    USE SIGNAL ;
    PORT
      LAYER M4 ;
        RECT  208.164 91.008 208.248 91.032 ;
    END
  END i2x_q0[248]
  PIN i2x_q0[249]
    DIRECTION INPUT ;
    USE SIGNAL ;
    PORT
      LAYER M4 ;
        RECT  208.164 91.104 208.248 91.128 ;
    END
  END i2x_q0[249]
  PIN i2x_q0[24]
    DIRECTION INPUT ;
    USE SIGNAL ;
    PORT
      LAYER M4 ;
        RECT  208.164 69.504 208.248 69.528 ;
    END
  END i2x_q0[24]
  PIN i2x_q0[250]
    DIRECTION INPUT ;
    USE SIGNAL ;
    PORT
      LAYER M4 ;
        RECT  208.164 91.2 208.248 91.224 ;
    END
  END i2x_q0[250]
  PIN i2x_q0[251]
    DIRECTION INPUT ;
    USE SIGNAL ;
    PORT
      LAYER M4 ;
        RECT  208.164 91.296 208.248 91.32 ;
    END
  END i2x_q0[251]
  PIN i2x_q0[252]
    DIRECTION INPUT ;
    USE SIGNAL ;
    PORT
      LAYER M4 ;
        RECT  208.164 91.392 208.248 91.416 ;
    END
  END i2x_q0[252]
  PIN i2x_q0[253]
    DIRECTION INPUT ;
    USE SIGNAL ;
    PORT
      LAYER M4 ;
        RECT  208.164 91.488 208.248 91.512 ;
    END
  END i2x_q0[253]
  PIN i2x_q0[254]
    DIRECTION INPUT ;
    USE SIGNAL ;
    PORT
      LAYER M4 ;
        RECT  208.164 91.584 208.248 91.608 ;
    END
  END i2x_q0[254]
  PIN i2x_q0[255]
    DIRECTION INPUT ;
    USE SIGNAL ;
    PORT
      LAYER M4 ;
        RECT  208.164 91.68 208.248 91.704 ;
    END
  END i2x_q0[255]
  PIN i2x_q0[25]
    DIRECTION INPUT ;
    USE SIGNAL ;
    PORT
      LAYER M4 ;
        RECT  208.164 69.6 208.248 69.624 ;
    END
  END i2x_q0[25]
  PIN i2x_q0[26]
    DIRECTION INPUT ;
    USE SIGNAL ;
    PORT
      LAYER M4 ;
        RECT  208.164 69.696 208.248 69.72 ;
    END
  END i2x_q0[26]
  PIN i2x_q0[27]
    DIRECTION INPUT ;
    USE SIGNAL ;
    PORT
      LAYER M4 ;
        RECT  208.164 69.792 208.248 69.816 ;
    END
  END i2x_q0[27]
  PIN i2x_q0[28]
    DIRECTION INPUT ;
    USE SIGNAL ;
    PORT
      LAYER M4 ;
        RECT  208.164 69.888 208.248 69.912 ;
    END
  END i2x_q0[28]
  PIN i2x_q0[29]
    DIRECTION INPUT ;
    USE SIGNAL ;
    PORT
      LAYER M4 ;
        RECT  208.164 69.984 208.248 70.008 ;
    END
  END i2x_q0[29]
  PIN i2x_q0[2]
    DIRECTION INPUT ;
    USE SIGNAL ;
    PORT
      LAYER M4 ;
        RECT  208.164 67.392 208.248 67.416 ;
    END
  END i2x_q0[2]
  PIN i2x_q0[30]
    DIRECTION INPUT ;
    USE SIGNAL ;
    PORT
      LAYER M4 ;
        RECT  208.164 70.08 208.248 70.104 ;
    END
  END i2x_q0[30]
  PIN i2x_q0[31]
    DIRECTION INPUT ;
    USE SIGNAL ;
    PORT
      LAYER M4 ;
        RECT  208.164 70.176 208.248 70.2 ;
    END
  END i2x_q0[31]
  PIN i2x_q0[32]
    DIRECTION INPUT ;
    USE SIGNAL ;
    PORT
      LAYER M4 ;
        RECT  208.164 70.272 208.248 70.296 ;
    END
  END i2x_q0[32]
  PIN i2x_q0[33]
    DIRECTION INPUT ;
    USE SIGNAL ;
    PORT
      LAYER M4 ;
        RECT  208.164 70.368 208.248 70.392 ;
    END
  END i2x_q0[33]
  PIN i2x_q0[34]
    DIRECTION INPUT ;
    USE SIGNAL ;
    PORT
      LAYER M4 ;
        RECT  208.164 70.464 208.248 70.488 ;
    END
  END i2x_q0[34]
  PIN i2x_q0[35]
    DIRECTION INPUT ;
    USE SIGNAL ;
    PORT
      LAYER M4 ;
        RECT  208.164 70.56 208.248 70.584 ;
    END
  END i2x_q0[35]
  PIN i2x_q0[36]
    DIRECTION INPUT ;
    USE SIGNAL ;
    PORT
      LAYER M4 ;
        RECT  208.164 70.656 208.248 70.68 ;
    END
  END i2x_q0[36]
  PIN i2x_q0[37]
    DIRECTION INPUT ;
    USE SIGNAL ;
    PORT
      LAYER M4 ;
        RECT  208.164 70.752 208.248 70.776 ;
    END
  END i2x_q0[37]
  PIN i2x_q0[38]
    DIRECTION INPUT ;
    USE SIGNAL ;
    PORT
      LAYER M4 ;
        RECT  208.164 70.848 208.248 70.872 ;
    END
  END i2x_q0[38]
  PIN i2x_q0[39]
    DIRECTION INPUT ;
    USE SIGNAL ;
    PORT
      LAYER M4 ;
        RECT  208.164 70.944 208.248 70.968 ;
    END
  END i2x_q0[39]
  PIN i2x_q0[3]
    DIRECTION INPUT ;
    USE SIGNAL ;
    PORT
      LAYER M4 ;
        RECT  208.164 67.488 208.248 67.512 ;
    END
  END i2x_q0[3]
  PIN i2x_q0[40]
    DIRECTION INPUT ;
    USE SIGNAL ;
    PORT
      LAYER M4 ;
        RECT  208.164 71.04 208.248 71.064 ;
    END
  END i2x_q0[40]
  PIN i2x_q0[41]
    DIRECTION INPUT ;
    USE SIGNAL ;
    PORT
      LAYER M4 ;
        RECT  208.164 71.136 208.248 71.16 ;
    END
  END i2x_q0[41]
  PIN i2x_q0[42]
    DIRECTION INPUT ;
    USE SIGNAL ;
    PORT
      LAYER M4 ;
        RECT  208.164 71.232 208.248 71.256 ;
    END
  END i2x_q0[42]
  PIN i2x_q0[43]
    DIRECTION INPUT ;
    USE SIGNAL ;
    PORT
      LAYER M4 ;
        RECT  208.164 71.328 208.248 71.352 ;
    END
  END i2x_q0[43]
  PIN i2x_q0[44]
    DIRECTION INPUT ;
    USE SIGNAL ;
    PORT
      LAYER M4 ;
        RECT  208.164 71.424 208.248 71.448 ;
    END
  END i2x_q0[44]
  PIN i2x_q0[45]
    DIRECTION INPUT ;
    USE SIGNAL ;
    PORT
      LAYER M4 ;
        RECT  208.164 71.52 208.248 71.544 ;
    END
  END i2x_q0[45]
  PIN i2x_q0[46]
    DIRECTION INPUT ;
    USE SIGNAL ;
    PORT
      LAYER M4 ;
        RECT  208.164 71.616 208.248 71.64 ;
    END
  END i2x_q0[46]
  PIN i2x_q0[47]
    DIRECTION INPUT ;
    USE SIGNAL ;
    PORT
      LAYER M4 ;
        RECT  208.164 71.712 208.248 71.736 ;
    END
  END i2x_q0[47]
  PIN i2x_q0[48]
    DIRECTION INPUT ;
    USE SIGNAL ;
    PORT
      LAYER M4 ;
        RECT  208.164 71.808 208.248 71.832 ;
    END
  END i2x_q0[48]
  PIN i2x_q0[49]
    DIRECTION INPUT ;
    USE SIGNAL ;
    PORT
      LAYER M4 ;
        RECT  208.164 71.904 208.248 71.928 ;
    END
  END i2x_q0[49]
  PIN i2x_q0[4]
    DIRECTION INPUT ;
    USE SIGNAL ;
    PORT
      LAYER M4 ;
        RECT  208.164 67.584 208.248 67.608 ;
    END
  END i2x_q0[4]
  PIN i2x_q0[50]
    DIRECTION INPUT ;
    USE SIGNAL ;
    PORT
      LAYER M4 ;
        RECT  208.164 72 208.248 72.024 ;
    END
  END i2x_q0[50]
  PIN i2x_q0[51]
    DIRECTION INPUT ;
    USE SIGNAL ;
    PORT
      LAYER M4 ;
        RECT  208.164 72.096 208.248 72.12 ;
    END
  END i2x_q0[51]
  PIN i2x_q0[52]
    DIRECTION INPUT ;
    USE SIGNAL ;
    PORT
      LAYER M4 ;
        RECT  208.164 72.192 208.248 72.216 ;
    END
  END i2x_q0[52]
  PIN i2x_q0[53]
    DIRECTION INPUT ;
    USE SIGNAL ;
    PORT
      LAYER M4 ;
        RECT  208.164 72.288 208.248 72.312 ;
    END
  END i2x_q0[53]
  PIN i2x_q0[54]
    DIRECTION INPUT ;
    USE SIGNAL ;
    PORT
      LAYER M4 ;
        RECT  208.164 72.384 208.248 72.408 ;
    END
  END i2x_q0[54]
  PIN i2x_q0[55]
    DIRECTION INPUT ;
    USE SIGNAL ;
    PORT
      LAYER M4 ;
        RECT  208.164 72.48 208.248 72.504 ;
    END
  END i2x_q0[55]
  PIN i2x_q0[56]
    DIRECTION INPUT ;
    USE SIGNAL ;
    PORT
      LAYER M4 ;
        RECT  208.164 72.576 208.248 72.6 ;
    END
  END i2x_q0[56]
  PIN i2x_q0[57]
    DIRECTION INPUT ;
    USE SIGNAL ;
    PORT
      LAYER M4 ;
        RECT  208.164 72.672 208.248 72.696 ;
    END
  END i2x_q0[57]
  PIN i2x_q0[58]
    DIRECTION INPUT ;
    USE SIGNAL ;
    PORT
      LAYER M4 ;
        RECT  208.164 72.768 208.248 72.792 ;
    END
  END i2x_q0[58]
  PIN i2x_q0[59]
    DIRECTION INPUT ;
    USE SIGNAL ;
    PORT
      LAYER M4 ;
        RECT  208.164 72.864 208.248 72.888 ;
    END
  END i2x_q0[59]
  PIN i2x_q0[5]
    DIRECTION INPUT ;
    USE SIGNAL ;
    PORT
      LAYER M4 ;
        RECT  208.164 67.68 208.248 67.704 ;
    END
  END i2x_q0[5]
  PIN i2x_q0[60]
    DIRECTION INPUT ;
    USE SIGNAL ;
    PORT
      LAYER M4 ;
        RECT  208.164 72.96 208.248 72.984 ;
    END
  END i2x_q0[60]
  PIN i2x_q0[61]
    DIRECTION INPUT ;
    USE SIGNAL ;
    PORT
      LAYER M4 ;
        RECT  208.164 73.056 208.248 73.08 ;
    END
  END i2x_q0[61]
  PIN i2x_q0[62]
    DIRECTION INPUT ;
    USE SIGNAL ;
    PORT
      LAYER M4 ;
        RECT  208.164 73.152 208.248 73.176 ;
    END
  END i2x_q0[62]
  PIN i2x_q0[63]
    DIRECTION INPUT ;
    USE SIGNAL ;
    PORT
      LAYER M4 ;
        RECT  208.164 73.248 208.248 73.272 ;
    END
  END i2x_q0[63]
  PIN i2x_q0[64]
    DIRECTION INPUT ;
    USE SIGNAL ;
    PORT
      LAYER M4 ;
        RECT  208.164 73.344 208.248 73.368 ;
    END
  END i2x_q0[64]
  PIN i2x_q0[65]
    DIRECTION INPUT ;
    USE SIGNAL ;
    PORT
      LAYER M4 ;
        RECT  208.164 73.44 208.248 73.464 ;
    END
  END i2x_q0[65]
  PIN i2x_q0[66]
    DIRECTION INPUT ;
    USE SIGNAL ;
    PORT
      LAYER M4 ;
        RECT  208.164 73.536 208.248 73.56 ;
    END
  END i2x_q0[66]
  PIN i2x_q0[67]
    DIRECTION INPUT ;
    USE SIGNAL ;
    PORT
      LAYER M4 ;
        RECT  208.164 73.632 208.248 73.656 ;
    END
  END i2x_q0[67]
  PIN i2x_q0[68]
    DIRECTION INPUT ;
    USE SIGNAL ;
    PORT
      LAYER M4 ;
        RECT  208.164 73.728 208.248 73.752 ;
    END
  END i2x_q0[68]
  PIN i2x_q0[69]
    DIRECTION INPUT ;
    USE SIGNAL ;
    PORT
      LAYER M4 ;
        RECT  208.164 73.824 208.248 73.848 ;
    END
  END i2x_q0[69]
  PIN i2x_q0[6]
    DIRECTION INPUT ;
    USE SIGNAL ;
    PORT
      LAYER M4 ;
        RECT  208.164 67.776 208.248 67.8 ;
    END
  END i2x_q0[6]
  PIN i2x_q0[70]
    DIRECTION INPUT ;
    USE SIGNAL ;
    PORT
      LAYER M4 ;
        RECT  208.164 73.92 208.248 73.944 ;
    END
  END i2x_q0[70]
  PIN i2x_q0[71]
    DIRECTION INPUT ;
    USE SIGNAL ;
    PORT
      LAYER M4 ;
        RECT  208.164 74.016 208.248 74.04 ;
    END
  END i2x_q0[71]
  PIN i2x_q0[72]
    DIRECTION INPUT ;
    USE SIGNAL ;
    PORT
      LAYER M4 ;
        RECT  208.164 74.112 208.248 74.136 ;
    END
  END i2x_q0[72]
  PIN i2x_q0[73]
    DIRECTION INPUT ;
    USE SIGNAL ;
    PORT
      LAYER M4 ;
        RECT  208.164 74.208 208.248 74.232 ;
    END
  END i2x_q0[73]
  PIN i2x_q0[74]
    DIRECTION INPUT ;
    USE SIGNAL ;
    PORT
      LAYER M4 ;
        RECT  208.164 74.304 208.248 74.328 ;
    END
  END i2x_q0[74]
  PIN i2x_q0[75]
    DIRECTION INPUT ;
    USE SIGNAL ;
    PORT
      LAYER M4 ;
        RECT  208.164 74.4 208.248 74.424 ;
    END
  END i2x_q0[75]
  PIN i2x_q0[76]
    DIRECTION INPUT ;
    USE SIGNAL ;
    PORT
      LAYER M4 ;
        RECT  208.164 74.496 208.248 74.52 ;
    END
  END i2x_q0[76]
  PIN i2x_q0[77]
    DIRECTION INPUT ;
    USE SIGNAL ;
    PORT
      LAYER M4 ;
        RECT  208.164 74.592 208.248 74.616 ;
    END
  END i2x_q0[77]
  PIN i2x_q0[78]
    DIRECTION INPUT ;
    USE SIGNAL ;
    PORT
      LAYER M4 ;
        RECT  208.164 74.688 208.248 74.712 ;
    END
  END i2x_q0[78]
  PIN i2x_q0[79]
    DIRECTION INPUT ;
    USE SIGNAL ;
    PORT
      LAYER M4 ;
        RECT  208.164 74.784 208.248 74.808 ;
    END
  END i2x_q0[79]
  PIN i2x_q0[7]
    DIRECTION INPUT ;
    USE SIGNAL ;
    PORT
      LAYER M4 ;
        RECT  208.164 67.872 208.248 67.896 ;
    END
  END i2x_q0[7]
  PIN i2x_q0[80]
    DIRECTION INPUT ;
    USE SIGNAL ;
    PORT
      LAYER M4 ;
        RECT  208.164 74.88 208.248 74.904 ;
    END
  END i2x_q0[80]
  PIN i2x_q0[81]
    DIRECTION INPUT ;
    USE SIGNAL ;
    PORT
      LAYER M4 ;
        RECT  208.164 74.976 208.248 75 ;
    END
  END i2x_q0[81]
  PIN i2x_q0[82]
    DIRECTION INPUT ;
    USE SIGNAL ;
    PORT
      LAYER M4 ;
        RECT  208.164 75.072 208.248 75.096 ;
    END
  END i2x_q0[82]
  PIN i2x_q0[83]
    DIRECTION INPUT ;
    USE SIGNAL ;
    PORT
      LAYER M4 ;
        RECT  208.164 75.168 208.248 75.192 ;
    END
  END i2x_q0[83]
  PIN i2x_q0[84]
    DIRECTION INPUT ;
    USE SIGNAL ;
    PORT
      LAYER M4 ;
        RECT  208.164 75.264 208.248 75.288 ;
    END
  END i2x_q0[84]
  PIN i2x_q0[85]
    DIRECTION INPUT ;
    USE SIGNAL ;
    PORT
      LAYER M4 ;
        RECT  208.164 75.36 208.248 75.384 ;
    END
  END i2x_q0[85]
  PIN i2x_q0[86]
    DIRECTION INPUT ;
    USE SIGNAL ;
    PORT
      LAYER M4 ;
        RECT  208.164 75.456 208.248 75.48 ;
    END
  END i2x_q0[86]
  PIN i2x_q0[87]
    DIRECTION INPUT ;
    USE SIGNAL ;
    PORT
      LAYER M4 ;
        RECT  208.164 75.552 208.248 75.576 ;
    END
  END i2x_q0[87]
  PIN i2x_q0[88]
    DIRECTION INPUT ;
    USE SIGNAL ;
    PORT
      LAYER M4 ;
        RECT  208.164 75.648 208.248 75.672 ;
    END
  END i2x_q0[88]
  PIN i2x_q0[89]
    DIRECTION INPUT ;
    USE SIGNAL ;
    PORT
      LAYER M4 ;
        RECT  208.164 75.744 208.248 75.768 ;
    END
  END i2x_q0[89]
  PIN i2x_q0[8]
    DIRECTION INPUT ;
    USE SIGNAL ;
    PORT
      LAYER M4 ;
        RECT  208.164 67.968 208.248 67.992 ;
    END
  END i2x_q0[8]
  PIN i2x_q0[90]
    DIRECTION INPUT ;
    USE SIGNAL ;
    PORT
      LAYER M4 ;
        RECT  208.164 75.84 208.248 75.864 ;
    END
  END i2x_q0[90]
  PIN i2x_q0[91]
    DIRECTION INPUT ;
    USE SIGNAL ;
    PORT
      LAYER M4 ;
        RECT  208.164 75.936 208.248 75.96 ;
    END
  END i2x_q0[91]
  PIN i2x_q0[92]
    DIRECTION INPUT ;
    USE SIGNAL ;
    PORT
      LAYER M4 ;
        RECT  208.164 76.032 208.248 76.056 ;
    END
  END i2x_q0[92]
  PIN i2x_q0[93]
    DIRECTION INPUT ;
    USE SIGNAL ;
    PORT
      LAYER M4 ;
        RECT  208.164 76.128 208.248 76.152 ;
    END
  END i2x_q0[93]
  PIN i2x_q0[94]
    DIRECTION INPUT ;
    USE SIGNAL ;
    PORT
      LAYER M4 ;
        RECT  208.164 76.224 208.248 76.248 ;
    END
  END i2x_q0[94]
  PIN i2x_q0[95]
    DIRECTION INPUT ;
    USE SIGNAL ;
    PORT
      LAYER M4 ;
        RECT  208.164 76.32 208.248 76.344 ;
    END
  END i2x_q0[95]
  PIN i2x_q0[96]
    DIRECTION INPUT ;
    USE SIGNAL ;
    PORT
      LAYER M4 ;
        RECT  208.164 76.416 208.248 76.44 ;
    END
  END i2x_q0[96]
  PIN i2x_q0[97]
    DIRECTION INPUT ;
    USE SIGNAL ;
    PORT
      LAYER M4 ;
        RECT  208.164 76.512 208.248 76.536 ;
    END
  END i2x_q0[97]
  PIN i2x_q0[98]
    DIRECTION INPUT ;
    USE SIGNAL ;
    PORT
      LAYER M4 ;
        RECT  208.164 76.608 208.248 76.632 ;
    END
  END i2x_q0[98]
  PIN i2x_q0[99]
    DIRECTION INPUT ;
    USE SIGNAL ;
    PORT
      LAYER M4 ;
        RECT  208.164 76.704 208.248 76.728 ;
    END
  END i2x_q0[99]
  PIN i2x_q0[9]
    DIRECTION INPUT ;
    USE SIGNAL ;
    PORT
      LAYER M4 ;
        RECT  208.164 68.064 208.248 68.088 ;
    END
  END i2x_q0[9]
  PIN i2x_q1[0]
    DIRECTION INPUT ;
    USE SIGNAL ;
    PORT
      LAYER M4 ;
        RECT  208.164 91.776 208.248 91.8 ;
    END
  END i2x_q1[0]
  PIN i2x_q1[100]
    DIRECTION INPUT ;
    USE SIGNAL ;
    PORT
      LAYER M4 ;
        RECT  208.164 101.376 208.248 101.4 ;
    END
  END i2x_q1[100]
  PIN i2x_q1[101]
    DIRECTION INPUT ;
    USE SIGNAL ;
    PORT
      LAYER M4 ;
        RECT  208.164 101.472 208.248 101.496 ;
    END
  END i2x_q1[101]
  PIN i2x_q1[102]
    DIRECTION INPUT ;
    USE SIGNAL ;
    PORT
      LAYER M4 ;
        RECT  208.164 101.568 208.248 101.592 ;
    END
  END i2x_q1[102]
  PIN i2x_q1[103]
    DIRECTION INPUT ;
    USE SIGNAL ;
    PORT
      LAYER M4 ;
        RECT  208.164 101.664 208.248 101.688 ;
    END
  END i2x_q1[103]
  PIN i2x_q1[104]
    DIRECTION INPUT ;
    USE SIGNAL ;
    PORT
      LAYER M4 ;
        RECT  208.164 101.76 208.248 101.784 ;
    END
  END i2x_q1[104]
  PIN i2x_q1[105]
    DIRECTION INPUT ;
    USE SIGNAL ;
    PORT
      LAYER M4 ;
        RECT  208.164 101.856 208.248 101.88 ;
    END
  END i2x_q1[105]
  PIN i2x_q1[106]
    DIRECTION INPUT ;
    USE SIGNAL ;
    PORT
      LAYER M4 ;
        RECT  208.164 101.952 208.248 101.976 ;
    END
  END i2x_q1[106]
  PIN i2x_q1[107]
    DIRECTION INPUT ;
    USE SIGNAL ;
    PORT
      LAYER M4 ;
        RECT  208.164 102.048 208.248 102.072 ;
    END
  END i2x_q1[107]
  PIN i2x_q1[108]
    DIRECTION INPUT ;
    USE SIGNAL ;
    PORT
      LAYER M4 ;
        RECT  208.164 102.144 208.248 102.168 ;
    END
  END i2x_q1[108]
  PIN i2x_q1[109]
    DIRECTION INPUT ;
    USE SIGNAL ;
    PORT
      LAYER M4 ;
        RECT  208.164 102.24 208.248 102.264 ;
    END
  END i2x_q1[109]
  PIN i2x_q1[10]
    DIRECTION INPUT ;
    USE SIGNAL ;
    PORT
      LAYER M4 ;
        RECT  208.164 92.736 208.248 92.76 ;
    END
  END i2x_q1[10]
  PIN i2x_q1[110]
    DIRECTION INPUT ;
    USE SIGNAL ;
    PORT
      LAYER M4 ;
        RECT  208.164 102.336 208.248 102.36 ;
    END
  END i2x_q1[110]
  PIN i2x_q1[111]
    DIRECTION INPUT ;
    USE SIGNAL ;
    PORT
      LAYER M4 ;
        RECT  208.164 102.432 208.248 102.456 ;
    END
  END i2x_q1[111]
  PIN i2x_q1[112]
    DIRECTION INPUT ;
    USE SIGNAL ;
    PORT
      LAYER M4 ;
        RECT  208.164 102.528 208.248 102.552 ;
    END
  END i2x_q1[112]
  PIN i2x_q1[113]
    DIRECTION INPUT ;
    USE SIGNAL ;
    PORT
      LAYER M4 ;
        RECT  208.164 102.624 208.248 102.648 ;
    END
  END i2x_q1[113]
  PIN i2x_q1[114]
    DIRECTION INPUT ;
    USE SIGNAL ;
    PORT
      LAYER M4 ;
        RECT  208.164 102.72 208.248 102.744 ;
    END
  END i2x_q1[114]
  PIN i2x_q1[115]
    DIRECTION INPUT ;
    USE SIGNAL ;
    PORT
      LAYER M4 ;
        RECT  208.164 102.816 208.248 102.84 ;
    END
  END i2x_q1[115]
  PIN i2x_q1[116]
    DIRECTION INPUT ;
    USE SIGNAL ;
    PORT
      LAYER M4 ;
        RECT  208.164 102.912 208.248 102.936 ;
    END
  END i2x_q1[116]
  PIN i2x_q1[117]
    DIRECTION INPUT ;
    USE SIGNAL ;
    PORT
      LAYER M4 ;
        RECT  208.164 103.008 208.248 103.032 ;
    END
  END i2x_q1[117]
  PIN i2x_q1[118]
    DIRECTION INPUT ;
    USE SIGNAL ;
    PORT
      LAYER M4 ;
        RECT  208.164 103.104 208.248 103.128 ;
    END
  END i2x_q1[118]
  PIN i2x_q1[119]
    DIRECTION INPUT ;
    USE SIGNAL ;
    PORT
      LAYER M4 ;
        RECT  208.164 103.2 208.248 103.224 ;
    END
  END i2x_q1[119]
  PIN i2x_q1[11]
    DIRECTION INPUT ;
    USE SIGNAL ;
    PORT
      LAYER M4 ;
        RECT  208.164 92.832 208.248 92.856 ;
    END
  END i2x_q1[11]
  PIN i2x_q1[120]
    DIRECTION INPUT ;
    USE SIGNAL ;
    PORT
      LAYER M4 ;
        RECT  208.164 103.296 208.248 103.32 ;
    END
  END i2x_q1[120]
  PIN i2x_q1[121]
    DIRECTION INPUT ;
    USE SIGNAL ;
    PORT
      LAYER M4 ;
        RECT  208.164 103.392 208.248 103.416 ;
    END
  END i2x_q1[121]
  PIN i2x_q1[122]
    DIRECTION INPUT ;
    USE SIGNAL ;
    PORT
      LAYER M4 ;
        RECT  208.164 103.488 208.248 103.512 ;
    END
  END i2x_q1[122]
  PIN i2x_q1[123]
    DIRECTION INPUT ;
    USE SIGNAL ;
    PORT
      LAYER M4 ;
        RECT  208.164 103.584 208.248 103.608 ;
    END
  END i2x_q1[123]
  PIN i2x_q1[124]
    DIRECTION INPUT ;
    USE SIGNAL ;
    PORT
      LAYER M4 ;
        RECT  208.164 103.68 208.248 103.704 ;
    END
  END i2x_q1[124]
  PIN i2x_q1[125]
    DIRECTION INPUT ;
    USE SIGNAL ;
    PORT
      LAYER M4 ;
        RECT  208.164 103.776 208.248 103.8 ;
    END
  END i2x_q1[125]
  PIN i2x_q1[126]
    DIRECTION INPUT ;
    USE SIGNAL ;
    PORT
      LAYER M4 ;
        RECT  208.164 103.872 208.248 103.896 ;
    END
  END i2x_q1[126]
  PIN i2x_q1[127]
    DIRECTION INPUT ;
    USE SIGNAL ;
    PORT
      LAYER M4 ;
        RECT  208.164 103.968 208.248 103.992 ;
    END
  END i2x_q1[127]
  PIN i2x_q1[128]
    DIRECTION INPUT ;
    USE SIGNAL ;
    PORT
      LAYER M4 ;
        RECT  208.164 104.064 208.248 104.088 ;
    END
  END i2x_q1[128]
  PIN i2x_q1[129]
    DIRECTION INPUT ;
    USE SIGNAL ;
    PORT
      LAYER M4 ;
        RECT  208.164 104.16 208.248 104.184 ;
    END
  END i2x_q1[129]
  PIN i2x_q1[12]
    DIRECTION INPUT ;
    USE SIGNAL ;
    PORT
      LAYER M4 ;
        RECT  208.164 92.928 208.248 92.952 ;
    END
  END i2x_q1[12]
  PIN i2x_q1[130]
    DIRECTION INPUT ;
    USE SIGNAL ;
    PORT
      LAYER M4 ;
        RECT  208.164 104.256 208.248 104.28 ;
    END
  END i2x_q1[130]
  PIN i2x_q1[131]
    DIRECTION INPUT ;
    USE SIGNAL ;
    PORT
      LAYER M4 ;
        RECT  208.164 104.352 208.248 104.376 ;
    END
  END i2x_q1[131]
  PIN i2x_q1[132]
    DIRECTION INPUT ;
    USE SIGNAL ;
    PORT
      LAYER M4 ;
        RECT  208.164 104.448 208.248 104.472 ;
    END
  END i2x_q1[132]
  PIN i2x_q1[133]
    DIRECTION INPUT ;
    USE SIGNAL ;
    PORT
      LAYER M4 ;
        RECT  208.164 104.544 208.248 104.568 ;
    END
  END i2x_q1[133]
  PIN i2x_q1[134]
    DIRECTION INPUT ;
    USE SIGNAL ;
    PORT
      LAYER M4 ;
        RECT  208.164 104.64 208.248 104.664 ;
    END
  END i2x_q1[134]
  PIN i2x_q1[135]
    DIRECTION INPUT ;
    USE SIGNAL ;
    PORT
      LAYER M4 ;
        RECT  208.164 104.736 208.248 104.76 ;
    END
  END i2x_q1[135]
  PIN i2x_q1[136]
    DIRECTION INPUT ;
    USE SIGNAL ;
    PORT
      LAYER M4 ;
        RECT  208.164 104.832 208.248 104.856 ;
    END
  END i2x_q1[136]
  PIN i2x_q1[137]
    DIRECTION INPUT ;
    USE SIGNAL ;
    PORT
      LAYER M4 ;
        RECT  208.164 104.928 208.248 104.952 ;
    END
  END i2x_q1[137]
  PIN i2x_q1[138]
    DIRECTION INPUT ;
    USE SIGNAL ;
    PORT
      LAYER M4 ;
        RECT  208.164 105.024 208.248 105.048 ;
    END
  END i2x_q1[138]
  PIN i2x_q1[139]
    DIRECTION INPUT ;
    USE SIGNAL ;
    PORT
      LAYER M4 ;
        RECT  208.164 105.12 208.248 105.144 ;
    END
  END i2x_q1[139]
  PIN i2x_q1[13]
    DIRECTION INPUT ;
    USE SIGNAL ;
    PORT
      LAYER M4 ;
        RECT  208.164 93.024 208.248 93.048 ;
    END
  END i2x_q1[13]
  PIN i2x_q1[140]
    DIRECTION INPUT ;
    USE SIGNAL ;
    PORT
      LAYER M4 ;
        RECT  208.164 105.216 208.248 105.24 ;
    END
  END i2x_q1[140]
  PIN i2x_q1[141]
    DIRECTION INPUT ;
    USE SIGNAL ;
    PORT
      LAYER M4 ;
        RECT  208.164 105.312 208.248 105.336 ;
    END
  END i2x_q1[141]
  PIN i2x_q1[142]
    DIRECTION INPUT ;
    USE SIGNAL ;
    PORT
      LAYER M4 ;
        RECT  208.164 105.408 208.248 105.432 ;
    END
  END i2x_q1[142]
  PIN i2x_q1[143]
    DIRECTION INPUT ;
    USE SIGNAL ;
    PORT
      LAYER M4 ;
        RECT  208.164 105.504 208.248 105.528 ;
    END
  END i2x_q1[143]
  PIN i2x_q1[144]
    DIRECTION INPUT ;
    USE SIGNAL ;
    PORT
      LAYER M4 ;
        RECT  208.164 105.6 208.248 105.624 ;
    END
  END i2x_q1[144]
  PIN i2x_q1[145]
    DIRECTION INPUT ;
    USE SIGNAL ;
    PORT
      LAYER M4 ;
        RECT  208.164 105.696 208.248 105.72 ;
    END
  END i2x_q1[145]
  PIN i2x_q1[146]
    DIRECTION INPUT ;
    USE SIGNAL ;
    PORT
      LAYER M4 ;
        RECT  208.164 105.792 208.248 105.816 ;
    END
  END i2x_q1[146]
  PIN i2x_q1[147]
    DIRECTION INPUT ;
    USE SIGNAL ;
    PORT
      LAYER M4 ;
        RECT  208.164 105.888 208.248 105.912 ;
    END
  END i2x_q1[147]
  PIN i2x_q1[148]
    DIRECTION INPUT ;
    USE SIGNAL ;
    PORT
      LAYER M4 ;
        RECT  208.164 105.984 208.248 106.008 ;
    END
  END i2x_q1[148]
  PIN i2x_q1[149]
    DIRECTION INPUT ;
    USE SIGNAL ;
    PORT
      LAYER M4 ;
        RECT  208.164 106.08 208.248 106.104 ;
    END
  END i2x_q1[149]
  PIN i2x_q1[14]
    DIRECTION INPUT ;
    USE SIGNAL ;
    PORT
      LAYER M4 ;
        RECT  208.164 93.12 208.248 93.144 ;
    END
  END i2x_q1[14]
  PIN i2x_q1[150]
    DIRECTION INPUT ;
    USE SIGNAL ;
    PORT
      LAYER M4 ;
        RECT  208.164 106.176 208.248 106.2 ;
    END
  END i2x_q1[150]
  PIN i2x_q1[151]
    DIRECTION INPUT ;
    USE SIGNAL ;
    PORT
      LAYER M4 ;
        RECT  208.164 106.272 208.248 106.296 ;
    END
  END i2x_q1[151]
  PIN i2x_q1[152]
    DIRECTION INPUT ;
    USE SIGNAL ;
    PORT
      LAYER M4 ;
        RECT  208.164 106.368 208.248 106.392 ;
    END
  END i2x_q1[152]
  PIN i2x_q1[153]
    DIRECTION INPUT ;
    USE SIGNAL ;
    PORT
      LAYER M4 ;
        RECT  208.164 106.464 208.248 106.488 ;
    END
  END i2x_q1[153]
  PIN i2x_q1[154]
    DIRECTION INPUT ;
    USE SIGNAL ;
    PORT
      LAYER M4 ;
        RECT  208.164 106.56 208.248 106.584 ;
    END
  END i2x_q1[154]
  PIN i2x_q1[155]
    DIRECTION INPUT ;
    USE SIGNAL ;
    PORT
      LAYER M4 ;
        RECT  208.164 106.656 208.248 106.68 ;
    END
  END i2x_q1[155]
  PIN i2x_q1[156]
    DIRECTION INPUT ;
    USE SIGNAL ;
    PORT
      LAYER M4 ;
        RECT  208.164 106.752 208.248 106.776 ;
    END
  END i2x_q1[156]
  PIN i2x_q1[157]
    DIRECTION INPUT ;
    USE SIGNAL ;
    PORT
      LAYER M4 ;
        RECT  208.164 106.848 208.248 106.872 ;
    END
  END i2x_q1[157]
  PIN i2x_q1[158]
    DIRECTION INPUT ;
    USE SIGNAL ;
    PORT
      LAYER M4 ;
        RECT  208.164 106.944 208.248 106.968 ;
    END
  END i2x_q1[158]
  PIN i2x_q1[159]
    DIRECTION INPUT ;
    USE SIGNAL ;
    PORT
      LAYER M4 ;
        RECT  208.164 107.04 208.248 107.064 ;
    END
  END i2x_q1[159]
  PIN i2x_q1[15]
    DIRECTION INPUT ;
    USE SIGNAL ;
    PORT
      LAYER M4 ;
        RECT  208.164 93.216 208.248 93.24 ;
    END
  END i2x_q1[15]
  PIN i2x_q1[160]
    DIRECTION INPUT ;
    USE SIGNAL ;
    PORT
      LAYER M4 ;
        RECT  208.164 107.136 208.248 107.16 ;
    END
  END i2x_q1[160]
  PIN i2x_q1[161]
    DIRECTION INPUT ;
    USE SIGNAL ;
    PORT
      LAYER M4 ;
        RECT  208.164 107.232 208.248 107.256 ;
    END
  END i2x_q1[161]
  PIN i2x_q1[162]
    DIRECTION INPUT ;
    USE SIGNAL ;
    PORT
      LAYER M4 ;
        RECT  208.164 107.328 208.248 107.352 ;
    END
  END i2x_q1[162]
  PIN i2x_q1[163]
    DIRECTION INPUT ;
    USE SIGNAL ;
    PORT
      LAYER M4 ;
        RECT  208.164 107.424 208.248 107.448 ;
    END
  END i2x_q1[163]
  PIN i2x_q1[164]
    DIRECTION INPUT ;
    USE SIGNAL ;
    PORT
      LAYER M4 ;
        RECT  208.164 107.52 208.248 107.544 ;
    END
  END i2x_q1[164]
  PIN i2x_q1[165]
    DIRECTION INPUT ;
    USE SIGNAL ;
    PORT
      LAYER M4 ;
        RECT  208.164 107.616 208.248 107.64 ;
    END
  END i2x_q1[165]
  PIN i2x_q1[166]
    DIRECTION INPUT ;
    USE SIGNAL ;
    PORT
      LAYER M4 ;
        RECT  208.164 107.712 208.248 107.736 ;
    END
  END i2x_q1[166]
  PIN i2x_q1[167]
    DIRECTION INPUT ;
    USE SIGNAL ;
    PORT
      LAYER M4 ;
        RECT  208.164 107.808 208.248 107.832 ;
    END
  END i2x_q1[167]
  PIN i2x_q1[168]
    DIRECTION INPUT ;
    USE SIGNAL ;
    PORT
      LAYER M4 ;
        RECT  208.164 107.904 208.248 107.928 ;
    END
  END i2x_q1[168]
  PIN i2x_q1[169]
    DIRECTION INPUT ;
    USE SIGNAL ;
    PORT
      LAYER M4 ;
        RECT  208.164 108 208.248 108.024 ;
    END
  END i2x_q1[169]
  PIN i2x_q1[16]
    DIRECTION INPUT ;
    USE SIGNAL ;
    PORT
      LAYER M4 ;
        RECT  208.164 93.312 208.248 93.336 ;
    END
  END i2x_q1[16]
  PIN i2x_q1[170]
    DIRECTION INPUT ;
    USE SIGNAL ;
    PORT
      LAYER M4 ;
        RECT  208.164 108.096 208.248 108.12 ;
    END
  END i2x_q1[170]
  PIN i2x_q1[171]
    DIRECTION INPUT ;
    USE SIGNAL ;
    PORT
      LAYER M4 ;
        RECT  208.164 108.192 208.248 108.216 ;
    END
  END i2x_q1[171]
  PIN i2x_q1[172]
    DIRECTION INPUT ;
    USE SIGNAL ;
    PORT
      LAYER M4 ;
        RECT  208.164 108.288 208.248 108.312 ;
    END
  END i2x_q1[172]
  PIN i2x_q1[173]
    DIRECTION INPUT ;
    USE SIGNAL ;
    PORT
      LAYER M4 ;
        RECT  208.164 108.384 208.248 108.408 ;
    END
  END i2x_q1[173]
  PIN i2x_q1[174]
    DIRECTION INPUT ;
    USE SIGNAL ;
    PORT
      LAYER M4 ;
        RECT  208.164 108.48 208.248 108.504 ;
    END
  END i2x_q1[174]
  PIN i2x_q1[175]
    DIRECTION INPUT ;
    USE SIGNAL ;
    PORT
      LAYER M4 ;
        RECT  208.164 108.576 208.248 108.6 ;
    END
  END i2x_q1[175]
  PIN i2x_q1[176]
    DIRECTION INPUT ;
    USE SIGNAL ;
    PORT
      LAYER M4 ;
        RECT  208.164 108.672 208.248 108.696 ;
    END
  END i2x_q1[176]
  PIN i2x_q1[177]
    DIRECTION INPUT ;
    USE SIGNAL ;
    PORT
      LAYER M4 ;
        RECT  208.164 108.768 208.248 108.792 ;
    END
  END i2x_q1[177]
  PIN i2x_q1[178]
    DIRECTION INPUT ;
    USE SIGNAL ;
    PORT
      LAYER M4 ;
        RECT  208.164 108.864 208.248 108.888 ;
    END
  END i2x_q1[178]
  PIN i2x_q1[179]
    DIRECTION INPUT ;
    USE SIGNAL ;
    PORT
      LAYER M4 ;
        RECT  208.164 108.96 208.248 108.984 ;
    END
  END i2x_q1[179]
  PIN i2x_q1[17]
    DIRECTION INPUT ;
    USE SIGNAL ;
    PORT
      LAYER M4 ;
        RECT  208.164 93.408 208.248 93.432 ;
    END
  END i2x_q1[17]
  PIN i2x_q1[180]
    DIRECTION INPUT ;
    USE SIGNAL ;
    PORT
      LAYER M4 ;
        RECT  208.164 109.056 208.248 109.08 ;
    END
  END i2x_q1[180]
  PIN i2x_q1[181]
    DIRECTION INPUT ;
    USE SIGNAL ;
    PORT
      LAYER M4 ;
        RECT  208.164 109.152 208.248 109.176 ;
    END
  END i2x_q1[181]
  PIN i2x_q1[182]
    DIRECTION INPUT ;
    USE SIGNAL ;
    PORT
      LAYER M4 ;
        RECT  208.164 109.248 208.248 109.272 ;
    END
  END i2x_q1[182]
  PIN i2x_q1[183]
    DIRECTION INPUT ;
    USE SIGNAL ;
    PORT
      LAYER M4 ;
        RECT  208.164 109.344 208.248 109.368 ;
    END
  END i2x_q1[183]
  PIN i2x_q1[184]
    DIRECTION INPUT ;
    USE SIGNAL ;
    PORT
      LAYER M4 ;
        RECT  208.164 109.44 208.248 109.464 ;
    END
  END i2x_q1[184]
  PIN i2x_q1[185]
    DIRECTION INPUT ;
    USE SIGNAL ;
    PORT
      LAYER M4 ;
        RECT  208.164 109.536 208.248 109.56 ;
    END
  END i2x_q1[185]
  PIN i2x_q1[186]
    DIRECTION INPUT ;
    USE SIGNAL ;
    PORT
      LAYER M4 ;
        RECT  208.164 109.632 208.248 109.656 ;
    END
  END i2x_q1[186]
  PIN i2x_q1[187]
    DIRECTION INPUT ;
    USE SIGNAL ;
    PORT
      LAYER M4 ;
        RECT  208.164 109.728 208.248 109.752 ;
    END
  END i2x_q1[187]
  PIN i2x_q1[188]
    DIRECTION INPUT ;
    USE SIGNAL ;
    PORT
      LAYER M4 ;
        RECT  208.164 109.824 208.248 109.848 ;
    END
  END i2x_q1[188]
  PIN i2x_q1[189]
    DIRECTION INPUT ;
    USE SIGNAL ;
    PORT
      LAYER M4 ;
        RECT  208.164 109.92 208.248 109.944 ;
    END
  END i2x_q1[189]
  PIN i2x_q1[18]
    DIRECTION INPUT ;
    USE SIGNAL ;
    PORT
      LAYER M4 ;
        RECT  208.164 93.504 208.248 93.528 ;
    END
  END i2x_q1[18]
  PIN i2x_q1[190]
    DIRECTION INPUT ;
    USE SIGNAL ;
    PORT
      LAYER M4 ;
        RECT  208.164 110.016 208.248 110.04 ;
    END
  END i2x_q1[190]
  PIN i2x_q1[191]
    DIRECTION INPUT ;
    USE SIGNAL ;
    PORT
      LAYER M4 ;
        RECT  208.164 110.112 208.248 110.136 ;
    END
  END i2x_q1[191]
  PIN i2x_q1[192]
    DIRECTION INPUT ;
    USE SIGNAL ;
    PORT
      LAYER M4 ;
        RECT  208.164 110.208 208.248 110.232 ;
    END
  END i2x_q1[192]
  PIN i2x_q1[193]
    DIRECTION INPUT ;
    USE SIGNAL ;
    PORT
      LAYER M4 ;
        RECT  208.164 110.304 208.248 110.328 ;
    END
  END i2x_q1[193]
  PIN i2x_q1[194]
    DIRECTION INPUT ;
    USE SIGNAL ;
    PORT
      LAYER M4 ;
        RECT  208.164 110.4 208.248 110.424 ;
    END
  END i2x_q1[194]
  PIN i2x_q1[195]
    DIRECTION INPUT ;
    USE SIGNAL ;
    PORT
      LAYER M4 ;
        RECT  208.164 110.496 208.248 110.52 ;
    END
  END i2x_q1[195]
  PIN i2x_q1[196]
    DIRECTION INPUT ;
    USE SIGNAL ;
    PORT
      LAYER M4 ;
        RECT  208.164 110.592 208.248 110.616 ;
    END
  END i2x_q1[196]
  PIN i2x_q1[197]
    DIRECTION INPUT ;
    USE SIGNAL ;
    PORT
      LAYER M4 ;
        RECT  208.164 110.688 208.248 110.712 ;
    END
  END i2x_q1[197]
  PIN i2x_q1[198]
    DIRECTION INPUT ;
    USE SIGNAL ;
    PORT
      LAYER M4 ;
        RECT  208.164 110.784 208.248 110.808 ;
    END
  END i2x_q1[198]
  PIN i2x_q1[199]
    DIRECTION INPUT ;
    USE SIGNAL ;
    PORT
      LAYER M4 ;
        RECT  208.164 110.88 208.248 110.904 ;
    END
  END i2x_q1[199]
  PIN i2x_q1[19]
    DIRECTION INPUT ;
    USE SIGNAL ;
    PORT
      LAYER M4 ;
        RECT  208.164 93.6 208.248 93.624 ;
    END
  END i2x_q1[19]
  PIN i2x_q1[1]
    DIRECTION INPUT ;
    USE SIGNAL ;
    PORT
      LAYER M4 ;
        RECT  208.164 91.872 208.248 91.896 ;
    END
  END i2x_q1[1]
  PIN i2x_q1[200]
    DIRECTION INPUT ;
    USE SIGNAL ;
    PORT
      LAYER M4 ;
        RECT  208.164 110.976 208.248 111 ;
    END
  END i2x_q1[200]
  PIN i2x_q1[201]
    DIRECTION INPUT ;
    USE SIGNAL ;
    PORT
      LAYER M4 ;
        RECT  208.164 111.072 208.248 111.096 ;
    END
  END i2x_q1[201]
  PIN i2x_q1[202]
    DIRECTION INPUT ;
    USE SIGNAL ;
    PORT
      LAYER M4 ;
        RECT  208.164 111.168 208.248 111.192 ;
    END
  END i2x_q1[202]
  PIN i2x_q1[203]
    DIRECTION INPUT ;
    USE SIGNAL ;
    PORT
      LAYER M4 ;
        RECT  208.164 111.264 208.248 111.288 ;
    END
  END i2x_q1[203]
  PIN i2x_q1[204]
    DIRECTION INPUT ;
    USE SIGNAL ;
    PORT
      LAYER M4 ;
        RECT  208.164 111.36 208.248 111.384 ;
    END
  END i2x_q1[204]
  PIN i2x_q1[205]
    DIRECTION INPUT ;
    USE SIGNAL ;
    PORT
      LAYER M4 ;
        RECT  208.164 111.456 208.248 111.48 ;
    END
  END i2x_q1[205]
  PIN i2x_q1[206]
    DIRECTION INPUT ;
    USE SIGNAL ;
    PORT
      LAYER M4 ;
        RECT  208.164 111.552 208.248 111.576 ;
    END
  END i2x_q1[206]
  PIN i2x_q1[207]
    DIRECTION INPUT ;
    USE SIGNAL ;
    PORT
      LAYER M4 ;
        RECT  208.164 111.648 208.248 111.672 ;
    END
  END i2x_q1[207]
  PIN i2x_q1[208]
    DIRECTION INPUT ;
    USE SIGNAL ;
    PORT
      LAYER M4 ;
        RECT  208.164 111.744 208.248 111.768 ;
    END
  END i2x_q1[208]
  PIN i2x_q1[209]
    DIRECTION INPUT ;
    USE SIGNAL ;
    PORT
      LAYER M4 ;
        RECT  208.164 111.84 208.248 111.864 ;
    END
  END i2x_q1[209]
  PIN i2x_q1[20]
    DIRECTION INPUT ;
    USE SIGNAL ;
    PORT
      LAYER M4 ;
        RECT  208.164 93.696 208.248 93.72 ;
    END
  END i2x_q1[20]
  PIN i2x_q1[210]
    DIRECTION INPUT ;
    USE SIGNAL ;
    PORT
      LAYER M4 ;
        RECT  208.164 111.936 208.248 111.96 ;
    END
  END i2x_q1[210]
  PIN i2x_q1[211]
    DIRECTION INPUT ;
    USE SIGNAL ;
    PORT
      LAYER M4 ;
        RECT  208.164 112.032 208.248 112.056 ;
    END
  END i2x_q1[211]
  PIN i2x_q1[212]
    DIRECTION INPUT ;
    USE SIGNAL ;
    PORT
      LAYER M4 ;
        RECT  208.164 112.128 208.248 112.152 ;
    END
  END i2x_q1[212]
  PIN i2x_q1[213]
    DIRECTION INPUT ;
    USE SIGNAL ;
    PORT
      LAYER M4 ;
        RECT  208.164 112.224 208.248 112.248 ;
    END
  END i2x_q1[213]
  PIN i2x_q1[214]
    DIRECTION INPUT ;
    USE SIGNAL ;
    PORT
      LAYER M4 ;
        RECT  208.164 112.32 208.248 112.344 ;
    END
  END i2x_q1[214]
  PIN i2x_q1[215]
    DIRECTION INPUT ;
    USE SIGNAL ;
    PORT
      LAYER M4 ;
        RECT  208.164 112.416 208.248 112.44 ;
    END
  END i2x_q1[215]
  PIN i2x_q1[216]
    DIRECTION INPUT ;
    USE SIGNAL ;
    PORT
      LAYER M4 ;
        RECT  208.164 112.512 208.248 112.536 ;
    END
  END i2x_q1[216]
  PIN i2x_q1[217]
    DIRECTION INPUT ;
    USE SIGNAL ;
    PORT
      LAYER M4 ;
        RECT  208.164 112.608 208.248 112.632 ;
    END
  END i2x_q1[217]
  PIN i2x_q1[218]
    DIRECTION INPUT ;
    USE SIGNAL ;
    PORT
      LAYER M4 ;
        RECT  208.164 112.704 208.248 112.728 ;
    END
  END i2x_q1[218]
  PIN i2x_q1[219]
    DIRECTION INPUT ;
    USE SIGNAL ;
    PORT
      LAYER M4 ;
        RECT  208.164 112.8 208.248 112.824 ;
    END
  END i2x_q1[219]
  PIN i2x_q1[21]
    DIRECTION INPUT ;
    USE SIGNAL ;
    PORT
      LAYER M4 ;
        RECT  208.164 93.792 208.248 93.816 ;
    END
  END i2x_q1[21]
  PIN i2x_q1[220]
    DIRECTION INPUT ;
    USE SIGNAL ;
    PORT
      LAYER M4 ;
        RECT  208.164 112.896 208.248 112.92 ;
    END
  END i2x_q1[220]
  PIN i2x_q1[221]
    DIRECTION INPUT ;
    USE SIGNAL ;
    PORT
      LAYER M4 ;
        RECT  208.164 112.992 208.248 113.016 ;
    END
  END i2x_q1[221]
  PIN i2x_q1[222]
    DIRECTION INPUT ;
    USE SIGNAL ;
    PORT
      LAYER M4 ;
        RECT  208.164 113.088 208.248 113.112 ;
    END
  END i2x_q1[222]
  PIN i2x_q1[223]
    DIRECTION INPUT ;
    USE SIGNAL ;
    PORT
      LAYER M4 ;
        RECT  208.164 113.184 208.248 113.208 ;
    END
  END i2x_q1[223]
  PIN i2x_q1[224]
    DIRECTION INPUT ;
    USE SIGNAL ;
    PORT
      LAYER M4 ;
        RECT  208.164 113.28 208.248 113.304 ;
    END
  END i2x_q1[224]
  PIN i2x_q1[225]
    DIRECTION INPUT ;
    USE SIGNAL ;
    PORT
      LAYER M4 ;
        RECT  208.164 113.376 208.248 113.4 ;
    END
  END i2x_q1[225]
  PIN i2x_q1[226]
    DIRECTION INPUT ;
    USE SIGNAL ;
    PORT
      LAYER M4 ;
        RECT  208.164 113.472 208.248 113.496 ;
    END
  END i2x_q1[226]
  PIN i2x_q1[227]
    DIRECTION INPUT ;
    USE SIGNAL ;
    PORT
      LAYER M4 ;
        RECT  208.164 113.568 208.248 113.592 ;
    END
  END i2x_q1[227]
  PIN i2x_q1[228]
    DIRECTION INPUT ;
    USE SIGNAL ;
    PORT
      LAYER M4 ;
        RECT  208.164 113.664 208.248 113.688 ;
    END
  END i2x_q1[228]
  PIN i2x_q1[229]
    DIRECTION INPUT ;
    USE SIGNAL ;
    PORT
      LAYER M4 ;
        RECT  208.164 113.76 208.248 113.784 ;
    END
  END i2x_q1[229]
  PIN i2x_q1[22]
    DIRECTION INPUT ;
    USE SIGNAL ;
    PORT
      LAYER M4 ;
        RECT  208.164 93.888 208.248 93.912 ;
    END
  END i2x_q1[22]
  PIN i2x_q1[230]
    DIRECTION INPUT ;
    USE SIGNAL ;
    PORT
      LAYER M4 ;
        RECT  208.164 113.856 208.248 113.88 ;
    END
  END i2x_q1[230]
  PIN i2x_q1[231]
    DIRECTION INPUT ;
    USE SIGNAL ;
    PORT
      LAYER M4 ;
        RECT  208.164 113.952 208.248 113.976 ;
    END
  END i2x_q1[231]
  PIN i2x_q1[232]
    DIRECTION INPUT ;
    USE SIGNAL ;
    PORT
      LAYER M4 ;
        RECT  208.164 114.048 208.248 114.072 ;
    END
  END i2x_q1[232]
  PIN i2x_q1[233]
    DIRECTION INPUT ;
    USE SIGNAL ;
    PORT
      LAYER M4 ;
        RECT  208.164 114.144 208.248 114.168 ;
    END
  END i2x_q1[233]
  PIN i2x_q1[234]
    DIRECTION INPUT ;
    USE SIGNAL ;
    PORT
      LAYER M4 ;
        RECT  208.164 114.24 208.248 114.264 ;
    END
  END i2x_q1[234]
  PIN i2x_q1[235]
    DIRECTION INPUT ;
    USE SIGNAL ;
    PORT
      LAYER M4 ;
        RECT  208.164 114.336 208.248 114.36 ;
    END
  END i2x_q1[235]
  PIN i2x_q1[236]
    DIRECTION INPUT ;
    USE SIGNAL ;
    PORT
      LAYER M4 ;
        RECT  208.164 114.432 208.248 114.456 ;
    END
  END i2x_q1[236]
  PIN i2x_q1[237]
    DIRECTION INPUT ;
    USE SIGNAL ;
    PORT
      LAYER M4 ;
        RECT  208.164 114.528 208.248 114.552 ;
    END
  END i2x_q1[237]
  PIN i2x_q1[238]
    DIRECTION INPUT ;
    USE SIGNAL ;
    PORT
      LAYER M4 ;
        RECT  208.164 114.624 208.248 114.648 ;
    END
  END i2x_q1[238]
  PIN i2x_q1[239]
    DIRECTION INPUT ;
    USE SIGNAL ;
    PORT
      LAYER M4 ;
        RECT  208.164 114.72 208.248 114.744 ;
    END
  END i2x_q1[239]
  PIN i2x_q1[23]
    DIRECTION INPUT ;
    USE SIGNAL ;
    PORT
      LAYER M4 ;
        RECT  208.164 93.984 208.248 94.008 ;
    END
  END i2x_q1[23]
  PIN i2x_q1[240]
    DIRECTION INPUT ;
    USE SIGNAL ;
    PORT
      LAYER M4 ;
        RECT  208.164 114.816 208.248 114.84 ;
    END
  END i2x_q1[240]
  PIN i2x_q1[241]
    DIRECTION INPUT ;
    USE SIGNAL ;
    PORT
      LAYER M4 ;
        RECT  208.164 114.912 208.248 114.936 ;
    END
  END i2x_q1[241]
  PIN i2x_q1[242]
    DIRECTION INPUT ;
    USE SIGNAL ;
    PORT
      LAYER M4 ;
        RECT  208.164 115.008 208.248 115.032 ;
    END
  END i2x_q1[242]
  PIN i2x_q1[243]
    DIRECTION INPUT ;
    USE SIGNAL ;
    PORT
      LAYER M4 ;
        RECT  208.164 115.104 208.248 115.128 ;
    END
  END i2x_q1[243]
  PIN i2x_q1[244]
    DIRECTION INPUT ;
    USE SIGNAL ;
    PORT
      LAYER M4 ;
        RECT  208.164 115.2 208.248 115.224 ;
    END
  END i2x_q1[244]
  PIN i2x_q1[245]
    DIRECTION INPUT ;
    USE SIGNAL ;
    PORT
      LAYER M4 ;
        RECT  208.164 115.296 208.248 115.32 ;
    END
  END i2x_q1[245]
  PIN i2x_q1[246]
    DIRECTION INPUT ;
    USE SIGNAL ;
    PORT
      LAYER M4 ;
        RECT  208.164 115.392 208.248 115.416 ;
    END
  END i2x_q1[246]
  PIN i2x_q1[247]
    DIRECTION INPUT ;
    USE SIGNAL ;
    PORT
      LAYER M4 ;
        RECT  208.164 115.488 208.248 115.512 ;
    END
  END i2x_q1[247]
  PIN i2x_q1[248]
    DIRECTION INPUT ;
    USE SIGNAL ;
    PORT
      LAYER M4 ;
        RECT  208.164 115.584 208.248 115.608 ;
    END
  END i2x_q1[248]
  PIN i2x_q1[249]
    DIRECTION INPUT ;
    USE SIGNAL ;
    PORT
      LAYER M4 ;
        RECT  208.164 115.68 208.248 115.704 ;
    END
  END i2x_q1[249]
  PIN i2x_q1[24]
    DIRECTION INPUT ;
    USE SIGNAL ;
    PORT
      LAYER M4 ;
        RECT  208.164 94.08 208.248 94.104 ;
    END
  END i2x_q1[24]
  PIN i2x_q1[250]
    DIRECTION INPUT ;
    USE SIGNAL ;
    PORT
      LAYER M4 ;
        RECT  208.164 115.776 208.248 115.8 ;
    END
  END i2x_q1[250]
  PIN i2x_q1[251]
    DIRECTION INPUT ;
    USE SIGNAL ;
    PORT
      LAYER M4 ;
        RECT  208.164 115.872 208.248 115.896 ;
    END
  END i2x_q1[251]
  PIN i2x_q1[252]
    DIRECTION INPUT ;
    USE SIGNAL ;
    PORT
      LAYER M4 ;
        RECT  208.164 115.968 208.248 115.992 ;
    END
  END i2x_q1[252]
  PIN i2x_q1[253]
    DIRECTION INPUT ;
    USE SIGNAL ;
    PORT
      LAYER M4 ;
        RECT  208.164 116.064 208.248 116.088 ;
    END
  END i2x_q1[253]
  PIN i2x_q1[254]
    DIRECTION INPUT ;
    USE SIGNAL ;
    PORT
      LAYER M4 ;
        RECT  208.164 116.16 208.248 116.184 ;
    END
  END i2x_q1[254]
  PIN i2x_q1[255]
    DIRECTION INPUT ;
    USE SIGNAL ;
    PORT
      LAYER M4 ;
        RECT  208.164 116.256 208.248 116.28 ;
    END
  END i2x_q1[255]
  PIN i2x_q1[25]
    DIRECTION INPUT ;
    USE SIGNAL ;
    PORT
      LAYER M4 ;
        RECT  208.164 94.176 208.248 94.2 ;
    END
  END i2x_q1[25]
  PIN i2x_q1[26]
    DIRECTION INPUT ;
    USE SIGNAL ;
    PORT
      LAYER M4 ;
        RECT  208.164 94.272 208.248 94.296 ;
    END
  END i2x_q1[26]
  PIN i2x_q1[27]
    DIRECTION INPUT ;
    USE SIGNAL ;
    PORT
      LAYER M4 ;
        RECT  208.164 94.368 208.248 94.392 ;
    END
  END i2x_q1[27]
  PIN i2x_q1[28]
    DIRECTION INPUT ;
    USE SIGNAL ;
    PORT
      LAYER M4 ;
        RECT  208.164 94.464 208.248 94.488 ;
    END
  END i2x_q1[28]
  PIN i2x_q1[29]
    DIRECTION INPUT ;
    USE SIGNAL ;
    PORT
      LAYER M4 ;
        RECT  208.164 94.56 208.248 94.584 ;
    END
  END i2x_q1[29]
  PIN i2x_q1[2]
    DIRECTION INPUT ;
    USE SIGNAL ;
    PORT
      LAYER M4 ;
        RECT  208.164 91.968 208.248 91.992 ;
    END
  END i2x_q1[2]
  PIN i2x_q1[30]
    DIRECTION INPUT ;
    USE SIGNAL ;
    PORT
      LAYER M4 ;
        RECT  208.164 94.656 208.248 94.68 ;
    END
  END i2x_q1[30]
  PIN i2x_q1[31]
    DIRECTION INPUT ;
    USE SIGNAL ;
    PORT
      LAYER M4 ;
        RECT  208.164 94.752 208.248 94.776 ;
    END
  END i2x_q1[31]
  PIN i2x_q1[32]
    DIRECTION INPUT ;
    USE SIGNAL ;
    PORT
      LAYER M4 ;
        RECT  208.164 94.848 208.248 94.872 ;
    END
  END i2x_q1[32]
  PIN i2x_q1[33]
    DIRECTION INPUT ;
    USE SIGNAL ;
    PORT
      LAYER M4 ;
        RECT  208.164 94.944 208.248 94.968 ;
    END
  END i2x_q1[33]
  PIN i2x_q1[34]
    DIRECTION INPUT ;
    USE SIGNAL ;
    PORT
      LAYER M4 ;
        RECT  208.164 95.04 208.248 95.064 ;
    END
  END i2x_q1[34]
  PIN i2x_q1[35]
    DIRECTION INPUT ;
    USE SIGNAL ;
    PORT
      LAYER M4 ;
        RECT  208.164 95.136 208.248 95.16 ;
    END
  END i2x_q1[35]
  PIN i2x_q1[36]
    DIRECTION INPUT ;
    USE SIGNAL ;
    PORT
      LAYER M4 ;
        RECT  208.164 95.232 208.248 95.256 ;
    END
  END i2x_q1[36]
  PIN i2x_q1[37]
    DIRECTION INPUT ;
    USE SIGNAL ;
    PORT
      LAYER M4 ;
        RECT  208.164 95.328 208.248 95.352 ;
    END
  END i2x_q1[37]
  PIN i2x_q1[38]
    DIRECTION INPUT ;
    USE SIGNAL ;
    PORT
      LAYER M4 ;
        RECT  208.164 95.424 208.248 95.448 ;
    END
  END i2x_q1[38]
  PIN i2x_q1[39]
    DIRECTION INPUT ;
    USE SIGNAL ;
    PORT
      LAYER M4 ;
        RECT  208.164 95.52 208.248 95.544 ;
    END
  END i2x_q1[39]
  PIN i2x_q1[3]
    DIRECTION INPUT ;
    USE SIGNAL ;
    PORT
      LAYER M4 ;
        RECT  208.164 92.064 208.248 92.088 ;
    END
  END i2x_q1[3]
  PIN i2x_q1[40]
    DIRECTION INPUT ;
    USE SIGNAL ;
    PORT
      LAYER M4 ;
        RECT  208.164 95.616 208.248 95.64 ;
    END
  END i2x_q1[40]
  PIN i2x_q1[41]
    DIRECTION INPUT ;
    USE SIGNAL ;
    PORT
      LAYER M4 ;
        RECT  208.164 95.712 208.248 95.736 ;
    END
  END i2x_q1[41]
  PIN i2x_q1[42]
    DIRECTION INPUT ;
    USE SIGNAL ;
    PORT
      LAYER M4 ;
        RECT  208.164 95.808 208.248 95.832 ;
    END
  END i2x_q1[42]
  PIN i2x_q1[43]
    DIRECTION INPUT ;
    USE SIGNAL ;
    PORT
      LAYER M4 ;
        RECT  208.164 95.904 208.248 95.928 ;
    END
  END i2x_q1[43]
  PIN i2x_q1[44]
    DIRECTION INPUT ;
    USE SIGNAL ;
    PORT
      LAYER M4 ;
        RECT  208.164 96 208.248 96.024 ;
    END
  END i2x_q1[44]
  PIN i2x_q1[45]
    DIRECTION INPUT ;
    USE SIGNAL ;
    PORT
      LAYER M4 ;
        RECT  208.164 96.096 208.248 96.12 ;
    END
  END i2x_q1[45]
  PIN i2x_q1[46]
    DIRECTION INPUT ;
    USE SIGNAL ;
    PORT
      LAYER M4 ;
        RECT  208.164 96.192 208.248 96.216 ;
    END
  END i2x_q1[46]
  PIN i2x_q1[47]
    DIRECTION INPUT ;
    USE SIGNAL ;
    PORT
      LAYER M4 ;
        RECT  208.164 96.288 208.248 96.312 ;
    END
  END i2x_q1[47]
  PIN i2x_q1[48]
    DIRECTION INPUT ;
    USE SIGNAL ;
    PORT
      LAYER M4 ;
        RECT  208.164 96.384 208.248 96.408 ;
    END
  END i2x_q1[48]
  PIN i2x_q1[49]
    DIRECTION INPUT ;
    USE SIGNAL ;
    PORT
      LAYER M4 ;
        RECT  208.164 96.48 208.248 96.504 ;
    END
  END i2x_q1[49]
  PIN i2x_q1[4]
    DIRECTION INPUT ;
    USE SIGNAL ;
    PORT
      LAYER M4 ;
        RECT  208.164 92.16 208.248 92.184 ;
    END
  END i2x_q1[4]
  PIN i2x_q1[50]
    DIRECTION INPUT ;
    USE SIGNAL ;
    PORT
      LAYER M4 ;
        RECT  208.164 96.576 208.248 96.6 ;
    END
  END i2x_q1[50]
  PIN i2x_q1[51]
    DIRECTION INPUT ;
    USE SIGNAL ;
    PORT
      LAYER M4 ;
        RECT  208.164 96.672 208.248 96.696 ;
    END
  END i2x_q1[51]
  PIN i2x_q1[52]
    DIRECTION INPUT ;
    USE SIGNAL ;
    PORT
      LAYER M4 ;
        RECT  208.164 96.768 208.248 96.792 ;
    END
  END i2x_q1[52]
  PIN i2x_q1[53]
    DIRECTION INPUT ;
    USE SIGNAL ;
    PORT
      LAYER M4 ;
        RECT  208.164 96.864 208.248 96.888 ;
    END
  END i2x_q1[53]
  PIN i2x_q1[54]
    DIRECTION INPUT ;
    USE SIGNAL ;
    PORT
      LAYER M4 ;
        RECT  208.164 96.96 208.248 96.984 ;
    END
  END i2x_q1[54]
  PIN i2x_q1[55]
    DIRECTION INPUT ;
    USE SIGNAL ;
    PORT
      LAYER M4 ;
        RECT  208.164 97.056 208.248 97.08 ;
    END
  END i2x_q1[55]
  PIN i2x_q1[56]
    DIRECTION INPUT ;
    USE SIGNAL ;
    PORT
      LAYER M4 ;
        RECT  208.164 97.152 208.248 97.176 ;
    END
  END i2x_q1[56]
  PIN i2x_q1[57]
    DIRECTION INPUT ;
    USE SIGNAL ;
    PORT
      LAYER M4 ;
        RECT  208.164 97.248 208.248 97.272 ;
    END
  END i2x_q1[57]
  PIN i2x_q1[58]
    DIRECTION INPUT ;
    USE SIGNAL ;
    PORT
      LAYER M4 ;
        RECT  208.164 97.344 208.248 97.368 ;
    END
  END i2x_q1[58]
  PIN i2x_q1[59]
    DIRECTION INPUT ;
    USE SIGNAL ;
    PORT
      LAYER M4 ;
        RECT  208.164 97.44 208.248 97.464 ;
    END
  END i2x_q1[59]
  PIN i2x_q1[5]
    DIRECTION INPUT ;
    USE SIGNAL ;
    PORT
      LAYER M4 ;
        RECT  208.164 92.256 208.248 92.28 ;
    END
  END i2x_q1[5]
  PIN i2x_q1[60]
    DIRECTION INPUT ;
    USE SIGNAL ;
    PORT
      LAYER M4 ;
        RECT  208.164 97.536 208.248 97.56 ;
    END
  END i2x_q1[60]
  PIN i2x_q1[61]
    DIRECTION INPUT ;
    USE SIGNAL ;
    PORT
      LAYER M4 ;
        RECT  208.164 97.632 208.248 97.656 ;
    END
  END i2x_q1[61]
  PIN i2x_q1[62]
    DIRECTION INPUT ;
    USE SIGNAL ;
    PORT
      LAYER M4 ;
        RECT  208.164 97.728 208.248 97.752 ;
    END
  END i2x_q1[62]
  PIN i2x_q1[63]
    DIRECTION INPUT ;
    USE SIGNAL ;
    PORT
      LAYER M4 ;
        RECT  208.164 97.824 208.248 97.848 ;
    END
  END i2x_q1[63]
  PIN i2x_q1[64]
    DIRECTION INPUT ;
    USE SIGNAL ;
    PORT
      LAYER M4 ;
        RECT  208.164 97.92 208.248 97.944 ;
    END
  END i2x_q1[64]
  PIN i2x_q1[65]
    DIRECTION INPUT ;
    USE SIGNAL ;
    PORT
      LAYER M4 ;
        RECT  208.164 98.016 208.248 98.04 ;
    END
  END i2x_q1[65]
  PIN i2x_q1[66]
    DIRECTION INPUT ;
    USE SIGNAL ;
    PORT
      LAYER M4 ;
        RECT  208.164 98.112 208.248 98.136 ;
    END
  END i2x_q1[66]
  PIN i2x_q1[67]
    DIRECTION INPUT ;
    USE SIGNAL ;
    PORT
      LAYER M4 ;
        RECT  208.164 98.208 208.248 98.232 ;
    END
  END i2x_q1[67]
  PIN i2x_q1[68]
    DIRECTION INPUT ;
    USE SIGNAL ;
    PORT
      LAYER M4 ;
        RECT  208.164 98.304 208.248 98.328 ;
    END
  END i2x_q1[68]
  PIN i2x_q1[69]
    DIRECTION INPUT ;
    USE SIGNAL ;
    PORT
      LAYER M4 ;
        RECT  208.164 98.4 208.248 98.424 ;
    END
  END i2x_q1[69]
  PIN i2x_q1[6]
    DIRECTION INPUT ;
    USE SIGNAL ;
    PORT
      LAYER M4 ;
        RECT  208.164 92.352 208.248 92.376 ;
    END
  END i2x_q1[6]
  PIN i2x_q1[70]
    DIRECTION INPUT ;
    USE SIGNAL ;
    PORT
      LAYER M4 ;
        RECT  208.164 98.496 208.248 98.52 ;
    END
  END i2x_q1[70]
  PIN i2x_q1[71]
    DIRECTION INPUT ;
    USE SIGNAL ;
    PORT
      LAYER M4 ;
        RECT  208.164 98.592 208.248 98.616 ;
    END
  END i2x_q1[71]
  PIN i2x_q1[72]
    DIRECTION INPUT ;
    USE SIGNAL ;
    PORT
      LAYER M4 ;
        RECT  208.164 98.688 208.248 98.712 ;
    END
  END i2x_q1[72]
  PIN i2x_q1[73]
    DIRECTION INPUT ;
    USE SIGNAL ;
    PORT
      LAYER M4 ;
        RECT  208.164 98.784 208.248 98.808 ;
    END
  END i2x_q1[73]
  PIN i2x_q1[74]
    DIRECTION INPUT ;
    USE SIGNAL ;
    PORT
      LAYER M4 ;
        RECT  208.164 98.88 208.248 98.904 ;
    END
  END i2x_q1[74]
  PIN i2x_q1[75]
    DIRECTION INPUT ;
    USE SIGNAL ;
    PORT
      LAYER M4 ;
        RECT  208.164 98.976 208.248 99 ;
    END
  END i2x_q1[75]
  PIN i2x_q1[76]
    DIRECTION INPUT ;
    USE SIGNAL ;
    PORT
      LAYER M4 ;
        RECT  208.164 99.072 208.248 99.096 ;
    END
  END i2x_q1[76]
  PIN i2x_q1[77]
    DIRECTION INPUT ;
    USE SIGNAL ;
    PORT
      LAYER M4 ;
        RECT  208.164 99.168 208.248 99.192 ;
    END
  END i2x_q1[77]
  PIN i2x_q1[78]
    DIRECTION INPUT ;
    USE SIGNAL ;
    PORT
      LAYER M4 ;
        RECT  208.164 99.264 208.248 99.288 ;
    END
  END i2x_q1[78]
  PIN i2x_q1[79]
    DIRECTION INPUT ;
    USE SIGNAL ;
    PORT
      LAYER M4 ;
        RECT  208.164 99.36 208.248 99.384 ;
    END
  END i2x_q1[79]
  PIN i2x_q1[7]
    DIRECTION INPUT ;
    USE SIGNAL ;
    PORT
      LAYER M4 ;
        RECT  208.164 92.448 208.248 92.472 ;
    END
  END i2x_q1[7]
  PIN i2x_q1[80]
    DIRECTION INPUT ;
    USE SIGNAL ;
    PORT
      LAYER M4 ;
        RECT  208.164 99.456 208.248 99.48 ;
    END
  END i2x_q1[80]
  PIN i2x_q1[81]
    DIRECTION INPUT ;
    USE SIGNAL ;
    PORT
      LAYER M4 ;
        RECT  208.164 99.552 208.248 99.576 ;
    END
  END i2x_q1[81]
  PIN i2x_q1[82]
    DIRECTION INPUT ;
    USE SIGNAL ;
    PORT
      LAYER M4 ;
        RECT  208.164 99.648 208.248 99.672 ;
    END
  END i2x_q1[82]
  PIN i2x_q1[83]
    DIRECTION INPUT ;
    USE SIGNAL ;
    PORT
      LAYER M4 ;
        RECT  208.164 99.744 208.248 99.768 ;
    END
  END i2x_q1[83]
  PIN i2x_q1[84]
    DIRECTION INPUT ;
    USE SIGNAL ;
    PORT
      LAYER M4 ;
        RECT  208.164 99.84 208.248 99.864 ;
    END
  END i2x_q1[84]
  PIN i2x_q1[85]
    DIRECTION INPUT ;
    USE SIGNAL ;
    PORT
      LAYER M4 ;
        RECT  208.164 99.936 208.248 99.96 ;
    END
  END i2x_q1[85]
  PIN i2x_q1[86]
    DIRECTION INPUT ;
    USE SIGNAL ;
    PORT
      LAYER M4 ;
        RECT  208.164 100.032 208.248 100.056 ;
    END
  END i2x_q1[86]
  PIN i2x_q1[87]
    DIRECTION INPUT ;
    USE SIGNAL ;
    PORT
      LAYER M4 ;
        RECT  208.164 100.128 208.248 100.152 ;
    END
  END i2x_q1[87]
  PIN i2x_q1[88]
    DIRECTION INPUT ;
    USE SIGNAL ;
    PORT
      LAYER M4 ;
        RECT  208.164 100.224 208.248 100.248 ;
    END
  END i2x_q1[88]
  PIN i2x_q1[89]
    DIRECTION INPUT ;
    USE SIGNAL ;
    PORT
      LAYER M4 ;
        RECT  208.164 100.32 208.248 100.344 ;
    END
  END i2x_q1[89]
  PIN i2x_q1[8]
    DIRECTION INPUT ;
    USE SIGNAL ;
    PORT
      LAYER M4 ;
        RECT  208.164 92.544 208.248 92.568 ;
    END
  END i2x_q1[8]
  PIN i2x_q1[90]
    DIRECTION INPUT ;
    USE SIGNAL ;
    PORT
      LAYER M4 ;
        RECT  208.164 100.416 208.248 100.44 ;
    END
  END i2x_q1[90]
  PIN i2x_q1[91]
    DIRECTION INPUT ;
    USE SIGNAL ;
    PORT
      LAYER M4 ;
        RECT  208.164 100.512 208.248 100.536 ;
    END
  END i2x_q1[91]
  PIN i2x_q1[92]
    DIRECTION INPUT ;
    USE SIGNAL ;
    PORT
      LAYER M4 ;
        RECT  208.164 100.608 208.248 100.632 ;
    END
  END i2x_q1[92]
  PIN i2x_q1[93]
    DIRECTION INPUT ;
    USE SIGNAL ;
    PORT
      LAYER M4 ;
        RECT  208.164 100.704 208.248 100.728 ;
    END
  END i2x_q1[93]
  PIN i2x_q1[94]
    DIRECTION INPUT ;
    USE SIGNAL ;
    PORT
      LAYER M4 ;
        RECT  208.164 100.8 208.248 100.824 ;
    END
  END i2x_q1[94]
  PIN i2x_q1[95]
    DIRECTION INPUT ;
    USE SIGNAL ;
    PORT
      LAYER M4 ;
        RECT  208.164 100.896 208.248 100.92 ;
    END
  END i2x_q1[95]
  PIN i2x_q1[96]
    DIRECTION INPUT ;
    USE SIGNAL ;
    PORT
      LAYER M4 ;
        RECT  208.164 100.992 208.248 101.016 ;
    END
  END i2x_q1[96]
  PIN i2x_q1[97]
    DIRECTION INPUT ;
    USE SIGNAL ;
    PORT
      LAYER M4 ;
        RECT  208.164 101.088 208.248 101.112 ;
    END
  END i2x_q1[97]
  PIN i2x_q1[98]
    DIRECTION INPUT ;
    USE SIGNAL ;
    PORT
      LAYER M4 ;
        RECT  208.164 101.184 208.248 101.208 ;
    END
  END i2x_q1[98]
  PIN i2x_q1[99]
    DIRECTION INPUT ;
    USE SIGNAL ;
    PORT
      LAYER M4 ;
        RECT  208.164 101.28 208.248 101.304 ;
    END
  END i2x_q1[99]
  PIN i2x_q1[9]
    DIRECTION INPUT ;
    USE SIGNAL ;
    PORT
      LAYER M4 ;
        RECT  208.164 92.64 208.248 92.664 ;
    END
  END i2x_q1[9]
  PIN issue
    DIRECTION INPUT ;
    USE SIGNAL ;
    PORT
      LAYER M4 ;
        RECT  208.164 116.352 208.248 116.376 ;
    END
  END issue
  PIN perr
    DIRECTION OUTPUT ;
    USE SIGNAL ;
    PORT
      LAYER M5 ;
        RECT  148.992 0 149.016 0.084 ;
    END
  END perr
  PIN pnseg[0]
    DIRECTION OUTPUT ;
    USE SIGNAL ;
    PORT
      LAYER M5 ;
        RECT  149.088 0 149.112 0.084 ;
    END
  END pnseg[0]
  PIN pnseg[1]
    DIRECTION OUTPUT ;
    USE SIGNAL ;
    PORT
      LAYER M5 ;
        RECT  149.184 0 149.208 0.084 ;
    END
  END pnseg[1]
  PIN pnseg[2]
    DIRECTION OUTPUT ;
    USE SIGNAL ;
    PORT
      LAYER M5 ;
        RECT  149.28 0 149.304 0.084 ;
    END
  END pnseg[2]
  PIN pnseg[3]
    DIRECTION OUTPUT ;
    USE SIGNAL ;
    PORT
      LAYER M5 ;
        RECT  149.376 0 149.4 0.084 ;
    END
  END pnseg[3]
  PIN pnseg[4]
    DIRECTION OUTPUT ;
    USE SIGNAL ;
    PORT
      LAYER M5 ;
        RECT  149.472 0 149.496 0.084 ;
    END
  END pnseg[4]
  PIN ppos[0]
    DIRECTION OUTPUT ;
    USE SIGNAL ;
    PORT
      LAYER M5 ;
        RECT  149.568 0 149.592 0.084 ;
    END
  END ppos[0]
  PIN ppos[1]
    DIRECTION OUTPUT ;
    USE SIGNAL ;
    PORT
      LAYER M5 ;
        RECT  149.664 0 149.688 0.084 ;
    END
  END ppos[1]
  PIN ppos[2]
    DIRECTION OUTPUT ;
    USE SIGNAL ;
    PORT
      LAYER M5 ;
        RECT  149.76 0 149.784 0.084 ;
    END
  END ppos[2]
  PIN prow[0]
    DIRECTION OUTPUT ;
    USE SIGNAL ;
    PORT
      LAYER M5 ;
        RECT  149.856 0 149.88 0.084 ;
    END
  END prow[0]
  PIN prow[10]
    DIRECTION OUTPUT ;
    USE SIGNAL ;
    PORT
      LAYER M5 ;
        RECT  150.816 0 150.84 0.084 ;
    END
  END prow[10]
  PIN prow[11]
    DIRECTION OUTPUT ;
    USE SIGNAL ;
    PORT
      LAYER M5 ;
        RECT  150.912 0 150.936 0.084 ;
    END
  END prow[11]
  PIN prow[12]
    DIRECTION OUTPUT ;
    USE SIGNAL ;
    PORT
      LAYER M5 ;
        RECT  151.008 0 151.032 0.084 ;
    END
  END prow[12]
  PIN prow[13]
    DIRECTION OUTPUT ;
    USE SIGNAL ;
    PORT
      LAYER M5 ;
        RECT  151.104 0 151.128 0.084 ;
    END
  END prow[13]
  PIN prow[14]
    DIRECTION OUTPUT ;
    USE SIGNAL ;
    PORT
      LAYER M5 ;
        RECT  151.2 0 151.224 0.084 ;
    END
  END prow[14]
  PIN prow[15]
    DIRECTION OUTPUT ;
    USE SIGNAL ;
    PORT
      LAYER M5 ;
        RECT  151.296 0 151.32 0.084 ;
    END
  END prow[15]
  PIN prow[1]
    DIRECTION OUTPUT ;
    USE SIGNAL ;
    PORT
      LAYER M5 ;
        RECT  149.952 0 149.976 0.084 ;
    END
  END prow[1]
  PIN prow[2]
    DIRECTION OUTPUT ;
    USE SIGNAL ;
    PORT
      LAYER M5 ;
        RECT  150.048 0 150.072 0.084 ;
    END
  END prow[2]
  PIN prow[3]
    DIRECTION OUTPUT ;
    USE SIGNAL ;
    PORT
      LAYER M5 ;
        RECT  150.144 0 150.168 0.084 ;
    END
  END prow[3]
  PIN prow[4]
    DIRECTION OUTPUT ;
    USE SIGNAL ;
    PORT
      LAYER M5 ;
        RECT  150.24 0 150.264 0.084 ;
    END
  END prow[4]
  PIN prow[5]
    DIRECTION OUTPUT ;
    USE SIGNAL ;
    PORT
      LAYER M5 ;
        RECT  150.336 0 150.36 0.084 ;
    END
  END prow[5]
  PIN prow[6]
    DIRECTION OUTPUT ;
    USE SIGNAL ;
    PORT
      LAYER M5 ;
        RECT  150.432 0 150.456 0.084 ;
    END
  END prow[6]
  PIN prow[7]
    DIRECTION OUTPUT ;
    USE SIGNAL ;
    PORT
      LAYER M5 ;
        RECT  150.528 0 150.552 0.084 ;
    END
  END prow[7]
  PIN prow[8]
    DIRECTION OUTPUT ;
    USE SIGNAL ;
    PORT
      LAYER M5 ;
        RECT  150.624 0 150.648 0.084 ;
    END
  END prow[8]
  PIN prow[9]
    DIRECTION OUTPUT ;
    USE SIGNAL ;
    PORT
      LAYER M5 ;
        RECT  150.72 0 150.744 0.084 ;
    END
  END prow[9]
  PIN pseg[0]
    DIRECTION OUTPUT ;
    USE SIGNAL ;
    PORT
      LAYER M5 ;
        RECT  151.392 0 151.416 0.084 ;
    END
  END pseg[0]
  PIN pseg[1]
    DIRECTION OUTPUT ;
    USE SIGNAL ;
    PORT
      LAYER M5 ;
        RECT  151.488 0 151.512 0.084 ;
    END
  END pseg[1]
  PIN pseg[2]
    DIRECTION OUTPUT ;
    USE SIGNAL ;
    PORT
      LAYER M5 ;
        RECT  151.584 0 151.608 0.084 ;
    END
  END pseg[2]
  PIN pseg[3]
    DIRECTION OUTPUT ;
    USE SIGNAL ;
    PORT
      LAYER M5 ;
        RECT  151.68 0 151.704 0.084 ;
    END
  END pseg[3]
  PIN pseg[4]
    DIRECTION OUTPUT ;
    USE SIGNAL ;
    PORT
      LAYER M5 ;
        RECT  151.776 0 151.8 0.084 ;
    END
  END pseg[4]
  PIN pv
    DIRECTION OUTPUT ;
    USE SIGNAL ;
    PORT
      LAYER M5 ;
        RECT  151.872 0 151.896 0.084 ;
    END
  END pv
  PIN pval[0]
    DIRECTION OUTPUT ;
    USE SIGNAL ;
    PORT
      LAYER M5 ;
        RECT  151.968 0 151.992 0.084 ;
    END
  END pval[0]
  PIN pval[10]
    DIRECTION OUTPUT ;
    USE SIGNAL ;
    PORT
      LAYER M5 ;
        RECT  152.928 0 152.952 0.084 ;
    END
  END pval[10]
  PIN pval[11]
    DIRECTION OUTPUT ;
    USE SIGNAL ;
    PORT
      LAYER M5 ;
        RECT  153.024 0 153.048 0.084 ;
    END
  END pval[11]
  PIN pval[12]
    DIRECTION OUTPUT ;
    USE SIGNAL ;
    PORT
      LAYER M5 ;
        RECT  153.12 0 153.144 0.084 ;
    END
  END pval[12]
  PIN pval[13]
    DIRECTION OUTPUT ;
    USE SIGNAL ;
    PORT
      LAYER M5 ;
        RECT  153.216 0 153.24 0.084 ;
    END
  END pval[13]
  PIN pval[14]
    DIRECTION OUTPUT ;
    USE SIGNAL ;
    PORT
      LAYER M5 ;
        RECT  153.312 0 153.336 0.084 ;
    END
  END pval[14]
  PIN pval[15]
    DIRECTION OUTPUT ;
    USE SIGNAL ;
    PORT
      LAYER M5 ;
        RECT  153.408 0 153.432 0.084 ;
    END
  END pval[15]
  PIN pval[16]
    DIRECTION OUTPUT ;
    USE SIGNAL ;
    PORT
      LAYER M5 ;
        RECT  153.504 0 153.528 0.084 ;
    END
  END pval[16]
  PIN pval[17]
    DIRECTION OUTPUT ;
    USE SIGNAL ;
    PORT
      LAYER M5 ;
        RECT  153.6 0 153.624 0.084 ;
    END
  END pval[17]
  PIN pval[18]
    DIRECTION OUTPUT ;
    USE SIGNAL ;
    PORT
      LAYER M5 ;
        RECT  153.696 0 153.72 0.084 ;
    END
  END pval[18]
  PIN pval[19]
    DIRECTION OUTPUT ;
    USE SIGNAL ;
    PORT
      LAYER M5 ;
        RECT  153.792 0 153.816 0.084 ;
    END
  END pval[19]
  PIN pval[1]
    DIRECTION OUTPUT ;
    USE SIGNAL ;
    PORT
      LAYER M5 ;
        RECT  152.064 0 152.088 0.084 ;
    END
  END pval[1]
  PIN pval[20]
    DIRECTION OUTPUT ;
    USE SIGNAL ;
    PORT
      LAYER M5 ;
        RECT  153.888 0 153.912 0.084 ;
    END
  END pval[20]
  PIN pval[21]
    DIRECTION OUTPUT ;
    USE SIGNAL ;
    PORT
      LAYER M5 ;
        RECT  153.984 0 154.008 0.084 ;
    END
  END pval[21]
  PIN pval[22]
    DIRECTION OUTPUT ;
    USE SIGNAL ;
    PORT
      LAYER M5 ;
        RECT  154.08 0 154.104 0.084 ;
    END
  END pval[22]
  PIN pval[23]
    DIRECTION OUTPUT ;
    USE SIGNAL ;
    PORT
      LAYER M5 ;
        RECT  154.176 0 154.2 0.084 ;
    END
  END pval[23]
  PIN pval[24]
    DIRECTION OUTPUT ;
    USE SIGNAL ;
    PORT
      LAYER M5 ;
        RECT  154.272 0 154.296 0.084 ;
    END
  END pval[24]
  PIN pval[25]
    DIRECTION OUTPUT ;
    USE SIGNAL ;
    PORT
      LAYER M5 ;
        RECT  154.368 0 154.392 0.084 ;
    END
  END pval[25]
  PIN pval[26]
    DIRECTION OUTPUT ;
    USE SIGNAL ;
    PORT
      LAYER M5 ;
        RECT  154.464 0 154.488 0.084 ;
    END
  END pval[26]
  PIN pval[27]
    DIRECTION OUTPUT ;
    USE SIGNAL ;
    PORT
      LAYER M5 ;
        RECT  154.56 0 154.584 0.084 ;
    END
  END pval[27]
  PIN pval[28]
    DIRECTION OUTPUT ;
    USE SIGNAL ;
    PORT
      LAYER M5 ;
        RECT  154.656 0 154.68 0.084 ;
    END
  END pval[28]
  PIN pval[29]
    DIRECTION OUTPUT ;
    USE SIGNAL ;
    PORT
      LAYER M5 ;
        RECT  154.752 0 154.776 0.084 ;
    END
  END pval[29]
  PIN pval[2]
    DIRECTION OUTPUT ;
    USE SIGNAL ;
    PORT
      LAYER M5 ;
        RECT  152.16 0 152.184 0.084 ;
    END
  END pval[2]
  PIN pval[30]
    DIRECTION OUTPUT ;
    USE SIGNAL ;
    PORT
      LAYER M5 ;
        RECT  154.848 0 154.872 0.084 ;
    END
  END pval[30]
  PIN pval[31]
    DIRECTION OUTPUT ;
    USE SIGNAL ;
    PORT
      LAYER M5 ;
        RECT  154.944 0 154.968 0.084 ;
    END
  END pval[31]
  PIN pval[3]
    DIRECTION OUTPUT ;
    USE SIGNAL ;
    PORT
      LAYER M5 ;
        RECT  152.256 0 152.28 0.084 ;
    END
  END pval[3]
  PIN pval[4]
    DIRECTION OUTPUT ;
    USE SIGNAL ;
    PORT
      LAYER M5 ;
        RECT  152.352 0 152.376 0.084 ;
    END
  END pval[4]
  PIN pval[5]
    DIRECTION OUTPUT ;
    USE SIGNAL ;
    PORT
      LAYER M5 ;
        RECT  152.448 0 152.472 0.084 ;
    END
  END pval[5]
  PIN pval[6]
    DIRECTION OUTPUT ;
    USE SIGNAL ;
    PORT
      LAYER M5 ;
        RECT  152.544 0 152.568 0.084 ;
    END
  END pval[6]
  PIN pval[7]
    DIRECTION OUTPUT ;
    USE SIGNAL ;
    PORT
      LAYER M5 ;
        RECT  152.64 0 152.664 0.084 ;
    END
  END pval[7]
  PIN pval[8]
    DIRECTION OUTPUT ;
    USE SIGNAL ;
    PORT
      LAYER M5 ;
        RECT  152.736 0 152.76 0.084 ;
    END
  END pval[8]
  PIN pval[9]
    DIRECTION OUTPUT ;
    USE SIGNAL ;
    PORT
      LAYER M5 ;
        RECT  152.832 0 152.856 0.084 ;
    END
  END pval[9]
  PIN qy_bkf
    DIRECTION OUTPUT ;
    USE SIGNAL ;
    PORT
      LAYER M5 ;
        RECT  155.04 0 155.064 0.084 ;
    END
  END qy_bkf
  PIN r_err_a
    DIRECTION INPUT ;
    USE SIGNAL ;
    PORT
      LAYER M4 ;
        RECT  0 75.936 0.084 75.96 ;
    END
  END r_err_a
  PIN r_err_b
    DIRECTION INPUT ;
    USE SIGNAL ;
    PORT
      LAYER M4 ;
        RECT  0 179.616 0.084 179.64 ;
    END
  END r_err_b
  PIN r_f_a
    DIRECTION INPUT ;
    USE SIGNAL ;
    PORT
      LAYER M4 ;
        RECT  0 77.664 0.084 77.688 ;
    END
  END r_f_a
  PIN r_f_b
    DIRECTION INPUT ;
    USE SIGNAL ;
    PORT
      LAYER M4 ;
        RECT  0 181.344 0.084 181.368 ;
    END
  END r_f_b
  PIN r_t_a[0]
    DIRECTION INPUT ;
    USE SIGNAL ;
    PORT
      LAYER M4 ;
        RECT  0 76.128 0.084 76.152 ;
    END
  END r_t_a[0]
  PIN r_t_a[1]
    DIRECTION INPUT ;
    USE SIGNAL ;
    PORT
      LAYER M4 ;
        RECT  0 76.32 0.084 76.344 ;
    END
  END r_t_a[1]
  PIN r_t_a[2]
    DIRECTION INPUT ;
    USE SIGNAL ;
    PORT
      LAYER M4 ;
        RECT  0 76.512 0.084 76.536 ;
    END
  END r_t_a[2]
  PIN r_t_a[3]
    DIRECTION INPUT ;
    USE SIGNAL ;
    PORT
      LAYER M4 ;
        RECT  0 76.704 0.084 76.728 ;
    END
  END r_t_a[3]
  PIN r_t_a[4]
    DIRECTION INPUT ;
    USE SIGNAL ;
    PORT
      LAYER M4 ;
        RECT  0 76.896 0.084 76.92 ;
    END
  END r_t_a[4]
  PIN r_t_a[5]
    DIRECTION INPUT ;
    USE SIGNAL ;
    PORT
      LAYER M4 ;
        RECT  0 77.088 0.084 77.112 ;
    END
  END r_t_a[5]
  PIN r_t_a[6]
    DIRECTION INPUT ;
    USE SIGNAL ;
    PORT
      LAYER M4 ;
        RECT  0 77.28 0.084 77.304 ;
    END
  END r_t_a[6]
  PIN r_t_a[7]
    DIRECTION INPUT ;
    USE SIGNAL ;
    PORT
      LAYER M4 ;
        RECT  0 77.472 0.084 77.496 ;
    END
  END r_t_a[7]
  PIN r_v_a
    DIRECTION INPUT ;
    USE SIGNAL ;
    PORT
      LAYER M4 ;
        RECT  0 69.6 0.084 69.624 ;
    END
  END r_v_a
  PIN r_val_a[0]
    DIRECTION INPUT ;
    USE SIGNAL ;
    PORT
      LAYER M4 ;
        RECT  0 69.792 0.084 69.816 ;
    END
  END r_val_a[0]
  PIN r_val_a[10]
    DIRECTION INPUT ;
    USE SIGNAL ;
    PORT
      LAYER M4 ;
        RECT  0 71.712 0.084 71.736 ;
    END
  END r_val_a[10]
  PIN r_val_a[11]
    DIRECTION INPUT ;
    USE SIGNAL ;
    PORT
      LAYER M4 ;
        RECT  0 71.904 0.084 71.928 ;
    END
  END r_val_a[11]
  PIN r_val_a[12]
    DIRECTION INPUT ;
    USE SIGNAL ;
    PORT
      LAYER M4 ;
        RECT  0 72.096 0.084 72.12 ;
    END
  END r_val_a[12]
  PIN r_val_a[13]
    DIRECTION INPUT ;
    USE SIGNAL ;
    PORT
      LAYER M4 ;
        RECT  0 72.288 0.084 72.312 ;
    END
  END r_val_a[13]
  PIN r_val_a[14]
    DIRECTION INPUT ;
    USE SIGNAL ;
    PORT
      LAYER M4 ;
        RECT  0 72.48 0.084 72.504 ;
    END
  END r_val_a[14]
  PIN r_val_a[15]
    DIRECTION INPUT ;
    USE SIGNAL ;
    PORT
      LAYER M4 ;
        RECT  0 72.672 0.084 72.696 ;
    END
  END r_val_a[15]
  PIN r_val_a[16]
    DIRECTION INPUT ;
    USE SIGNAL ;
    PORT
      LAYER M4 ;
        RECT  0 72.864 0.084 72.888 ;
    END
  END r_val_a[16]
  PIN r_val_a[17]
    DIRECTION INPUT ;
    USE SIGNAL ;
    PORT
      LAYER M4 ;
        RECT  0 73.056 0.084 73.08 ;
    END
  END r_val_a[17]
  PIN r_val_a[18]
    DIRECTION INPUT ;
    USE SIGNAL ;
    PORT
      LAYER M4 ;
        RECT  0 73.248 0.084 73.272 ;
    END
  END r_val_a[18]
  PIN r_val_a[19]
    DIRECTION INPUT ;
    USE SIGNAL ;
    PORT
      LAYER M4 ;
        RECT  0 73.44 0.084 73.464 ;
    END
  END r_val_a[19]
  PIN r_val_a[1]
    DIRECTION INPUT ;
    USE SIGNAL ;
    PORT
      LAYER M4 ;
        RECT  0 69.984 0.084 70.008 ;
    END
  END r_val_a[1]
  PIN r_val_a[20]
    DIRECTION INPUT ;
    USE SIGNAL ;
    PORT
      LAYER M4 ;
        RECT  0 73.632 0.084 73.656 ;
    END
  END r_val_a[20]
  PIN r_val_a[21]
    DIRECTION INPUT ;
    USE SIGNAL ;
    PORT
      LAYER M4 ;
        RECT  0 73.824 0.084 73.848 ;
    END
  END r_val_a[21]
  PIN r_val_a[22]
    DIRECTION INPUT ;
    USE SIGNAL ;
    PORT
      LAYER M4 ;
        RECT  0 74.016 0.084 74.04 ;
    END
  END r_val_a[22]
  PIN r_val_a[23]
    DIRECTION INPUT ;
    USE SIGNAL ;
    PORT
      LAYER M4 ;
        RECT  0 74.208 0.084 74.232 ;
    END
  END r_val_a[23]
  PIN r_val_a[24]
    DIRECTION INPUT ;
    USE SIGNAL ;
    PORT
      LAYER M4 ;
        RECT  0 74.4 0.084 74.424 ;
    END
  END r_val_a[24]
  PIN r_val_a[25]
    DIRECTION INPUT ;
    USE SIGNAL ;
    PORT
      LAYER M4 ;
        RECT  0 74.592 0.084 74.616 ;
    END
  END r_val_a[25]
  PIN r_val_a[26]
    DIRECTION INPUT ;
    USE SIGNAL ;
    PORT
      LAYER M4 ;
        RECT  0 74.784 0.084 74.808 ;
    END
  END r_val_a[26]
  PIN r_val_a[27]
    DIRECTION INPUT ;
    USE SIGNAL ;
    PORT
      LAYER M4 ;
        RECT  0 74.976 0.084 75 ;
    END
  END r_val_a[27]
  PIN r_val_a[28]
    DIRECTION INPUT ;
    USE SIGNAL ;
    PORT
      LAYER M4 ;
        RECT  0 75.168 0.084 75.192 ;
    END
  END r_val_a[28]
  PIN r_val_a[29]
    DIRECTION INPUT ;
    USE SIGNAL ;
    PORT
      LAYER M4 ;
        RECT  0 75.36 0.084 75.384 ;
    END
  END r_val_a[29]
  PIN r_val_a[2]
    DIRECTION INPUT ;
    USE SIGNAL ;
    PORT
      LAYER M4 ;
        RECT  0 70.176 0.084 70.2 ;
    END
  END r_val_a[2]
  PIN r_val_a[30]
    DIRECTION INPUT ;
    USE SIGNAL ;
    PORT
      LAYER M4 ;
        RECT  0 75.552 0.084 75.576 ;
    END
  END r_val_a[30]
  PIN r_val_a[31]
    DIRECTION INPUT ;
    USE SIGNAL ;
    PORT
      LAYER M4 ;
        RECT  0 75.744 0.084 75.768 ;
    END
  END r_val_a[31]
  PIN r_val_a[3]
    DIRECTION INPUT ;
    USE SIGNAL ;
    PORT
      LAYER M4 ;
        RECT  0 70.368 0.084 70.392 ;
    END
  END r_val_a[3]
  PIN r_val_a[4]
    DIRECTION INPUT ;
    USE SIGNAL ;
    PORT
      LAYER M4 ;
        RECT  0 70.56 0.084 70.584 ;
    END
  END r_val_a[4]
  PIN r_val_a[5]
    DIRECTION INPUT ;
    USE SIGNAL ;
    PORT
      LAYER M4 ;
        RECT  0 70.752 0.084 70.776 ;
    END
  END r_val_a[5]
  PIN r_val_a[6]
    DIRECTION INPUT ;
    USE SIGNAL ;
    PORT
      LAYER M4 ;
        RECT  0 70.944 0.084 70.968 ;
    END
  END r_val_a[6]
  PIN r_val_a[7]
    DIRECTION INPUT ;
    USE SIGNAL ;
    PORT
      LAYER M4 ;
        RECT  0 71.136 0.084 71.16 ;
    END
  END r_val_a[7]
  PIN r_val_a[8]
    DIRECTION INPUT ;
    USE SIGNAL ;
    PORT
      LAYER M4 ;
        RECT  0 71.328 0.084 71.352 ;
    END
  END r_val_a[8]
  PIN r_val_a[9]
    DIRECTION INPUT ;
    USE SIGNAL ;
    PORT
      LAYER M4 ;
        RECT  0 71.52 0.084 71.544 ;
    END
  END r_val_a[9]
  PIN r_val_b[0]
    DIRECTION INPUT ;
    USE SIGNAL ;
    PORT
      LAYER M4 ;
        RECT  0 173.472 0.084 173.496 ;
    END
  END r_val_b[0]
  PIN r_val_b[10]
    DIRECTION INPUT ;
    USE SIGNAL ;
    PORT
      LAYER M4 ;
        RECT  0 175.392 0.084 175.416 ;
    END
  END r_val_b[10]
  PIN r_val_b[11]
    DIRECTION INPUT ;
    USE SIGNAL ;
    PORT
      LAYER M4 ;
        RECT  0 175.584 0.084 175.608 ;
    END
  END r_val_b[11]
  PIN r_val_b[12]
    DIRECTION INPUT ;
    USE SIGNAL ;
    PORT
      LAYER M4 ;
        RECT  0 175.776 0.084 175.8 ;
    END
  END r_val_b[12]
  PIN r_val_b[13]
    DIRECTION INPUT ;
    USE SIGNAL ;
    PORT
      LAYER M4 ;
        RECT  0 175.968 0.084 175.992 ;
    END
  END r_val_b[13]
  PIN r_val_b[14]
    DIRECTION INPUT ;
    USE SIGNAL ;
    PORT
      LAYER M4 ;
        RECT  0 176.16 0.084 176.184 ;
    END
  END r_val_b[14]
  PIN r_val_b[15]
    DIRECTION INPUT ;
    USE SIGNAL ;
    PORT
      LAYER M4 ;
        RECT  0 176.352 0.084 176.376 ;
    END
  END r_val_b[15]
  PIN r_val_b[16]
    DIRECTION INPUT ;
    USE SIGNAL ;
    PORT
      LAYER M4 ;
        RECT  0 176.544 0.084 176.568 ;
    END
  END r_val_b[16]
  PIN r_val_b[17]
    DIRECTION INPUT ;
    USE SIGNAL ;
    PORT
      LAYER M4 ;
        RECT  0 176.736 0.084 176.76 ;
    END
  END r_val_b[17]
  PIN r_val_b[18]
    DIRECTION INPUT ;
    USE SIGNAL ;
    PORT
      LAYER M4 ;
        RECT  0 176.928 0.084 176.952 ;
    END
  END r_val_b[18]
  PIN r_val_b[19]
    DIRECTION INPUT ;
    USE SIGNAL ;
    PORT
      LAYER M4 ;
        RECT  0 177.12 0.084 177.144 ;
    END
  END r_val_b[19]
  PIN r_val_b[1]
    DIRECTION INPUT ;
    USE SIGNAL ;
    PORT
      LAYER M4 ;
        RECT  0 173.664 0.084 173.688 ;
    END
  END r_val_b[1]
  PIN r_val_b[20]
    DIRECTION INPUT ;
    USE SIGNAL ;
    PORT
      LAYER M4 ;
        RECT  0 177.312 0.084 177.336 ;
    END
  END r_val_b[20]
  PIN r_val_b[21]
    DIRECTION INPUT ;
    USE SIGNAL ;
    PORT
      LAYER M4 ;
        RECT  0 177.504 0.084 177.528 ;
    END
  END r_val_b[21]
  PIN r_val_b[22]
    DIRECTION INPUT ;
    USE SIGNAL ;
    PORT
      LAYER M4 ;
        RECT  0 177.696 0.084 177.72 ;
    END
  END r_val_b[22]
  PIN r_val_b[23]
    DIRECTION INPUT ;
    USE SIGNAL ;
    PORT
      LAYER M4 ;
        RECT  0 177.888 0.084 177.912 ;
    END
  END r_val_b[23]
  PIN r_val_b[24]
    DIRECTION INPUT ;
    USE SIGNAL ;
    PORT
      LAYER M4 ;
        RECT  0 178.08 0.084 178.104 ;
    END
  END r_val_b[24]
  PIN r_val_b[25]
    DIRECTION INPUT ;
    USE SIGNAL ;
    PORT
      LAYER M4 ;
        RECT  0 178.272 0.084 178.296 ;
    END
  END r_val_b[25]
  PIN r_val_b[26]
    DIRECTION INPUT ;
    USE SIGNAL ;
    PORT
      LAYER M4 ;
        RECT  0 178.464 0.084 178.488 ;
    END
  END r_val_b[26]
  PIN r_val_b[27]
    DIRECTION INPUT ;
    USE SIGNAL ;
    PORT
      LAYER M4 ;
        RECT  0 178.656 0.084 178.68 ;
    END
  END r_val_b[27]
  PIN r_val_b[28]
    DIRECTION INPUT ;
    USE SIGNAL ;
    PORT
      LAYER M4 ;
        RECT  0 178.848 0.084 178.872 ;
    END
  END r_val_b[28]
  PIN r_val_b[29]
    DIRECTION INPUT ;
    USE SIGNAL ;
    PORT
      LAYER M4 ;
        RECT  0 179.04 0.084 179.064 ;
    END
  END r_val_b[29]
  PIN r_val_b[2]
    DIRECTION INPUT ;
    USE SIGNAL ;
    PORT
      LAYER M4 ;
        RECT  0 173.856 0.084 173.88 ;
    END
  END r_val_b[2]
  PIN r_val_b[30]
    DIRECTION INPUT ;
    USE SIGNAL ;
    PORT
      LAYER M4 ;
        RECT  0 179.232 0.084 179.256 ;
    END
  END r_val_b[30]
  PIN r_val_b[31]
    DIRECTION INPUT ;
    USE SIGNAL ;
    PORT
      LAYER M4 ;
        RECT  0 179.424 0.084 179.448 ;
    END
  END r_val_b[31]
  PIN r_val_b[3]
    DIRECTION INPUT ;
    USE SIGNAL ;
    PORT
      LAYER M4 ;
        RECT  0 174.048 0.084 174.072 ;
    END
  END r_val_b[3]
  PIN r_val_b[4]
    DIRECTION INPUT ;
    USE SIGNAL ;
    PORT
      LAYER M4 ;
        RECT  0 174.24 0.084 174.264 ;
    END
  END r_val_b[4]
  PIN r_val_b[5]
    DIRECTION INPUT ;
    USE SIGNAL ;
    PORT
      LAYER M4 ;
        RECT  0 174.432 0.084 174.456 ;
    END
  END r_val_b[5]
  PIN r_val_b[6]
    DIRECTION INPUT ;
    USE SIGNAL ;
    PORT
      LAYER M4 ;
        RECT  0 174.624 0.084 174.648 ;
    END
  END r_val_b[6]
  PIN r_val_b[7]
    DIRECTION INPUT ;
    USE SIGNAL ;
    PORT
      LAYER M4 ;
        RECT  0 174.816 0.084 174.84 ;
    END
  END r_val_b[7]
  PIN r_val_b[8]
    DIRECTION INPUT ;
    USE SIGNAL ;
    PORT
      LAYER M4 ;
        RECT  0 175.008 0.084 175.032 ;
    END
  END r_val_b[8]
  PIN r_val_b[9]
    DIRECTION INPUT ;
    USE SIGNAL ;
    PORT
      LAYER M4 ;
        RECT  0 175.2 0.084 175.224 ;
    END
  END r_val_b[9]
  PIN rst_n_pin
    DIRECTION INPUT ;
    USE SIGNAL ;
    PORT
      LAYER M4 ;
        RECT  208.164 116.448 208.248 116.472 ;
    END
  END rst_n_pin
  PIN so_idx[0]
    DIRECTION INPUT ;
    USE SIGNAL ;
    PORT
      LAYER M4 ;
        RECT  208.164 116.544 208.248 116.568 ;
    END
  END so_idx[0]
  PIN so_idx[10]
    DIRECTION INPUT ;
    USE SIGNAL ;
    PORT
      LAYER M4 ;
        RECT  208.164 117.504 208.248 117.528 ;
    END
  END so_idx[10]
  PIN so_idx[11]
    DIRECTION INPUT ;
    USE SIGNAL ;
    PORT
      LAYER M4 ;
        RECT  208.164 117.6 208.248 117.624 ;
    END
  END so_idx[11]
  PIN so_idx[12]
    DIRECTION INPUT ;
    USE SIGNAL ;
    PORT
      LAYER M4 ;
        RECT  208.164 117.696 208.248 117.72 ;
    END
  END so_idx[12]
  PIN so_idx[13]
    DIRECTION INPUT ;
    USE SIGNAL ;
    PORT
      LAYER M4 ;
        RECT  208.164 117.792 208.248 117.816 ;
    END
  END so_idx[13]
  PIN so_idx[14]
    DIRECTION INPUT ;
    USE SIGNAL ;
    PORT
      LAYER M4 ;
        RECT  208.164 117.888 208.248 117.912 ;
    END
  END so_idx[14]
  PIN so_idx[15]
    DIRECTION INPUT ;
    USE SIGNAL ;
    PORT
      LAYER M4 ;
        RECT  208.164 117.984 208.248 118.008 ;
    END
  END so_idx[15]
  PIN so_idx[16]
    DIRECTION INPUT ;
    USE SIGNAL ;
    PORT
      LAYER M4 ;
        RECT  208.164 118.08 208.248 118.104 ;
    END
  END so_idx[16]
  PIN so_idx[17]
    DIRECTION INPUT ;
    USE SIGNAL ;
    PORT
      LAYER M4 ;
        RECT  208.164 118.176 208.248 118.2 ;
    END
  END so_idx[17]
  PIN so_idx[18]
    DIRECTION INPUT ;
    USE SIGNAL ;
    PORT
      LAYER M4 ;
        RECT  208.164 118.272 208.248 118.296 ;
    END
  END so_idx[18]
  PIN so_idx[19]
    DIRECTION INPUT ;
    USE SIGNAL ;
    PORT
      LAYER M4 ;
        RECT  208.164 118.368 208.248 118.392 ;
    END
  END so_idx[19]
  PIN so_idx[1]
    DIRECTION INPUT ;
    USE SIGNAL ;
    PORT
      LAYER M4 ;
        RECT  208.164 116.64 208.248 116.664 ;
    END
  END so_idx[1]
  PIN so_idx[20]
    DIRECTION INPUT ;
    USE SIGNAL ;
    PORT
      LAYER M4 ;
        RECT  208.164 118.464 208.248 118.488 ;
    END
  END so_idx[20]
  PIN so_idx[21]
    DIRECTION INPUT ;
    USE SIGNAL ;
    PORT
      LAYER M4 ;
        RECT  208.164 118.56 208.248 118.584 ;
    END
  END so_idx[21]
  PIN so_idx[22]
    DIRECTION INPUT ;
    USE SIGNAL ;
    PORT
      LAYER M4 ;
        RECT  208.164 118.656 208.248 118.68 ;
    END
  END so_idx[22]
  PIN so_idx[23]
    DIRECTION INPUT ;
    USE SIGNAL ;
    PORT
      LAYER M4 ;
        RECT  208.164 118.752 208.248 118.776 ;
    END
  END so_idx[23]
  PIN so_idx[24]
    DIRECTION INPUT ;
    USE SIGNAL ;
    PORT
      LAYER M4 ;
        RECT  208.164 118.848 208.248 118.872 ;
    END
  END so_idx[24]
  PIN so_idx[25]
    DIRECTION INPUT ;
    USE SIGNAL ;
    PORT
      LAYER M4 ;
        RECT  208.164 118.944 208.248 118.968 ;
    END
  END so_idx[25]
  PIN so_idx[26]
    DIRECTION INPUT ;
    USE SIGNAL ;
    PORT
      LAYER M4 ;
        RECT  208.164 119.04 208.248 119.064 ;
    END
  END so_idx[26]
  PIN so_idx[27]
    DIRECTION INPUT ;
    USE SIGNAL ;
    PORT
      LAYER M4 ;
        RECT  208.164 119.136 208.248 119.16 ;
    END
  END so_idx[27]
  PIN so_idx[28]
    DIRECTION INPUT ;
    USE SIGNAL ;
    PORT
      LAYER M4 ;
        RECT  208.164 119.232 208.248 119.256 ;
    END
  END so_idx[28]
  PIN so_idx[29]
    DIRECTION INPUT ;
    USE SIGNAL ;
    PORT
      LAYER M4 ;
        RECT  208.164 119.328 208.248 119.352 ;
    END
  END so_idx[29]
  PIN so_idx[2]
    DIRECTION INPUT ;
    USE SIGNAL ;
    PORT
      LAYER M4 ;
        RECT  208.164 116.736 208.248 116.76 ;
    END
  END so_idx[2]
  PIN so_idx[30]
    DIRECTION INPUT ;
    USE SIGNAL ;
    PORT
      LAYER M4 ;
        RECT  208.164 119.424 208.248 119.448 ;
    END
  END so_idx[30]
  PIN so_idx[31]
    DIRECTION INPUT ;
    USE SIGNAL ;
    PORT
      LAYER M4 ;
        RECT  208.164 119.52 208.248 119.544 ;
    END
  END so_idx[31]
  PIN so_idx[32]
    DIRECTION INPUT ;
    USE SIGNAL ;
    PORT
      LAYER M4 ;
        RECT  208.164 119.616 208.248 119.64 ;
    END
  END so_idx[32]
  PIN so_idx[33]
    DIRECTION INPUT ;
    USE SIGNAL ;
    PORT
      LAYER M4 ;
        RECT  208.164 119.712 208.248 119.736 ;
    END
  END so_idx[33]
  PIN so_idx[34]
    DIRECTION INPUT ;
    USE SIGNAL ;
    PORT
      LAYER M4 ;
        RECT  208.164 119.808 208.248 119.832 ;
    END
  END so_idx[34]
  PIN so_idx[35]
    DIRECTION INPUT ;
    USE SIGNAL ;
    PORT
      LAYER M4 ;
        RECT  208.164 119.904 208.248 119.928 ;
    END
  END so_idx[35]
  PIN so_idx[36]
    DIRECTION INPUT ;
    USE SIGNAL ;
    PORT
      LAYER M4 ;
        RECT  208.164 120 208.248 120.024 ;
    END
  END so_idx[36]
  PIN so_idx[37]
    DIRECTION INPUT ;
    USE SIGNAL ;
    PORT
      LAYER M4 ;
        RECT  208.164 120.096 208.248 120.12 ;
    END
  END so_idx[37]
  PIN so_idx[38]
    DIRECTION INPUT ;
    USE SIGNAL ;
    PORT
      LAYER M4 ;
        RECT  208.164 120.192 208.248 120.216 ;
    END
  END so_idx[38]
  PIN so_idx[39]
    DIRECTION INPUT ;
    USE SIGNAL ;
    PORT
      LAYER M4 ;
        RECT  208.164 120.288 208.248 120.312 ;
    END
  END so_idx[39]
  PIN so_idx[3]
    DIRECTION INPUT ;
    USE SIGNAL ;
    PORT
      LAYER M4 ;
        RECT  208.164 116.832 208.248 116.856 ;
    END
  END so_idx[3]
  PIN so_idx[4]
    DIRECTION INPUT ;
    USE SIGNAL ;
    PORT
      LAYER M4 ;
        RECT  208.164 116.928 208.248 116.952 ;
    END
  END so_idx[4]
  PIN so_idx[5]
    DIRECTION INPUT ;
    USE SIGNAL ;
    PORT
      LAYER M4 ;
        RECT  208.164 117.024 208.248 117.048 ;
    END
  END so_idx[5]
  PIN so_idx[6]
    DIRECTION INPUT ;
    USE SIGNAL ;
    PORT
      LAYER M4 ;
        RECT  208.164 117.12 208.248 117.144 ;
    END
  END so_idx[6]
  PIN so_idx[7]
    DIRECTION INPUT ;
    USE SIGNAL ;
    PORT
      LAYER M4 ;
        RECT  208.164 117.216 208.248 117.24 ;
    END
  END so_idx[7]
  PIN so_idx[8]
    DIRECTION INPUT ;
    USE SIGNAL ;
    PORT
      LAYER M4 ;
        RECT  208.164 117.312 208.248 117.336 ;
    END
  END so_idx[8]
  PIN so_idx[9]
    DIRECTION INPUT ;
    USE SIGNAL ;
    PORT
      LAYER M4 ;
        RECT  208.164 117.408 208.248 117.432 ;
    END
  END so_idx[9]
  PIN so_n[0]
    DIRECTION INPUT ;
    USE SIGNAL ;
    PORT
      LAYER M4 ;
        RECT  208.164 120.384 208.248 120.408 ;
    END
  END so_n[0]
  PIN so_n[10]
    DIRECTION INPUT ;
    USE SIGNAL ;
    PORT
      LAYER M4 ;
        RECT  208.164 121.344 208.248 121.368 ;
    END
  END so_n[10]
  PIN so_n[11]
    DIRECTION INPUT ;
    USE SIGNAL ;
    PORT
      LAYER M4 ;
        RECT  208.164 121.44 208.248 121.464 ;
    END
  END so_n[11]
  PIN so_n[12]
    DIRECTION INPUT ;
    USE SIGNAL ;
    PORT
      LAYER M4 ;
        RECT  208.164 121.536 208.248 121.56 ;
    END
  END so_n[12]
  PIN so_n[13]
    DIRECTION INPUT ;
    USE SIGNAL ;
    PORT
      LAYER M4 ;
        RECT  208.164 121.632 208.248 121.656 ;
    END
  END so_n[13]
  PIN so_n[14]
    DIRECTION INPUT ;
    USE SIGNAL ;
    PORT
      LAYER M4 ;
        RECT  208.164 121.728 208.248 121.752 ;
    END
  END so_n[14]
  PIN so_n[15]
    DIRECTION INPUT ;
    USE SIGNAL ;
    PORT
      LAYER M4 ;
        RECT  208.164 121.824 208.248 121.848 ;
    END
  END so_n[15]
  PIN so_n[16]
    DIRECTION INPUT ;
    USE SIGNAL ;
    PORT
      LAYER M4 ;
        RECT  208.164 121.92 208.248 121.944 ;
    END
  END so_n[16]
  PIN so_n[17]
    DIRECTION INPUT ;
    USE SIGNAL ;
    PORT
      LAYER M4 ;
        RECT  208.164 122.016 208.248 122.04 ;
    END
  END so_n[17]
  PIN so_n[18]
    DIRECTION INPUT ;
    USE SIGNAL ;
    PORT
      LAYER M4 ;
        RECT  208.164 122.112 208.248 122.136 ;
    END
  END so_n[18]
  PIN so_n[19]
    DIRECTION INPUT ;
    USE SIGNAL ;
    PORT
      LAYER M4 ;
        RECT  208.164 122.208 208.248 122.232 ;
    END
  END so_n[19]
  PIN so_n[1]
    DIRECTION INPUT ;
    USE SIGNAL ;
    PORT
      LAYER M4 ;
        RECT  208.164 120.48 208.248 120.504 ;
    END
  END so_n[1]
  PIN so_n[20]
    DIRECTION INPUT ;
    USE SIGNAL ;
    PORT
      LAYER M4 ;
        RECT  208.164 122.304 208.248 122.328 ;
    END
  END so_n[20]
  PIN so_n[21]
    DIRECTION INPUT ;
    USE SIGNAL ;
    PORT
      LAYER M4 ;
        RECT  208.164 122.4 208.248 122.424 ;
    END
  END so_n[21]
  PIN so_n[22]
    DIRECTION INPUT ;
    USE SIGNAL ;
    PORT
      LAYER M4 ;
        RECT  208.164 122.496 208.248 122.52 ;
    END
  END so_n[22]
  PIN so_n[23]
    DIRECTION INPUT ;
    USE SIGNAL ;
    PORT
      LAYER M4 ;
        RECT  208.164 122.592 208.248 122.616 ;
    END
  END so_n[23]
  PIN so_n[24]
    DIRECTION INPUT ;
    USE SIGNAL ;
    PORT
      LAYER M4 ;
        RECT  208.164 122.688 208.248 122.712 ;
    END
  END so_n[24]
  PIN so_n[25]
    DIRECTION INPUT ;
    USE SIGNAL ;
    PORT
      LAYER M4 ;
        RECT  208.164 122.784 208.248 122.808 ;
    END
  END so_n[25]
  PIN so_n[26]
    DIRECTION INPUT ;
    USE SIGNAL ;
    PORT
      LAYER M4 ;
        RECT  208.164 122.88 208.248 122.904 ;
    END
  END so_n[26]
  PIN so_n[27]
    DIRECTION INPUT ;
    USE SIGNAL ;
    PORT
      LAYER M4 ;
        RECT  208.164 122.976 208.248 123 ;
    END
  END so_n[27]
  PIN so_n[28]
    DIRECTION INPUT ;
    USE SIGNAL ;
    PORT
      LAYER M4 ;
        RECT  208.164 123.072 208.248 123.096 ;
    END
  END so_n[28]
  PIN so_n[29]
    DIRECTION INPUT ;
    USE SIGNAL ;
    PORT
      LAYER M4 ;
        RECT  208.164 123.168 208.248 123.192 ;
    END
  END so_n[29]
  PIN so_n[2]
    DIRECTION INPUT ;
    USE SIGNAL ;
    PORT
      LAYER M4 ;
        RECT  208.164 120.576 208.248 120.6 ;
    END
  END so_n[2]
  PIN so_n[30]
    DIRECTION INPUT ;
    USE SIGNAL ;
    PORT
      LAYER M4 ;
        RECT  208.164 123.264 208.248 123.288 ;
    END
  END so_n[30]
  PIN so_n[31]
    DIRECTION INPUT ;
    USE SIGNAL ;
    PORT
      LAYER M4 ;
        RECT  208.164 123.36 208.248 123.384 ;
    END
  END so_n[31]
  PIN so_n[32]
    DIRECTION INPUT ;
    USE SIGNAL ;
    PORT
      LAYER M4 ;
        RECT  208.164 123.456 208.248 123.48 ;
    END
  END so_n[32]
  PIN so_n[33]
    DIRECTION INPUT ;
    USE SIGNAL ;
    PORT
      LAYER M4 ;
        RECT  208.164 123.552 208.248 123.576 ;
    END
  END so_n[33]
  PIN so_n[34]
    DIRECTION INPUT ;
    USE SIGNAL ;
    PORT
      LAYER M4 ;
        RECT  208.164 123.648 208.248 123.672 ;
    END
  END so_n[34]
  PIN so_n[35]
    DIRECTION INPUT ;
    USE SIGNAL ;
    PORT
      LAYER M4 ;
        RECT  208.164 123.744 208.248 123.768 ;
    END
  END so_n[35]
  PIN so_n[36]
    DIRECTION INPUT ;
    USE SIGNAL ;
    PORT
      LAYER M4 ;
        RECT  208.164 123.84 208.248 123.864 ;
    END
  END so_n[36]
  PIN so_n[37]
    DIRECTION INPUT ;
    USE SIGNAL ;
    PORT
      LAYER M4 ;
        RECT  208.164 123.936 208.248 123.96 ;
    END
  END so_n[37]
  PIN so_n[38]
    DIRECTION INPUT ;
    USE SIGNAL ;
    PORT
      LAYER M4 ;
        RECT  208.164 124.032 208.248 124.056 ;
    END
  END so_n[38]
  PIN so_n[39]
    DIRECTION INPUT ;
    USE SIGNAL ;
    PORT
      LAYER M4 ;
        RECT  208.164 124.128 208.248 124.152 ;
    END
  END so_n[39]
  PIN so_n[3]
    DIRECTION INPUT ;
    USE SIGNAL ;
    PORT
      LAYER M4 ;
        RECT  208.164 120.672 208.248 120.696 ;
    END
  END so_n[3]
  PIN so_n[4]
    DIRECTION INPUT ;
    USE SIGNAL ;
    PORT
      LAYER M4 ;
        RECT  208.164 120.768 208.248 120.792 ;
    END
  END so_n[4]
  PIN so_n[5]
    DIRECTION INPUT ;
    USE SIGNAL ;
    PORT
      LAYER M4 ;
        RECT  208.164 120.864 208.248 120.888 ;
    END
  END so_n[5]
  PIN so_n[6]
    DIRECTION INPUT ;
    USE SIGNAL ;
    PORT
      LAYER M4 ;
        RECT  208.164 120.96 208.248 120.984 ;
    END
  END so_n[6]
  PIN so_n[7]
    DIRECTION INPUT ;
    USE SIGNAL ;
    PORT
      LAYER M4 ;
        RECT  208.164 121.056 208.248 121.08 ;
    END
  END so_n[7]
  PIN so_n[8]
    DIRECTION INPUT ;
    USE SIGNAL ;
    PORT
      LAYER M4 ;
        RECT  208.164 121.152 208.248 121.176 ;
    END
  END so_n[8]
  PIN so_n[9]
    DIRECTION INPUT ;
    USE SIGNAL ;
    PORT
      LAYER M4 ;
        RECT  208.164 121.248 208.248 121.272 ;
    END
  END so_n[9]
  PIN so_row[0]
    DIRECTION INPUT ;
    USE SIGNAL ;
    PORT
      LAYER M4 ;
        RECT  208.164 124.224 208.248 124.248 ;
    END
  END so_row[0]
  PIN so_row[100]
    DIRECTION INPUT ;
    USE SIGNAL ;
    PORT
      LAYER M4 ;
        RECT  208.164 133.824 208.248 133.848 ;
    END
  END so_row[100]
  PIN so_row[101]
    DIRECTION INPUT ;
    USE SIGNAL ;
    PORT
      LAYER M4 ;
        RECT  208.164 133.92 208.248 133.944 ;
    END
  END so_row[101]
  PIN so_row[102]
    DIRECTION INPUT ;
    USE SIGNAL ;
    PORT
      LAYER M4 ;
        RECT  208.164 134.016 208.248 134.04 ;
    END
  END so_row[102]
  PIN so_row[103]
    DIRECTION INPUT ;
    USE SIGNAL ;
    PORT
      LAYER M4 ;
        RECT  208.164 134.112 208.248 134.136 ;
    END
  END so_row[103]
  PIN so_row[104]
    DIRECTION INPUT ;
    USE SIGNAL ;
    PORT
      LAYER M4 ;
        RECT  208.164 134.208 208.248 134.232 ;
    END
  END so_row[104]
  PIN so_row[105]
    DIRECTION INPUT ;
    USE SIGNAL ;
    PORT
      LAYER M4 ;
        RECT  208.164 134.304 208.248 134.328 ;
    END
  END so_row[105]
  PIN so_row[106]
    DIRECTION INPUT ;
    USE SIGNAL ;
    PORT
      LAYER M4 ;
        RECT  208.164 134.4 208.248 134.424 ;
    END
  END so_row[106]
  PIN so_row[107]
    DIRECTION INPUT ;
    USE SIGNAL ;
    PORT
      LAYER M4 ;
        RECT  208.164 134.496 208.248 134.52 ;
    END
  END so_row[107]
  PIN so_row[108]
    DIRECTION INPUT ;
    USE SIGNAL ;
    PORT
      LAYER M4 ;
        RECT  208.164 134.592 208.248 134.616 ;
    END
  END so_row[108]
  PIN so_row[109]
    DIRECTION INPUT ;
    USE SIGNAL ;
    PORT
      LAYER M4 ;
        RECT  208.164 134.688 208.248 134.712 ;
    END
  END so_row[109]
  PIN so_row[10]
    DIRECTION INPUT ;
    USE SIGNAL ;
    PORT
      LAYER M4 ;
        RECT  208.164 125.184 208.248 125.208 ;
    END
  END so_row[10]
  PIN so_row[110]
    DIRECTION INPUT ;
    USE SIGNAL ;
    PORT
      LAYER M4 ;
        RECT  208.164 134.784 208.248 134.808 ;
    END
  END so_row[110]
  PIN so_row[111]
    DIRECTION INPUT ;
    USE SIGNAL ;
    PORT
      LAYER M4 ;
        RECT  208.164 134.88 208.248 134.904 ;
    END
  END so_row[111]
  PIN so_row[112]
    DIRECTION INPUT ;
    USE SIGNAL ;
    PORT
      LAYER M4 ;
        RECT  208.164 134.976 208.248 135 ;
    END
  END so_row[112]
  PIN so_row[113]
    DIRECTION INPUT ;
    USE SIGNAL ;
    PORT
      LAYER M4 ;
        RECT  208.164 135.072 208.248 135.096 ;
    END
  END so_row[113]
  PIN so_row[114]
    DIRECTION INPUT ;
    USE SIGNAL ;
    PORT
      LAYER M4 ;
        RECT  208.164 135.168 208.248 135.192 ;
    END
  END so_row[114]
  PIN so_row[115]
    DIRECTION INPUT ;
    USE SIGNAL ;
    PORT
      LAYER M4 ;
        RECT  208.164 135.264 208.248 135.288 ;
    END
  END so_row[115]
  PIN so_row[116]
    DIRECTION INPUT ;
    USE SIGNAL ;
    PORT
      LAYER M4 ;
        RECT  208.164 135.36 208.248 135.384 ;
    END
  END so_row[116]
  PIN so_row[117]
    DIRECTION INPUT ;
    USE SIGNAL ;
    PORT
      LAYER M4 ;
        RECT  208.164 135.456 208.248 135.48 ;
    END
  END so_row[117]
  PIN so_row[118]
    DIRECTION INPUT ;
    USE SIGNAL ;
    PORT
      LAYER M4 ;
        RECT  208.164 135.552 208.248 135.576 ;
    END
  END so_row[118]
  PIN so_row[119]
    DIRECTION INPUT ;
    USE SIGNAL ;
    PORT
      LAYER M4 ;
        RECT  208.164 135.648 208.248 135.672 ;
    END
  END so_row[119]
  PIN so_row[11]
    DIRECTION INPUT ;
    USE SIGNAL ;
    PORT
      LAYER M4 ;
        RECT  208.164 125.28 208.248 125.304 ;
    END
  END so_row[11]
  PIN so_row[120]
    DIRECTION INPUT ;
    USE SIGNAL ;
    PORT
      LAYER M4 ;
        RECT  208.164 135.744 208.248 135.768 ;
    END
  END so_row[120]
  PIN so_row[121]
    DIRECTION INPUT ;
    USE SIGNAL ;
    PORT
      LAYER M4 ;
        RECT  208.164 135.84 208.248 135.864 ;
    END
  END so_row[121]
  PIN so_row[122]
    DIRECTION INPUT ;
    USE SIGNAL ;
    PORT
      LAYER M4 ;
        RECT  208.164 135.936 208.248 135.96 ;
    END
  END so_row[122]
  PIN so_row[123]
    DIRECTION INPUT ;
    USE SIGNAL ;
    PORT
      LAYER M4 ;
        RECT  208.164 136.032 208.248 136.056 ;
    END
  END so_row[123]
  PIN so_row[124]
    DIRECTION INPUT ;
    USE SIGNAL ;
    PORT
      LAYER M4 ;
        RECT  208.164 136.128 208.248 136.152 ;
    END
  END so_row[124]
  PIN so_row[125]
    DIRECTION INPUT ;
    USE SIGNAL ;
    PORT
      LAYER M4 ;
        RECT  208.164 136.224 208.248 136.248 ;
    END
  END so_row[125]
  PIN so_row[126]
    DIRECTION INPUT ;
    USE SIGNAL ;
    PORT
      LAYER M4 ;
        RECT  208.164 136.32 208.248 136.344 ;
    END
  END so_row[126]
  PIN so_row[127]
    DIRECTION INPUT ;
    USE SIGNAL ;
    PORT
      LAYER M4 ;
        RECT  208.164 136.416 208.248 136.44 ;
    END
  END so_row[127]
  PIN so_row[12]
    DIRECTION INPUT ;
    USE SIGNAL ;
    PORT
      LAYER M4 ;
        RECT  208.164 125.376 208.248 125.4 ;
    END
  END so_row[12]
  PIN so_row[13]
    DIRECTION INPUT ;
    USE SIGNAL ;
    PORT
      LAYER M4 ;
        RECT  208.164 125.472 208.248 125.496 ;
    END
  END so_row[13]
  PIN so_row[14]
    DIRECTION INPUT ;
    USE SIGNAL ;
    PORT
      LAYER M4 ;
        RECT  208.164 125.568 208.248 125.592 ;
    END
  END so_row[14]
  PIN so_row[15]
    DIRECTION INPUT ;
    USE SIGNAL ;
    PORT
      LAYER M4 ;
        RECT  208.164 125.664 208.248 125.688 ;
    END
  END so_row[15]
  PIN so_row[16]
    DIRECTION INPUT ;
    USE SIGNAL ;
    PORT
      LAYER M4 ;
        RECT  208.164 125.76 208.248 125.784 ;
    END
  END so_row[16]
  PIN so_row[17]
    DIRECTION INPUT ;
    USE SIGNAL ;
    PORT
      LAYER M4 ;
        RECT  208.164 125.856 208.248 125.88 ;
    END
  END so_row[17]
  PIN so_row[18]
    DIRECTION INPUT ;
    USE SIGNAL ;
    PORT
      LAYER M4 ;
        RECT  208.164 125.952 208.248 125.976 ;
    END
  END so_row[18]
  PIN so_row[19]
    DIRECTION INPUT ;
    USE SIGNAL ;
    PORT
      LAYER M4 ;
        RECT  208.164 126.048 208.248 126.072 ;
    END
  END so_row[19]
  PIN so_row[1]
    DIRECTION INPUT ;
    USE SIGNAL ;
    PORT
      LAYER M4 ;
        RECT  208.164 124.32 208.248 124.344 ;
    END
  END so_row[1]
  PIN so_row[20]
    DIRECTION INPUT ;
    USE SIGNAL ;
    PORT
      LAYER M4 ;
        RECT  208.164 126.144 208.248 126.168 ;
    END
  END so_row[20]
  PIN so_row[21]
    DIRECTION INPUT ;
    USE SIGNAL ;
    PORT
      LAYER M4 ;
        RECT  208.164 126.24 208.248 126.264 ;
    END
  END so_row[21]
  PIN so_row[22]
    DIRECTION INPUT ;
    USE SIGNAL ;
    PORT
      LAYER M4 ;
        RECT  208.164 126.336 208.248 126.36 ;
    END
  END so_row[22]
  PIN so_row[23]
    DIRECTION INPUT ;
    USE SIGNAL ;
    PORT
      LAYER M4 ;
        RECT  208.164 126.432 208.248 126.456 ;
    END
  END so_row[23]
  PIN so_row[24]
    DIRECTION INPUT ;
    USE SIGNAL ;
    PORT
      LAYER M4 ;
        RECT  208.164 126.528 208.248 126.552 ;
    END
  END so_row[24]
  PIN so_row[25]
    DIRECTION INPUT ;
    USE SIGNAL ;
    PORT
      LAYER M4 ;
        RECT  208.164 126.624 208.248 126.648 ;
    END
  END so_row[25]
  PIN so_row[26]
    DIRECTION INPUT ;
    USE SIGNAL ;
    PORT
      LAYER M4 ;
        RECT  208.164 126.72 208.248 126.744 ;
    END
  END so_row[26]
  PIN so_row[27]
    DIRECTION INPUT ;
    USE SIGNAL ;
    PORT
      LAYER M4 ;
        RECT  208.164 126.816 208.248 126.84 ;
    END
  END so_row[27]
  PIN so_row[28]
    DIRECTION INPUT ;
    USE SIGNAL ;
    PORT
      LAYER M4 ;
        RECT  208.164 126.912 208.248 126.936 ;
    END
  END so_row[28]
  PIN so_row[29]
    DIRECTION INPUT ;
    USE SIGNAL ;
    PORT
      LAYER M4 ;
        RECT  208.164 127.008 208.248 127.032 ;
    END
  END so_row[29]
  PIN so_row[2]
    DIRECTION INPUT ;
    USE SIGNAL ;
    PORT
      LAYER M4 ;
        RECT  208.164 124.416 208.248 124.44 ;
    END
  END so_row[2]
  PIN so_row[30]
    DIRECTION INPUT ;
    USE SIGNAL ;
    PORT
      LAYER M4 ;
        RECT  208.164 127.104 208.248 127.128 ;
    END
  END so_row[30]
  PIN so_row[31]
    DIRECTION INPUT ;
    USE SIGNAL ;
    PORT
      LAYER M4 ;
        RECT  208.164 127.2 208.248 127.224 ;
    END
  END so_row[31]
  PIN so_row[32]
    DIRECTION INPUT ;
    USE SIGNAL ;
    PORT
      LAYER M4 ;
        RECT  208.164 127.296 208.248 127.32 ;
    END
  END so_row[32]
  PIN so_row[33]
    DIRECTION INPUT ;
    USE SIGNAL ;
    PORT
      LAYER M4 ;
        RECT  208.164 127.392 208.248 127.416 ;
    END
  END so_row[33]
  PIN so_row[34]
    DIRECTION INPUT ;
    USE SIGNAL ;
    PORT
      LAYER M4 ;
        RECT  208.164 127.488 208.248 127.512 ;
    END
  END so_row[34]
  PIN so_row[35]
    DIRECTION INPUT ;
    USE SIGNAL ;
    PORT
      LAYER M4 ;
        RECT  208.164 127.584 208.248 127.608 ;
    END
  END so_row[35]
  PIN so_row[36]
    DIRECTION INPUT ;
    USE SIGNAL ;
    PORT
      LAYER M4 ;
        RECT  208.164 127.68 208.248 127.704 ;
    END
  END so_row[36]
  PIN so_row[37]
    DIRECTION INPUT ;
    USE SIGNAL ;
    PORT
      LAYER M4 ;
        RECT  208.164 127.776 208.248 127.8 ;
    END
  END so_row[37]
  PIN so_row[38]
    DIRECTION INPUT ;
    USE SIGNAL ;
    PORT
      LAYER M4 ;
        RECT  208.164 127.872 208.248 127.896 ;
    END
  END so_row[38]
  PIN so_row[39]
    DIRECTION INPUT ;
    USE SIGNAL ;
    PORT
      LAYER M4 ;
        RECT  208.164 127.968 208.248 127.992 ;
    END
  END so_row[39]
  PIN so_row[3]
    DIRECTION INPUT ;
    USE SIGNAL ;
    PORT
      LAYER M4 ;
        RECT  208.164 124.512 208.248 124.536 ;
    END
  END so_row[3]
  PIN so_row[40]
    DIRECTION INPUT ;
    USE SIGNAL ;
    PORT
      LAYER M4 ;
        RECT  208.164 128.064 208.248 128.088 ;
    END
  END so_row[40]
  PIN so_row[41]
    DIRECTION INPUT ;
    USE SIGNAL ;
    PORT
      LAYER M4 ;
        RECT  208.164 128.16 208.248 128.184 ;
    END
  END so_row[41]
  PIN so_row[42]
    DIRECTION INPUT ;
    USE SIGNAL ;
    PORT
      LAYER M4 ;
        RECT  208.164 128.256 208.248 128.28 ;
    END
  END so_row[42]
  PIN so_row[43]
    DIRECTION INPUT ;
    USE SIGNAL ;
    PORT
      LAYER M4 ;
        RECT  208.164 128.352 208.248 128.376 ;
    END
  END so_row[43]
  PIN so_row[44]
    DIRECTION INPUT ;
    USE SIGNAL ;
    PORT
      LAYER M4 ;
        RECT  208.164 128.448 208.248 128.472 ;
    END
  END so_row[44]
  PIN so_row[45]
    DIRECTION INPUT ;
    USE SIGNAL ;
    PORT
      LAYER M4 ;
        RECT  208.164 128.544 208.248 128.568 ;
    END
  END so_row[45]
  PIN so_row[46]
    DIRECTION INPUT ;
    USE SIGNAL ;
    PORT
      LAYER M4 ;
        RECT  208.164 128.64 208.248 128.664 ;
    END
  END so_row[46]
  PIN so_row[47]
    DIRECTION INPUT ;
    USE SIGNAL ;
    PORT
      LAYER M4 ;
        RECT  208.164 128.736 208.248 128.76 ;
    END
  END so_row[47]
  PIN so_row[48]
    DIRECTION INPUT ;
    USE SIGNAL ;
    PORT
      LAYER M4 ;
        RECT  208.164 128.832 208.248 128.856 ;
    END
  END so_row[48]
  PIN so_row[49]
    DIRECTION INPUT ;
    USE SIGNAL ;
    PORT
      LAYER M4 ;
        RECT  208.164 128.928 208.248 128.952 ;
    END
  END so_row[49]
  PIN so_row[4]
    DIRECTION INPUT ;
    USE SIGNAL ;
    PORT
      LAYER M4 ;
        RECT  208.164 124.608 208.248 124.632 ;
    END
  END so_row[4]
  PIN so_row[50]
    DIRECTION INPUT ;
    USE SIGNAL ;
    PORT
      LAYER M4 ;
        RECT  208.164 129.024 208.248 129.048 ;
    END
  END so_row[50]
  PIN so_row[51]
    DIRECTION INPUT ;
    USE SIGNAL ;
    PORT
      LAYER M4 ;
        RECT  208.164 129.12 208.248 129.144 ;
    END
  END so_row[51]
  PIN so_row[52]
    DIRECTION INPUT ;
    USE SIGNAL ;
    PORT
      LAYER M4 ;
        RECT  208.164 129.216 208.248 129.24 ;
    END
  END so_row[52]
  PIN so_row[53]
    DIRECTION INPUT ;
    USE SIGNAL ;
    PORT
      LAYER M4 ;
        RECT  208.164 129.312 208.248 129.336 ;
    END
  END so_row[53]
  PIN so_row[54]
    DIRECTION INPUT ;
    USE SIGNAL ;
    PORT
      LAYER M4 ;
        RECT  208.164 129.408 208.248 129.432 ;
    END
  END so_row[54]
  PIN so_row[55]
    DIRECTION INPUT ;
    USE SIGNAL ;
    PORT
      LAYER M4 ;
        RECT  208.164 129.504 208.248 129.528 ;
    END
  END so_row[55]
  PIN so_row[56]
    DIRECTION INPUT ;
    USE SIGNAL ;
    PORT
      LAYER M4 ;
        RECT  208.164 129.6 208.248 129.624 ;
    END
  END so_row[56]
  PIN so_row[57]
    DIRECTION INPUT ;
    USE SIGNAL ;
    PORT
      LAYER M4 ;
        RECT  208.164 129.696 208.248 129.72 ;
    END
  END so_row[57]
  PIN so_row[58]
    DIRECTION INPUT ;
    USE SIGNAL ;
    PORT
      LAYER M4 ;
        RECT  208.164 129.792 208.248 129.816 ;
    END
  END so_row[58]
  PIN so_row[59]
    DIRECTION INPUT ;
    USE SIGNAL ;
    PORT
      LAYER M4 ;
        RECT  208.164 129.888 208.248 129.912 ;
    END
  END so_row[59]
  PIN so_row[5]
    DIRECTION INPUT ;
    USE SIGNAL ;
    PORT
      LAYER M4 ;
        RECT  208.164 124.704 208.248 124.728 ;
    END
  END so_row[5]
  PIN so_row[60]
    DIRECTION INPUT ;
    USE SIGNAL ;
    PORT
      LAYER M4 ;
        RECT  208.164 129.984 208.248 130.008 ;
    END
  END so_row[60]
  PIN so_row[61]
    DIRECTION INPUT ;
    USE SIGNAL ;
    PORT
      LAYER M4 ;
        RECT  208.164 130.08 208.248 130.104 ;
    END
  END so_row[61]
  PIN so_row[62]
    DIRECTION INPUT ;
    USE SIGNAL ;
    PORT
      LAYER M4 ;
        RECT  208.164 130.176 208.248 130.2 ;
    END
  END so_row[62]
  PIN so_row[63]
    DIRECTION INPUT ;
    USE SIGNAL ;
    PORT
      LAYER M4 ;
        RECT  208.164 130.272 208.248 130.296 ;
    END
  END so_row[63]
  PIN so_row[64]
    DIRECTION INPUT ;
    USE SIGNAL ;
    PORT
      LAYER M4 ;
        RECT  208.164 130.368 208.248 130.392 ;
    END
  END so_row[64]
  PIN so_row[65]
    DIRECTION INPUT ;
    USE SIGNAL ;
    PORT
      LAYER M4 ;
        RECT  208.164 130.464 208.248 130.488 ;
    END
  END so_row[65]
  PIN so_row[66]
    DIRECTION INPUT ;
    USE SIGNAL ;
    PORT
      LAYER M4 ;
        RECT  208.164 130.56 208.248 130.584 ;
    END
  END so_row[66]
  PIN so_row[67]
    DIRECTION INPUT ;
    USE SIGNAL ;
    PORT
      LAYER M4 ;
        RECT  208.164 130.656 208.248 130.68 ;
    END
  END so_row[67]
  PIN so_row[68]
    DIRECTION INPUT ;
    USE SIGNAL ;
    PORT
      LAYER M4 ;
        RECT  208.164 130.752 208.248 130.776 ;
    END
  END so_row[68]
  PIN so_row[69]
    DIRECTION INPUT ;
    USE SIGNAL ;
    PORT
      LAYER M4 ;
        RECT  208.164 130.848 208.248 130.872 ;
    END
  END so_row[69]
  PIN so_row[6]
    DIRECTION INPUT ;
    USE SIGNAL ;
    PORT
      LAYER M4 ;
        RECT  208.164 124.8 208.248 124.824 ;
    END
  END so_row[6]
  PIN so_row[70]
    DIRECTION INPUT ;
    USE SIGNAL ;
    PORT
      LAYER M4 ;
        RECT  208.164 130.944 208.248 130.968 ;
    END
  END so_row[70]
  PIN so_row[71]
    DIRECTION INPUT ;
    USE SIGNAL ;
    PORT
      LAYER M4 ;
        RECT  208.164 131.04 208.248 131.064 ;
    END
  END so_row[71]
  PIN so_row[72]
    DIRECTION INPUT ;
    USE SIGNAL ;
    PORT
      LAYER M4 ;
        RECT  208.164 131.136 208.248 131.16 ;
    END
  END so_row[72]
  PIN so_row[73]
    DIRECTION INPUT ;
    USE SIGNAL ;
    PORT
      LAYER M4 ;
        RECT  208.164 131.232 208.248 131.256 ;
    END
  END so_row[73]
  PIN so_row[74]
    DIRECTION INPUT ;
    USE SIGNAL ;
    PORT
      LAYER M4 ;
        RECT  208.164 131.328 208.248 131.352 ;
    END
  END so_row[74]
  PIN so_row[75]
    DIRECTION INPUT ;
    USE SIGNAL ;
    PORT
      LAYER M4 ;
        RECT  208.164 131.424 208.248 131.448 ;
    END
  END so_row[75]
  PIN so_row[76]
    DIRECTION INPUT ;
    USE SIGNAL ;
    PORT
      LAYER M4 ;
        RECT  208.164 131.52 208.248 131.544 ;
    END
  END so_row[76]
  PIN so_row[77]
    DIRECTION INPUT ;
    USE SIGNAL ;
    PORT
      LAYER M4 ;
        RECT  208.164 131.616 208.248 131.64 ;
    END
  END so_row[77]
  PIN so_row[78]
    DIRECTION INPUT ;
    USE SIGNAL ;
    PORT
      LAYER M4 ;
        RECT  208.164 131.712 208.248 131.736 ;
    END
  END so_row[78]
  PIN so_row[79]
    DIRECTION INPUT ;
    USE SIGNAL ;
    PORT
      LAYER M4 ;
        RECT  208.164 131.808 208.248 131.832 ;
    END
  END so_row[79]
  PIN so_row[7]
    DIRECTION INPUT ;
    USE SIGNAL ;
    PORT
      LAYER M4 ;
        RECT  208.164 124.896 208.248 124.92 ;
    END
  END so_row[7]
  PIN so_row[80]
    DIRECTION INPUT ;
    USE SIGNAL ;
    PORT
      LAYER M4 ;
        RECT  208.164 131.904 208.248 131.928 ;
    END
  END so_row[80]
  PIN so_row[81]
    DIRECTION INPUT ;
    USE SIGNAL ;
    PORT
      LAYER M4 ;
        RECT  208.164 132 208.248 132.024 ;
    END
  END so_row[81]
  PIN so_row[82]
    DIRECTION INPUT ;
    USE SIGNAL ;
    PORT
      LAYER M4 ;
        RECT  208.164 132.096 208.248 132.12 ;
    END
  END so_row[82]
  PIN so_row[83]
    DIRECTION INPUT ;
    USE SIGNAL ;
    PORT
      LAYER M4 ;
        RECT  208.164 132.192 208.248 132.216 ;
    END
  END so_row[83]
  PIN so_row[84]
    DIRECTION INPUT ;
    USE SIGNAL ;
    PORT
      LAYER M4 ;
        RECT  208.164 132.288 208.248 132.312 ;
    END
  END so_row[84]
  PIN so_row[85]
    DIRECTION INPUT ;
    USE SIGNAL ;
    PORT
      LAYER M4 ;
        RECT  208.164 132.384 208.248 132.408 ;
    END
  END so_row[85]
  PIN so_row[86]
    DIRECTION INPUT ;
    USE SIGNAL ;
    PORT
      LAYER M4 ;
        RECT  208.164 132.48 208.248 132.504 ;
    END
  END so_row[86]
  PIN so_row[87]
    DIRECTION INPUT ;
    USE SIGNAL ;
    PORT
      LAYER M4 ;
        RECT  208.164 132.576 208.248 132.6 ;
    END
  END so_row[87]
  PIN so_row[88]
    DIRECTION INPUT ;
    USE SIGNAL ;
    PORT
      LAYER M4 ;
        RECT  208.164 132.672 208.248 132.696 ;
    END
  END so_row[88]
  PIN so_row[89]
    DIRECTION INPUT ;
    USE SIGNAL ;
    PORT
      LAYER M4 ;
        RECT  208.164 132.768 208.248 132.792 ;
    END
  END so_row[89]
  PIN so_row[8]
    DIRECTION INPUT ;
    USE SIGNAL ;
    PORT
      LAYER M4 ;
        RECT  208.164 124.992 208.248 125.016 ;
    END
  END so_row[8]
  PIN so_row[90]
    DIRECTION INPUT ;
    USE SIGNAL ;
    PORT
      LAYER M4 ;
        RECT  208.164 132.864 208.248 132.888 ;
    END
  END so_row[90]
  PIN so_row[91]
    DIRECTION INPUT ;
    USE SIGNAL ;
    PORT
      LAYER M4 ;
        RECT  208.164 132.96 208.248 132.984 ;
    END
  END so_row[91]
  PIN so_row[92]
    DIRECTION INPUT ;
    USE SIGNAL ;
    PORT
      LAYER M4 ;
        RECT  208.164 133.056 208.248 133.08 ;
    END
  END so_row[92]
  PIN so_row[93]
    DIRECTION INPUT ;
    USE SIGNAL ;
    PORT
      LAYER M4 ;
        RECT  208.164 133.152 208.248 133.176 ;
    END
  END so_row[93]
  PIN so_row[94]
    DIRECTION INPUT ;
    USE SIGNAL ;
    PORT
      LAYER M4 ;
        RECT  208.164 133.248 208.248 133.272 ;
    END
  END so_row[94]
  PIN so_row[95]
    DIRECTION INPUT ;
    USE SIGNAL ;
    PORT
      LAYER M4 ;
        RECT  208.164 133.344 208.248 133.368 ;
    END
  END so_row[95]
  PIN so_row[96]
    DIRECTION INPUT ;
    USE SIGNAL ;
    PORT
      LAYER M4 ;
        RECT  208.164 133.44 208.248 133.464 ;
    END
  END so_row[96]
  PIN so_row[97]
    DIRECTION INPUT ;
    USE SIGNAL ;
    PORT
      LAYER M4 ;
        RECT  208.164 133.536 208.248 133.56 ;
    END
  END so_row[97]
  PIN so_row[98]
    DIRECTION INPUT ;
    USE SIGNAL ;
    PORT
      LAYER M4 ;
        RECT  208.164 133.632 208.248 133.656 ;
    END
  END so_row[98]
  PIN so_row[99]
    DIRECTION INPUT ;
    USE SIGNAL ;
    PORT
      LAYER M4 ;
        RECT  208.164 133.728 208.248 133.752 ;
    END
  END so_row[99]
  PIN so_row[9]
    DIRECTION INPUT ;
    USE SIGNAL ;
    PORT
      LAYER M4 ;
        RECT  208.164 125.088 208.248 125.112 ;
    END
  END so_row[9]
  PIN ze_d
    DIRECTION INPUT ;
    USE SIGNAL ;
    PORT
      LAYER M4 ;
        RECT  208.164 136.512 208.248 136.536 ;
    END
  END ze_d
  PIN VSS
    DIRECTION INOUT ;
    USE GROUND ;
    PORT
      LAYER M5 ;
        RECT  200.724 4.297 200.844 194.423 ;
        RECT  196.404 4.297 196.524 194.423 ;
        RECT  192.084 4.297 192.204 194.423 ;
        RECT  187.764 4.297 187.884 194.423 ;
        RECT  183.444 4.297 183.564 194.423 ;
        RECT  179.124 4.297 179.244 194.423 ;
        RECT  174.804 4.297 174.924 194.423 ;
        RECT  170.484 4.297 170.604 194.423 ;
        RECT  166.164 4.297 166.284 194.423 ;
        RECT  161.844 4.297 161.964 194.423 ;
        RECT  157.524 4.297 157.644 194.423 ;
        RECT  153.204 4.297 153.324 194.423 ;
        RECT  148.884 4.297 149.004 194.423 ;
        RECT  144.564 4.297 144.684 194.423 ;
        RECT  140.244 4.297 140.364 194.423 ;
        RECT  135.924 4.297 136.044 194.423 ;
        RECT  131.604 4.297 131.724 194.423 ;
        RECT  127.284 4.297 127.404 194.423 ;
        RECT  122.964 4.297 123.084 194.423 ;
        RECT  118.644 4.297 118.764 194.423 ;
        RECT  114.324 4.297 114.444 194.423 ;
        RECT  110.004 4.297 110.124 194.423 ;
        RECT  105.684 4.297 105.804 194.423 ;
        RECT  101.364 4.297 101.484 194.423 ;
        RECT  97.044 4.297 97.164 194.423 ;
        RECT  92.724 4.297 92.844 194.423 ;
        RECT  88.404 4.297 88.524 194.423 ;
        RECT  84.084 4.297 84.204 194.423 ;
        RECT  79.764 4.297 79.884 194.423 ;
        RECT  75.444 4.297 75.564 194.423 ;
        RECT  71.124 4.297 71.244 194.423 ;
        RECT  66.804 4.297 66.924 194.423 ;
        RECT  62.484 4.297 62.604 194.423 ;
        RECT  58.164 4.297 58.284 194.423 ;
        RECT  53.844 4.297 53.964 194.423 ;
        RECT  49.524 4.297 49.644 194.423 ;
        RECT  45.204 4.297 45.324 194.423 ;
        RECT  40.884 4.297 41.004 194.423 ;
        RECT  36.564 4.297 36.684 194.423 ;
        RECT  32.244 4.297 32.364 194.423 ;
        RECT  27.924 4.297 28.044 194.423 ;
        RECT  23.604 4.297 23.724 194.423 ;
        RECT  19.284 4.297 19.404 194.423 ;
        RECT  14.964 4.297 15.084 194.423 ;
        RECT  10.644 4.297 10.764 194.423 ;
        RECT  6.324 4.297 6.444 194.423 ;
    END
  END VSS
  PIN VDD
    DIRECTION INOUT ;
    USE POWER ;
    PORT
      LAYER M5 ;
        RECT  200.916 4.311 201.036 194.409 ;
        RECT  196.596 4.311 196.716 194.409 ;
        RECT  192.276 4.311 192.396 194.409 ;
        RECT  187.956 4.311 188.076 194.409 ;
        RECT  183.636 4.311 183.756 194.409 ;
        RECT  179.316 4.311 179.436 194.409 ;
        RECT  174.996 4.311 175.116 194.409 ;
        RECT  170.676 4.311 170.796 194.409 ;
        RECT  166.356 4.311 166.476 194.409 ;
        RECT  162.036 4.311 162.156 194.409 ;
        RECT  157.716 4.311 157.836 194.409 ;
        RECT  153.396 4.311 153.516 194.409 ;
        RECT  149.076 4.311 149.196 194.409 ;
        RECT  144.756 4.311 144.876 194.409 ;
        RECT  140.436 4.311 140.556 194.409 ;
        RECT  136.116 4.311 136.236 194.409 ;
        RECT  131.796 4.311 131.916 194.409 ;
        RECT  127.476 4.311 127.596 194.409 ;
        RECT  123.156 4.311 123.276 194.409 ;
        RECT  118.836 4.311 118.956 194.409 ;
        RECT  114.516 4.311 114.636 194.409 ;
        RECT  110.196 4.311 110.316 194.409 ;
        RECT  105.876 4.311 105.996 194.409 ;
        RECT  101.556 4.311 101.676 194.409 ;
        RECT  97.236 4.311 97.356 194.409 ;
        RECT  92.916 4.311 93.036 194.409 ;
        RECT  88.596 4.311 88.716 194.409 ;
        RECT  84.276 4.311 84.396 194.409 ;
        RECT  79.956 4.311 80.076 194.409 ;
        RECT  75.636 4.311 75.756 194.409 ;
        RECT  71.316 4.311 71.436 194.409 ;
        RECT  66.996 4.311 67.116 194.409 ;
        RECT  62.676 4.311 62.796 194.409 ;
        RECT  58.356 4.311 58.476 194.409 ;
        RECT  54.036 4.311 54.156 194.409 ;
        RECT  49.716 4.311 49.836 194.409 ;
        RECT  45.396 4.311 45.516 194.409 ;
        RECT  41.076 4.311 41.196 194.409 ;
        RECT  36.756 4.311 36.876 194.409 ;
        RECT  32.436 4.311 32.556 194.409 ;
        RECT  28.116 4.311 28.236 194.409 ;
        RECT  23.796 4.311 23.916 194.409 ;
        RECT  19.476 4.311 19.596 194.409 ;
        RECT  15.156 4.311 15.276 194.409 ;
        RECT  10.836 4.311 10.956 194.409 ;
        RECT  6.516 4.311 6.636 194.409 ;
    END
  END VDD
  OBS
    LAYER RVTN ;
     RECT  0 0 208.248 198.72 ;
    LAYER RVTP ;
     RECT  0 0 208.248 198.72 ;
    LAYER M1 ;
     RECT  0 0 208.248 198.72 ;
    LAYER M2 ;
     RECT  0 0 208.248 198.72 ;
    LAYER M3 ;
     RECT  0 0 208.248 198.72 ;
    LAYER M4 ;
     RECT  0 0 208.248 198.72 ;
    LAYER M5 ;
     RECT  0 0 208.248 198.72 ;
    LAYER M6 ;
     RECT  0 0 208.248 198.72 ;
  END
END ot_v41_bf_col3_c
END LIBRARY
